VERSION 5.8 ;
BUSBITCHARS "[]" ;
DIVIDERCHAR "/" ;
UNITS
    DATABASE MICRONS 1000 ;
END UNITS

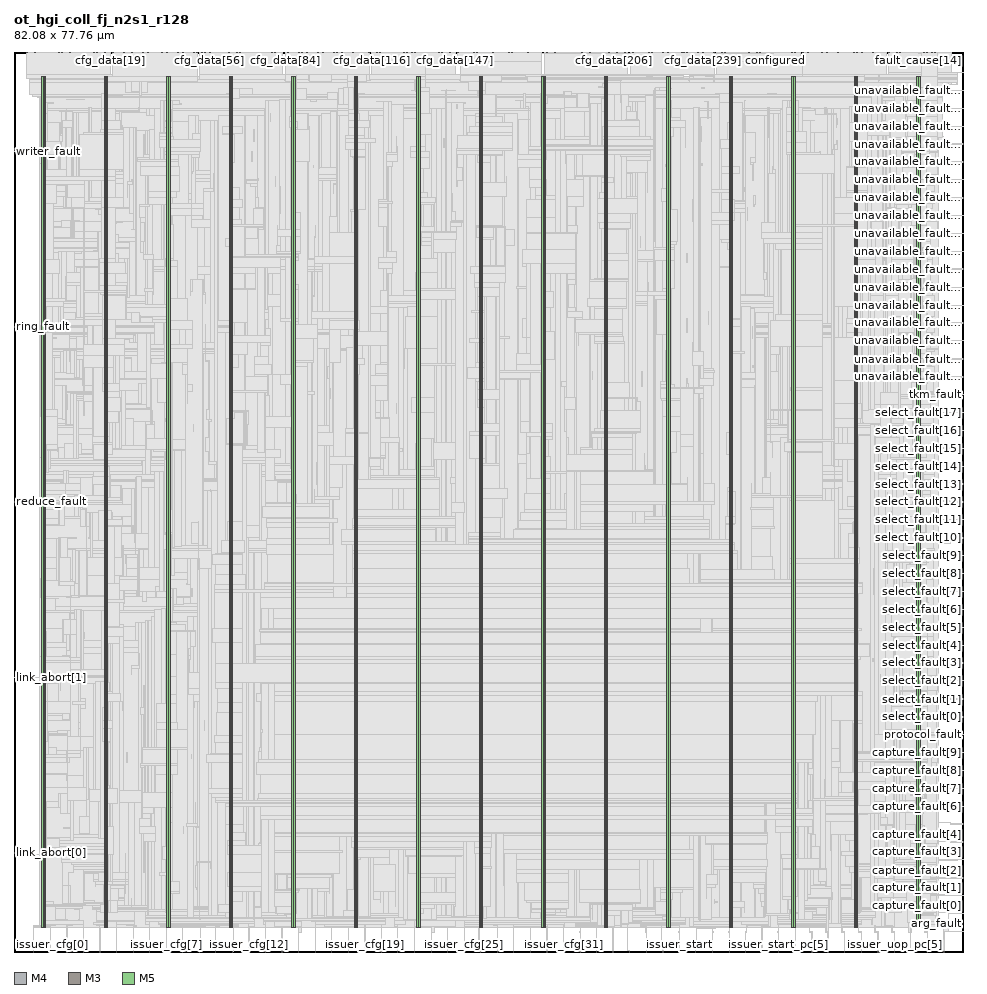
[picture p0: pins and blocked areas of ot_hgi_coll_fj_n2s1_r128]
MACRO ot_hgi_coll_fj_n2s1_r128
  FOREIGN ot_hgi_coll_fj_n2s1_r128 0 0 ;
  CLASS BLOCK ;
  SIZE 82.08 BY 77.76 ;
  PIN arg_fault
    DIRECTION INPUT ;
    USE SIGNAL ;
    PORT
      LAYER M4 ;
        RECT  81.996 1.776 82.08 1.8 ;
    END
  END arg_fault
  PIN capture_fault[0]
    DIRECTION INPUT ;
    USE SIGNAL ;
    PORT
      LAYER M4 ;
        RECT  81.996 3.312 82.08 3.336 ;
    END
  END capture_fault[0]
  PIN capture_fault[1]
    DIRECTION INPUT ;
    USE SIGNAL ;
    PORT
      LAYER M4 ;
        RECT  81.996 4.848 82.08 4.872 ;
    END
  END capture_fault[1]
  PIN capture_fault[2]
    DIRECTION INPUT ;
    USE SIGNAL ;
    PORT
      LAYER M4 ;
        RECT  81.996 6.384 82.08 6.408 ;
    END
  END capture_fault[2]
  PIN capture_fault[3]
    DIRECTION INPUT ;
    USE SIGNAL ;
    PORT
      LAYER M4 ;
        RECT  81.996 7.968 82.08 7.992 ;
    END
  END capture_fault[3]
  PIN capture_fault[4]
    DIRECTION INPUT ;
    USE SIGNAL ;
    PORT
      LAYER M4 ;
        RECT  81.996 9.504 82.08 9.528 ;
    END
  END capture_fault[4]
  PIN capture_fault[5]
    DIRECTION INPUT ;
    USE SIGNAL ;
    PORT
      LAYER M4 ;
        RECT  81.996 11.04 82.08 11.064 ;
    END
  END capture_fault[5]
  PIN capture_fault[6]
    DIRECTION INPUT ;
    USE SIGNAL ;
    PORT
      LAYER M4 ;
        RECT  81.996 12.576 82.08 12.6 ;
    END
  END capture_fault[6]
  PIN capture_fault[7]
    DIRECTION INPUT ;
    USE SIGNAL ;
    PORT
      LAYER M4 ;
        RECT  81.996 14.112 82.08 14.136 ;
    END
  END capture_fault[7]
  PIN capture_fault[8]
    DIRECTION INPUT ;
    USE SIGNAL ;
    PORT
      LAYER M4 ;
        RECT  81.996 15.696 82.08 15.72 ;
    END
  END capture_fault[8]
  PIN capture_fault[9]
    DIRECTION INPUT ;
    USE SIGNAL ;
    PORT
      LAYER M4 ;
        RECT  81.996 17.232 82.08 17.256 ;
    END
  END capture_fault[9]
  PIN cfg_addr[0]
    DIRECTION INPUT ;
    USE SIGNAL ;
    PORT
      LAYER M3 ;
        RECT  1.116 77.722 1.134 77.76 ;
    END
  END cfg_addr[0]
  PIN cfg_addr[10]
    DIRECTION INPUT ;
    USE SIGNAL ;
    PORT
      LAYER M3 ;
        RECT  3.42 77.722 3.438 77.76 ;
    END
  END cfg_addr[10]
  PIN cfg_addr[11]
    DIRECTION INPUT ;
    USE SIGNAL ;
    PORT
      LAYER M3 ;
        RECT  3.672 77.722 3.69 77.76 ;
    END
  END cfg_addr[11]
  PIN cfg_addr[1]
    DIRECTION INPUT ;
    USE SIGNAL ;
    PORT
      LAYER M3 ;
        RECT  1.332 77.722 1.35 77.76 ;
    END
  END cfg_addr[1]
  PIN cfg_addr[2]
    DIRECTION INPUT ;
    USE SIGNAL ;
    PORT
      LAYER M3 ;
        RECT  1.584 77.722 1.602 77.76 ;
    END
  END cfg_addr[2]
  PIN cfg_addr[3]
    DIRECTION INPUT ;
    USE SIGNAL ;
    PORT
      LAYER M3 ;
        RECT  1.8 77.722 1.818 77.76 ;
    END
  END cfg_addr[3]
  PIN cfg_addr[4]
    DIRECTION INPUT ;
    USE SIGNAL ;
    PORT
      LAYER M3 ;
        RECT  2.052 77.722 2.07 77.76 ;
    END
  END cfg_addr[4]
  PIN cfg_addr[5]
    DIRECTION INPUT ;
    USE SIGNAL ;
    PORT
      LAYER M3 ;
        RECT  2.268 77.722 2.286 77.76 ;
    END
  END cfg_addr[5]
  PIN cfg_addr[6]
    DIRECTION INPUT ;
    USE SIGNAL ;
    PORT
      LAYER M3 ;
        RECT  2.52 77.722 2.538 77.76 ;
    END
  END cfg_addr[6]
  PIN cfg_addr[7]
    DIRECTION INPUT ;
    USE SIGNAL ;
    PORT
      LAYER M3 ;
        RECT  2.736 77.722 2.754 77.76 ;
    END
  END cfg_addr[7]
  PIN cfg_addr[8]
    DIRECTION INPUT ;
    USE SIGNAL ;
    PORT
      LAYER M3 ;
        RECT  2.988 77.722 3.006 77.76 ;
    END
  END cfg_addr[8]
  PIN cfg_addr[9]
    DIRECTION INPUT ;
    USE SIGNAL ;
    PORT
      LAYER M3 ;
        RECT  3.204 77.722 3.222 77.76 ;
    END
  END cfg_addr[9]
  PIN cfg_data[0]
    DIRECTION INPUT ;
    USE SIGNAL ;
    PORT
      LAYER M3 ;
        RECT  3.888 77.722 3.906 77.76 ;
    END
  END cfg_data[0]
  PIN cfg_data[100]
    DIRECTION INPUT ;
    USE SIGNAL ;
    PORT
      LAYER M5 ;
        RECT  27.168 77.676 27.192 77.76 ;
    END
  END cfg_data[100]
  PIN cfg_data[101]
    DIRECTION INPUT ;
    USE SIGNAL ;
    PORT
      LAYER M5 ;
        RECT  27.408 77.676 27.432 77.76 ;
    END
  END cfg_data[101]
  PIN cfg_data[102]
    DIRECTION INPUT ;
    USE SIGNAL ;
    PORT
      LAYER M5 ;
        RECT  27.648 77.676 27.672 77.76 ;
    END
  END cfg_data[102]
  PIN cfg_data[103]
    DIRECTION INPUT ;
    USE SIGNAL ;
    PORT
      LAYER M5 ;
        RECT  27.888 77.676 27.912 77.76 ;
    END
  END cfg_data[103]
  PIN cfg_data[104]
    DIRECTION INPUT ;
    USE SIGNAL ;
    PORT
      LAYER M5 ;
        RECT  28.128 77.676 28.152 77.76 ;
    END
  END cfg_data[104]
  PIN cfg_data[105]
    DIRECTION INPUT ;
    USE SIGNAL ;
    PORT
      LAYER M5 ;
        RECT  28.32 77.676 28.344 77.76 ;
    END
  END cfg_data[105]
  PIN cfg_data[106]
    DIRECTION INPUT ;
    USE SIGNAL ;
    PORT
      LAYER M5 ;
        RECT  28.56 77.676 28.584 77.76 ;
    END
  END cfg_data[106]
  PIN cfg_data[107]
    DIRECTION INPUT ;
    USE SIGNAL ;
    PORT
      LAYER M5 ;
        RECT  28.8 77.676 28.824 77.76 ;
    END
  END cfg_data[107]
  PIN cfg_data[108]
    DIRECTION INPUT ;
    USE SIGNAL ;
    PORT
      LAYER M5 ;
        RECT  29.04 77.676 29.064 77.76 ;
    END
  END cfg_data[108]
  PIN cfg_data[109]
    DIRECTION INPUT ;
    USE SIGNAL ;
    PORT
      LAYER M5 ;
        RECT  29.28 77.676 29.304 77.76 ;
    END
  END cfg_data[109]
  PIN cfg_data[10]
    DIRECTION INPUT ;
    USE SIGNAL ;
    PORT
      LAYER M3 ;
        RECT  6.228 77.722 6.246 77.76 ;
    END
  END cfg_data[10]
  PIN cfg_data[110]
    DIRECTION INPUT ;
    USE SIGNAL ;
    PORT
      LAYER M5 ;
        RECT  29.52 77.676 29.544 77.76 ;
    END
  END cfg_data[110]
  PIN cfg_data[111]
    DIRECTION INPUT ;
    USE SIGNAL ;
    PORT
      LAYER M5 ;
        RECT  29.76 77.676 29.784 77.76 ;
    END
  END cfg_data[111]
  PIN cfg_data[112]
    DIRECTION INPUT ;
    USE SIGNAL ;
    PORT
      LAYER M5 ;
        RECT  29.952 77.676 29.976 77.76 ;
    END
  END cfg_data[112]
  PIN cfg_data[113]
    DIRECTION INPUT ;
    USE SIGNAL ;
    PORT
      LAYER M5 ;
        RECT  30.192 77.676 30.216 77.76 ;
    END
  END cfg_data[113]
  PIN cfg_data[114]
    DIRECTION INPUT ;
    USE SIGNAL ;
    PORT
      LAYER M5 ;
        RECT  30.432 77.676 30.456 77.76 ;
    END
  END cfg_data[114]
  PIN cfg_data[115]
    DIRECTION INPUT ;
    USE SIGNAL ;
    PORT
      LAYER M5 ;
        RECT  30.672 77.676 30.696 77.76 ;
    END
  END cfg_data[115]
  PIN cfg_data[116]
    DIRECTION INPUT ;
    USE SIGNAL ;
    PORT
      LAYER M3 ;
        RECT  30.888 77.722 30.906 77.76 ;
    END
  END cfg_data[116]
  PIN cfg_data[117]
    DIRECTION INPUT ;
    USE SIGNAL ;
    PORT
      LAYER M3 ;
        RECT  31.14 77.722 31.158 77.76 ;
    END
  END cfg_data[117]
  PIN cfg_data[118]
    DIRECTION INPUT ;
    USE SIGNAL ;
    PORT
      LAYER M3 ;
        RECT  31.356 77.722 31.374 77.76 ;
    END
  END cfg_data[118]
  PIN cfg_data[119]
    DIRECTION INPUT ;
    USE SIGNAL ;
    PORT
      LAYER M3 ;
        RECT  31.608 77.722 31.626 77.76 ;
    END
  END cfg_data[119]
  PIN cfg_data[11]
    DIRECTION INPUT ;
    USE SIGNAL ;
    PORT
      LAYER M3 ;
        RECT  6.48 77.722 6.498 77.76 ;
    END
  END cfg_data[11]
  PIN cfg_data[120]
    DIRECTION INPUT ;
    USE SIGNAL ;
    PORT
      LAYER M3 ;
        RECT  31.824 77.722 31.842 77.76 ;
    END
  END cfg_data[120]
  PIN cfg_data[121]
    DIRECTION INPUT ;
    USE SIGNAL ;
    PORT
      LAYER M3 ;
        RECT  32.076 77.722 32.094 77.76 ;
    END
  END cfg_data[121]
  PIN cfg_data[122]
    DIRECTION INPUT ;
    USE SIGNAL ;
    PORT
      LAYER M3 ;
        RECT  32.292 77.722 32.31 77.76 ;
    END
  END cfg_data[122]
  PIN cfg_data[123]
    DIRECTION INPUT ;
    USE SIGNAL ;
    PORT
      LAYER M3 ;
        RECT  32.544 77.722 32.562 77.76 ;
    END
  END cfg_data[123]
  PIN cfg_data[124]
    DIRECTION INPUT ;
    USE SIGNAL ;
    PORT
      LAYER M3 ;
        RECT  32.76 77.722 32.778 77.76 ;
    END
  END cfg_data[124]
  PIN cfg_data[125]
    DIRECTION INPUT ;
    USE SIGNAL ;
    PORT
      LAYER M3 ;
        RECT  33.012 77.722 33.03 77.76 ;
    END
  END cfg_data[125]
  PIN cfg_data[126]
    DIRECTION INPUT ;
    USE SIGNAL ;
    PORT
      LAYER M3 ;
        RECT  33.228 77.722 33.246 77.76 ;
    END
  END cfg_data[126]
  PIN cfg_data[127]
    DIRECTION INPUT ;
    USE SIGNAL ;
    PORT
      LAYER M3 ;
        RECT  33.48 77.722 33.498 77.76 ;
    END
  END cfg_data[127]
  PIN cfg_data[128]
    DIRECTION INPUT ;
    USE SIGNAL ;
    PORT
      LAYER M3 ;
        RECT  33.696 77.722 33.714 77.76 ;
    END
  END cfg_data[128]
  PIN cfg_data[129]
    DIRECTION INPUT ;
    USE SIGNAL ;
    PORT
      LAYER M3 ;
        RECT  33.948 77.722 33.966 77.76 ;
    END
  END cfg_data[129]
  PIN cfg_data[12]
    DIRECTION INPUT ;
    USE SIGNAL ;
    PORT
      LAYER M3 ;
        RECT  6.696 77.722 6.714 77.76 ;
    END
  END cfg_data[12]
  PIN cfg_data[130]
    DIRECTION INPUT ;
    USE SIGNAL ;
    PORT
      LAYER M3 ;
        RECT  34.164 77.722 34.182 77.76 ;
    END
  END cfg_data[130]
  PIN cfg_data[131]
    DIRECTION INPUT ;
    USE SIGNAL ;
    PORT
      LAYER M3 ;
        RECT  34.38 77.722 34.398 77.76 ;
    END
  END cfg_data[131]
  PIN cfg_data[132]
    DIRECTION INPUT ;
    USE SIGNAL ;
    PORT
      LAYER M3 ;
        RECT  34.632 77.722 34.65 77.76 ;
    END
  END cfg_data[132]
  PIN cfg_data[133]
    DIRECTION INPUT ;
    USE SIGNAL ;
    PORT
      LAYER M3 ;
        RECT  34.848 77.722 34.866 77.76 ;
    END
  END cfg_data[133]
  PIN cfg_data[134]
    DIRECTION INPUT ;
    USE SIGNAL ;
    PORT
      LAYER M3 ;
        RECT  35.1 77.722 35.118 77.76 ;
    END
  END cfg_data[134]
  PIN cfg_data[135]
    DIRECTION INPUT ;
    USE SIGNAL ;
    PORT
      LAYER M3 ;
        RECT  35.316 77.722 35.334 77.76 ;
    END
  END cfg_data[135]
  PIN cfg_data[136]
    DIRECTION INPUT ;
    USE SIGNAL ;
    PORT
      LAYER M3 ;
        RECT  35.568 77.722 35.586 77.76 ;
    END
  END cfg_data[136]
  PIN cfg_data[137]
    DIRECTION INPUT ;
    USE SIGNAL ;
    PORT
      LAYER M3 ;
        RECT  35.784 77.722 35.802 77.76 ;
    END
  END cfg_data[137]
  PIN cfg_data[138]
    DIRECTION INPUT ;
    USE SIGNAL ;
    PORT
      LAYER M3 ;
        RECT  36.036 77.722 36.054 77.76 ;
    END
  END cfg_data[138]
  PIN cfg_data[139]
    DIRECTION INPUT ;
    USE SIGNAL ;
    PORT
      LAYER M3 ;
        RECT  36.252 77.722 36.27 77.76 ;
    END
  END cfg_data[139]
  PIN cfg_data[13]
    DIRECTION INPUT ;
    USE SIGNAL ;
    PORT
      LAYER M3 ;
        RECT  6.912 77.722 6.93 77.76 ;
    END
  END cfg_data[13]
  PIN cfg_data[140]
    DIRECTION INPUT ;
    USE SIGNAL ;
    PORT
      LAYER M3 ;
        RECT  36.504 77.722 36.522 77.76 ;
    END
  END cfg_data[140]
  PIN cfg_data[141]
    DIRECTION INPUT ;
    USE SIGNAL ;
    PORT
      LAYER M3 ;
        RECT  36.72 77.722 36.738 77.76 ;
    END
  END cfg_data[141]
  PIN cfg_data[142]
    DIRECTION INPUT ;
    USE SIGNAL ;
    PORT
      LAYER M3 ;
        RECT  36.972 77.722 36.99 77.76 ;
    END
  END cfg_data[142]
  PIN cfg_data[143]
    DIRECTION INPUT ;
    USE SIGNAL ;
    PORT
      LAYER M3 ;
        RECT  37.188 77.722 37.206 77.76 ;
    END
  END cfg_data[143]
  PIN cfg_data[144]
    DIRECTION INPUT ;
    USE SIGNAL ;
    PORT
      LAYER M3 ;
        RECT  37.44 77.722 37.458 77.76 ;
    END
  END cfg_data[144]
  PIN cfg_data[145]
    DIRECTION INPUT ;
    USE SIGNAL ;
    PORT
      LAYER M3 ;
        RECT  37.656 77.722 37.674 77.76 ;
    END
  END cfg_data[145]
  PIN cfg_data[146]
    DIRECTION INPUT ;
    USE SIGNAL ;
    PORT
      LAYER M3 ;
        RECT  37.872 77.722 37.89 77.76 ;
    END
  END cfg_data[146]
  PIN cfg_data[147]
    DIRECTION INPUT ;
    USE SIGNAL ;
    PORT
      LAYER M3 ;
        RECT  38.124 77.722 38.142 77.76 ;
    END
  END cfg_data[147]
  PIN cfg_data[148]
    DIRECTION INPUT ;
    USE SIGNAL ;
    PORT
      LAYER M5 ;
        RECT  38.352 77.676 38.376 77.76 ;
    END
  END cfg_data[148]
  PIN cfg_data[149]
    DIRECTION INPUT ;
    USE SIGNAL ;
    PORT
      LAYER M5 ;
        RECT  38.592 77.676 38.616 77.76 ;
    END
  END cfg_data[149]
  PIN cfg_data[14]
    DIRECTION INPUT ;
    USE SIGNAL ;
    PORT
      LAYER M3 ;
        RECT  7.164 77.722 7.182 77.76 ;
    END
  END cfg_data[14]
  PIN cfg_data[150]
    DIRECTION INPUT ;
    USE SIGNAL ;
    PORT
      LAYER M5 ;
        RECT  38.832 77.676 38.856 77.76 ;
    END
  END cfg_data[150]
  PIN cfg_data[151]
    DIRECTION INPUT ;
    USE SIGNAL ;
    PORT
      LAYER M5 ;
        RECT  39.072 77.676 39.096 77.76 ;
    END
  END cfg_data[151]
  PIN cfg_data[152]
    DIRECTION INPUT ;
    USE SIGNAL ;
    PORT
      LAYER M5 ;
        RECT  39.264 77.676 39.288 77.76 ;
    END
  END cfg_data[152]
  PIN cfg_data[153]
    DIRECTION INPUT ;
    USE SIGNAL ;
    PORT
      LAYER M5 ;
        RECT  39.504 77.676 39.528 77.76 ;
    END
  END cfg_data[153]
  PIN cfg_data[154]
    DIRECTION INPUT ;
    USE SIGNAL ;
    PORT
      LAYER M5 ;
        RECT  39.744 77.676 39.768 77.76 ;
    END
  END cfg_data[154]
  PIN cfg_data[155]
    DIRECTION INPUT ;
    USE SIGNAL ;
    PORT
      LAYER M5 ;
        RECT  39.984 77.676 40.008 77.76 ;
    END
  END cfg_data[155]
  PIN cfg_data[156]
    DIRECTION INPUT ;
    USE SIGNAL ;
    PORT
      LAYER M5 ;
        RECT  40.224 77.676 40.248 77.76 ;
    END
  END cfg_data[156]
  PIN cfg_data[157]
    DIRECTION INPUT ;
    USE SIGNAL ;
    PORT
      LAYER M5 ;
        RECT  40.464 77.676 40.488 77.76 ;
    END
  END cfg_data[157]
  PIN cfg_data[158]
    DIRECTION INPUT ;
    USE SIGNAL ;
    PORT
      LAYER M5 ;
        RECT  40.656 77.676 40.68 77.76 ;
    END
  END cfg_data[158]
  PIN cfg_data[159]
    DIRECTION INPUT ;
    USE SIGNAL ;
    PORT
      LAYER M5 ;
        RECT  40.896 77.676 40.92 77.76 ;
    END
  END cfg_data[159]
  PIN cfg_data[15]
    DIRECTION INPUT ;
    USE SIGNAL ;
    PORT
      LAYER M3 ;
        RECT  7.38 77.722 7.398 77.76 ;
    END
  END cfg_data[15]
  PIN cfg_data[160]
    DIRECTION INPUT ;
    USE SIGNAL ;
    PORT
      LAYER M5 ;
        RECT  41.136 77.676 41.16 77.76 ;
    END
  END cfg_data[160]
  PIN cfg_data[161]
    DIRECTION INPUT ;
    USE SIGNAL ;
    PORT
      LAYER M5 ;
        RECT  41.376 77.676 41.4 77.76 ;
    END
  END cfg_data[161]
  PIN cfg_data[162]
    DIRECTION INPUT ;
    USE SIGNAL ;
    PORT
      LAYER M5 ;
        RECT  41.616 77.676 41.64 77.76 ;
    END
  END cfg_data[162]
  PIN cfg_data[163]
    DIRECTION INPUT ;
    USE SIGNAL ;
    PORT
      LAYER M5 ;
        RECT  41.856 77.676 41.88 77.76 ;
    END
  END cfg_data[163]
  PIN cfg_data[164]
    DIRECTION INPUT ;
    USE SIGNAL ;
    PORT
      LAYER M5 ;
        RECT  42.096 77.676 42.12 77.76 ;
    END
  END cfg_data[164]
  PIN cfg_data[165]
    DIRECTION INPUT ;
    USE SIGNAL ;
    PORT
      LAYER M5 ;
        RECT  42.288 77.676 42.312 77.76 ;
    END
  END cfg_data[165]
  PIN cfg_data[166]
    DIRECTION INPUT ;
    USE SIGNAL ;
    PORT
      LAYER M5 ;
        RECT  42.528 77.676 42.552 77.76 ;
    END
  END cfg_data[166]
  PIN cfg_data[167]
    DIRECTION INPUT ;
    USE SIGNAL ;
    PORT
      LAYER M5 ;
        RECT  42.768 77.676 42.792 77.76 ;
    END
  END cfg_data[167]
  PIN cfg_data[168]
    DIRECTION INPUT ;
    USE SIGNAL ;
    PORT
      LAYER M5 ;
        RECT  43.008 77.676 43.032 77.76 ;
    END
  END cfg_data[168]
  PIN cfg_data[169]
    DIRECTION INPUT ;
    USE SIGNAL ;
    PORT
      LAYER M5 ;
        RECT  43.248 77.676 43.272 77.76 ;
    END
  END cfg_data[169]
  PIN cfg_data[16]
    DIRECTION INPUT ;
    USE SIGNAL ;
    PORT
      LAYER M3 ;
        RECT  7.632 77.722 7.65 77.76 ;
    END
  END cfg_data[16]
  PIN cfg_data[170]
    DIRECTION INPUT ;
    USE SIGNAL ;
    PORT
      LAYER M5 ;
        RECT  43.488 77.676 43.512 77.76 ;
    END
  END cfg_data[170]
  PIN cfg_data[171]
    DIRECTION INPUT ;
    USE SIGNAL ;
    PORT
      LAYER M5 ;
        RECT  43.728 77.676 43.752 77.76 ;
    END
  END cfg_data[171]
  PIN cfg_data[172]
    DIRECTION INPUT ;
    USE SIGNAL ;
    PORT
      LAYER M5 ;
        RECT  43.92 77.676 43.944 77.76 ;
    END
  END cfg_data[172]
  PIN cfg_data[173]
    DIRECTION INPUT ;
    USE SIGNAL ;
    PORT
      LAYER M5 ;
        RECT  44.16 77.676 44.184 77.76 ;
    END
  END cfg_data[173]
  PIN cfg_data[174]
    DIRECTION INPUT ;
    USE SIGNAL ;
    PORT
      LAYER M5 ;
        RECT  44.4 77.676 44.424 77.76 ;
    END
  END cfg_data[174]
  PIN cfg_data[175]
    DIRECTION INPUT ;
    USE SIGNAL ;
    PORT
      LAYER M5 ;
        RECT  44.64 77.676 44.664 77.76 ;
    END
  END cfg_data[175]
  PIN cfg_data[176]
    DIRECTION INPUT ;
    USE SIGNAL ;
    PORT
      LAYER M5 ;
        RECT  44.88 77.676 44.904 77.76 ;
    END
  END cfg_data[176]
  PIN cfg_data[177]
    DIRECTION INPUT ;
    USE SIGNAL ;
    PORT
      LAYER M5 ;
        RECT  45.12 77.676 45.144 77.76 ;
    END
  END cfg_data[177]
  PIN cfg_data[178]
    DIRECTION INPUT ;
    USE SIGNAL ;
    PORT
      LAYER M5 ;
        RECT  45.312 77.676 45.336 77.76 ;
    END
  END cfg_data[178]
  PIN cfg_data[179]
    DIRECTION INPUT ;
    USE SIGNAL ;
    PORT
      LAYER M5 ;
        RECT  45.552 77.676 45.576 77.76 ;
    END
  END cfg_data[179]
  PIN cfg_data[17]
    DIRECTION INPUT ;
    USE SIGNAL ;
    PORT
      LAYER M3 ;
        RECT  7.848 77.722 7.866 77.76 ;
    END
  END cfg_data[17]
  PIN cfg_data[180]
    DIRECTION INPUT ;
    USE SIGNAL ;
    PORT
      LAYER M3 ;
        RECT  45.792 77.722 45.81 77.76 ;
    END
  END cfg_data[180]
  PIN cfg_data[181]
    DIRECTION INPUT ;
    USE SIGNAL ;
    PORT
      LAYER M3 ;
        RECT  46.044 77.722 46.062 77.76 ;
    END
  END cfg_data[181]
  PIN cfg_data[182]
    DIRECTION INPUT ;
    USE SIGNAL ;
    PORT
      LAYER M3 ;
        RECT  46.26 77.722 46.278 77.76 ;
    END
  END cfg_data[182]
  PIN cfg_data[183]
    DIRECTION INPUT ;
    USE SIGNAL ;
    PORT
      LAYER M3 ;
        RECT  46.512 77.722 46.53 77.76 ;
    END
  END cfg_data[183]
  PIN cfg_data[184]
    DIRECTION INPUT ;
    USE SIGNAL ;
    PORT
      LAYER M3 ;
        RECT  46.728 77.722 46.746 77.76 ;
    END
  END cfg_data[184]
  PIN cfg_data[185]
    DIRECTION INPUT ;
    USE SIGNAL ;
    PORT
      LAYER M3 ;
        RECT  46.98 77.722 46.998 77.76 ;
    END
  END cfg_data[185]
  PIN cfg_data[186]
    DIRECTION INPUT ;
    USE SIGNAL ;
    PORT
      LAYER M3 ;
        RECT  47.196 77.722 47.214 77.76 ;
    END
  END cfg_data[186]
  PIN cfg_data[187]
    DIRECTION INPUT ;
    USE SIGNAL ;
    PORT
      LAYER M3 ;
        RECT  47.448 77.722 47.466 77.76 ;
    END
  END cfg_data[187]
  PIN cfg_data[188]
    DIRECTION INPUT ;
    USE SIGNAL ;
    PORT
      LAYER M3 ;
        RECT  47.664 77.722 47.682 77.76 ;
    END
  END cfg_data[188]
  PIN cfg_data[189]
    DIRECTION INPUT ;
    USE SIGNAL ;
    PORT
      LAYER M3 ;
        RECT  47.916 77.722 47.934 77.76 ;
    END
  END cfg_data[189]
  PIN cfg_data[18]
    DIRECTION INPUT ;
    USE SIGNAL ;
    PORT
      LAYER M3 ;
        RECT  8.1 77.722 8.118 77.76 ;
    END
  END cfg_data[18]
  PIN cfg_data[190]
    DIRECTION INPUT ;
    USE SIGNAL ;
    PORT
      LAYER M3 ;
        RECT  48.132 77.722 48.15 77.76 ;
    END
  END cfg_data[190]
  PIN cfg_data[191]
    DIRECTION INPUT ;
    USE SIGNAL ;
    PORT
      LAYER M3 ;
        RECT  48.348 77.722 48.366 77.76 ;
    END
  END cfg_data[191]
  PIN cfg_data[192]
    DIRECTION INPUT ;
    USE SIGNAL ;
    PORT
      LAYER M3 ;
        RECT  48.6 77.722 48.618 77.76 ;
    END
  END cfg_data[192]
  PIN cfg_data[193]
    DIRECTION INPUT ;
    USE SIGNAL ;
    PORT
      LAYER M3 ;
        RECT  48.816 77.722 48.834 77.76 ;
    END
  END cfg_data[193]
  PIN cfg_data[194]
    DIRECTION INPUT ;
    USE SIGNAL ;
    PORT
      LAYER M3 ;
        RECT  49.068 77.722 49.086 77.76 ;
    END
  END cfg_data[194]
  PIN cfg_data[195]
    DIRECTION INPUT ;
    USE SIGNAL ;
    PORT
      LAYER M3 ;
        RECT  49.284 77.722 49.302 77.76 ;
    END
  END cfg_data[195]
  PIN cfg_data[196]
    DIRECTION INPUT ;
    USE SIGNAL ;
    PORT
      LAYER M3 ;
        RECT  49.536 77.722 49.554 77.76 ;
    END
  END cfg_data[196]
  PIN cfg_data[197]
    DIRECTION INPUT ;
    USE SIGNAL ;
    PORT
      LAYER M3 ;
        RECT  49.752 77.722 49.77 77.76 ;
    END
  END cfg_data[197]
  PIN cfg_data[198]
    DIRECTION INPUT ;
    USE SIGNAL ;
    PORT
      LAYER M3 ;
        RECT  50.004 77.722 50.022 77.76 ;
    END
  END cfg_data[198]
  PIN cfg_data[199]
    DIRECTION INPUT ;
    USE SIGNAL ;
    PORT
      LAYER M3 ;
        RECT  50.22 77.722 50.238 77.76 ;
    END
  END cfg_data[199]
  PIN cfg_data[19]
    DIRECTION INPUT ;
    USE SIGNAL ;
    PORT
      LAYER M3 ;
        RECT  8.316 77.722 8.334 77.76 ;
    END
  END cfg_data[19]
  PIN cfg_data[1]
    DIRECTION INPUT ;
    USE SIGNAL ;
    PORT
      LAYER M3 ;
        RECT  4.14 77.722 4.158 77.76 ;
    END
  END cfg_data[1]
  PIN cfg_data[200]
    DIRECTION INPUT ;
    USE SIGNAL ;
    PORT
      LAYER M3 ;
        RECT  50.472 77.722 50.49 77.76 ;
    END
  END cfg_data[200]
  PIN cfg_data[201]
    DIRECTION INPUT ;
    USE SIGNAL ;
    PORT
      LAYER M3 ;
        RECT  50.688 77.722 50.706 77.76 ;
    END
  END cfg_data[201]
  PIN cfg_data[202]
    DIRECTION INPUT ;
    USE SIGNAL ;
    PORT
      LAYER M3 ;
        RECT  50.94 77.722 50.958 77.76 ;
    END
  END cfg_data[202]
  PIN cfg_data[203]
    DIRECTION INPUT ;
    USE SIGNAL ;
    PORT
      LAYER M3 ;
        RECT  51.156 77.722 51.174 77.76 ;
    END
  END cfg_data[203]
  PIN cfg_data[204]
    DIRECTION INPUT ;
    USE SIGNAL ;
    PORT
      LAYER M3 ;
        RECT  51.408 77.722 51.426 77.76 ;
    END
  END cfg_data[204]
  PIN cfg_data[205]
    DIRECTION INPUT ;
    USE SIGNAL ;
    PORT
      LAYER M3 ;
        RECT  51.624 77.722 51.642 77.76 ;
    END
  END cfg_data[205]
  PIN cfg_data[206]
    DIRECTION INPUT ;
    USE SIGNAL ;
    PORT
      LAYER M3 ;
        RECT  51.84 77.722 51.858 77.76 ;
    END
  END cfg_data[206]
  PIN cfg_data[207]
    DIRECTION INPUT ;
    USE SIGNAL ;
    PORT
      LAYER M3 ;
        RECT  52.092 77.722 52.11 77.76 ;
    END
  END cfg_data[207]
  PIN cfg_data[208]
    DIRECTION INPUT ;
    USE SIGNAL ;
    PORT
      LAYER M3 ;
        RECT  52.308 77.722 52.326 77.76 ;
    END
  END cfg_data[208]
  PIN cfg_data[209]
    DIRECTION INPUT ;
    USE SIGNAL ;
    PORT
      LAYER M3 ;
        RECT  52.56 77.722 52.578 77.76 ;
    END
  END cfg_data[209]
  PIN cfg_data[20]
    DIRECTION INPUT ;
    USE SIGNAL ;
    PORT
      LAYER M5 ;
        RECT  8.544 77.676 8.568 77.76 ;
    END
  END cfg_data[20]
  PIN cfg_data[210]
    DIRECTION INPUT ;
    USE SIGNAL ;
    PORT
      LAYER M3 ;
        RECT  52.776 77.722 52.794 77.76 ;
    END
  END cfg_data[210]
  PIN cfg_data[211]
    DIRECTION INPUT ;
    USE SIGNAL ;
    PORT
      LAYER M3 ;
        RECT  53.028 77.722 53.046 77.76 ;
    END
  END cfg_data[211]
  PIN cfg_data[212]
    DIRECTION INPUT ;
    USE SIGNAL ;
    PORT
      LAYER M5 ;
        RECT  53.232 77.676 53.256 77.76 ;
    END
  END cfg_data[212]
  PIN cfg_data[213]
    DIRECTION INPUT ;
    USE SIGNAL ;
    PORT
      LAYER M5 ;
        RECT  53.472 77.676 53.496 77.76 ;
    END
  END cfg_data[213]
  PIN cfg_data[214]
    DIRECTION INPUT ;
    USE SIGNAL ;
    PORT
      LAYER M5 ;
        RECT  53.712 77.676 53.736 77.76 ;
    END
  END cfg_data[214]
  PIN cfg_data[215]
    DIRECTION INPUT ;
    USE SIGNAL ;
    PORT
      LAYER M5 ;
        RECT  53.952 77.676 53.976 77.76 ;
    END
  END cfg_data[215]
  PIN cfg_data[216]
    DIRECTION INPUT ;
    USE SIGNAL ;
    PORT
      LAYER M5 ;
        RECT  54.192 77.676 54.216 77.76 ;
    END
  END cfg_data[216]
  PIN cfg_data[217]
    DIRECTION INPUT ;
    USE SIGNAL ;
    PORT
      LAYER M5 ;
        RECT  54.432 77.676 54.456 77.76 ;
    END
  END cfg_data[217]
  PIN cfg_data[218]
    DIRECTION INPUT ;
    USE SIGNAL ;
    PORT
      LAYER M5 ;
        RECT  54.624 77.676 54.648 77.76 ;
    END
  END cfg_data[218]
  PIN cfg_data[219]
    DIRECTION INPUT ;
    USE SIGNAL ;
    PORT
      LAYER M5 ;
        RECT  54.864 77.676 54.888 77.76 ;
    END
  END cfg_data[219]
  PIN cfg_data[21]
    DIRECTION INPUT ;
    USE SIGNAL ;
    PORT
      LAYER M5 ;
        RECT  8.784 77.676 8.808 77.76 ;
    END
  END cfg_data[21]
  PIN cfg_data[220]
    DIRECTION INPUT ;
    USE SIGNAL ;
    PORT
      LAYER M5 ;
        RECT  55.104 77.676 55.128 77.76 ;
    END
  END cfg_data[220]
  PIN cfg_data[221]
    DIRECTION INPUT ;
    USE SIGNAL ;
    PORT
      LAYER M5 ;
        RECT  55.344 77.676 55.368 77.76 ;
    END
  END cfg_data[221]
  PIN cfg_data[222]
    DIRECTION INPUT ;
    USE SIGNAL ;
    PORT
      LAYER M5 ;
        RECT  55.584 77.676 55.608 77.76 ;
    END
  END cfg_data[222]
  PIN cfg_data[223]
    DIRECTION INPUT ;
    USE SIGNAL ;
    PORT
      LAYER M5 ;
        RECT  55.824 77.676 55.848 77.76 ;
    END
  END cfg_data[223]
  PIN cfg_data[224]
    DIRECTION INPUT ;
    USE SIGNAL ;
    PORT
      LAYER M5 ;
        RECT  56.064 77.676 56.088 77.76 ;
    END
  END cfg_data[224]
  PIN cfg_data[225]
    DIRECTION INPUT ;
    USE SIGNAL ;
    PORT
      LAYER M5 ;
        RECT  56.256 77.676 56.28 77.76 ;
    END
  END cfg_data[225]
  PIN cfg_data[226]
    DIRECTION INPUT ;
    USE SIGNAL ;
    PORT
      LAYER M5 ;
        RECT  56.496 77.676 56.52 77.76 ;
    END
  END cfg_data[226]
  PIN cfg_data[227]
    DIRECTION INPUT ;
    USE SIGNAL ;
    PORT
      LAYER M5 ;
        RECT  56.736 77.676 56.76 77.76 ;
    END
  END cfg_data[227]
  PIN cfg_data[228]
    DIRECTION INPUT ;
    USE SIGNAL ;
    PORT
      LAYER M5 ;
        RECT  56.976 77.676 57 77.76 ;
    END
  END cfg_data[228]
  PIN cfg_data[229]
    DIRECTION INPUT ;
    USE SIGNAL ;
    PORT
      LAYER M5 ;
        RECT  57.216 77.676 57.24 77.76 ;
    END
  END cfg_data[229]
  PIN cfg_data[22]
    DIRECTION INPUT ;
    USE SIGNAL ;
    PORT
      LAYER M5 ;
        RECT  9.024 77.676 9.048 77.76 ;
    END
  END cfg_data[22]
  PIN cfg_data[230]
    DIRECTION INPUT ;
    USE SIGNAL ;
    PORT
      LAYER M5 ;
        RECT  57.456 77.676 57.48 77.76 ;
    END
  END cfg_data[230]
  PIN cfg_data[231]
    DIRECTION INPUT ;
    USE SIGNAL ;
    PORT
      LAYER M5 ;
        RECT  57.696 77.676 57.72 77.76 ;
    END
  END cfg_data[231]
  PIN cfg_data[232]
    DIRECTION INPUT ;
    USE SIGNAL ;
    PORT
      LAYER M5 ;
        RECT  57.888 77.676 57.912 77.76 ;
    END
  END cfg_data[232]
  PIN cfg_data[233]
    DIRECTION INPUT ;
    USE SIGNAL ;
    PORT
      LAYER M5 ;
        RECT  58.128 77.676 58.152 77.76 ;
    END
  END cfg_data[233]
  PIN cfg_data[234]
    DIRECTION INPUT ;
    USE SIGNAL ;
    PORT
      LAYER M5 ;
        RECT  58.368 77.676 58.392 77.76 ;
    END
  END cfg_data[234]
  PIN cfg_data[235]
    DIRECTION INPUT ;
    USE SIGNAL ;
    PORT
      LAYER M5 ;
        RECT  58.608 77.676 58.632 77.76 ;
    END
  END cfg_data[235]
  PIN cfg_data[236]
    DIRECTION INPUT ;
    USE SIGNAL ;
    PORT
      LAYER M5 ;
        RECT  58.848 77.676 58.872 77.76 ;
    END
  END cfg_data[236]
  PIN cfg_data[237]
    DIRECTION INPUT ;
    USE SIGNAL ;
    PORT
      LAYER M5 ;
        RECT  59.088 77.676 59.112 77.76 ;
    END
  END cfg_data[237]
  PIN cfg_data[238]
    DIRECTION INPUT ;
    USE SIGNAL ;
    PORT
      LAYER M5 ;
        RECT  59.28 77.676 59.304 77.76 ;
    END
  END cfg_data[238]
  PIN cfg_data[239]
    DIRECTION INPUT ;
    USE SIGNAL ;
    PORT
      LAYER M5 ;
        RECT  59.52 77.676 59.544 77.76 ;
    END
  END cfg_data[239]
  PIN cfg_data[23]
    DIRECTION INPUT ;
    USE SIGNAL ;
    PORT
      LAYER M5 ;
        RECT  9.264 77.676 9.288 77.76 ;
    END
  END cfg_data[23]
  PIN cfg_data[240]
    DIRECTION INPUT ;
    USE SIGNAL ;
    PORT
      LAYER M5 ;
        RECT  59.76 77.676 59.784 77.76 ;
    END
  END cfg_data[240]
  PIN cfg_data[241]
    DIRECTION INPUT ;
    USE SIGNAL ;
    PORT
      LAYER M5 ;
        RECT  60 77.676 60.024 77.76 ;
    END
  END cfg_data[241]
  PIN cfg_data[242]
    DIRECTION INPUT ;
    USE SIGNAL ;
    PORT
      LAYER M5 ;
        RECT  60.24 77.676 60.264 77.76 ;
    END
  END cfg_data[242]
  PIN cfg_data[243]
    DIRECTION INPUT ;
    USE SIGNAL ;
    PORT
      LAYER M5 ;
        RECT  60.48 77.676 60.504 77.76 ;
    END
  END cfg_data[243]
  PIN cfg_data[244]
    DIRECTION INPUT ;
    USE SIGNAL ;
    PORT
      LAYER M3 ;
        RECT  60.696 77.722 60.714 77.76 ;
    END
  END cfg_data[244]
  PIN cfg_data[245]
    DIRECTION INPUT ;
    USE SIGNAL ;
    PORT
      LAYER M3 ;
        RECT  60.948 77.722 60.966 77.76 ;
    END
  END cfg_data[245]
  PIN cfg_data[246]
    DIRECTION INPUT ;
    USE SIGNAL ;
    PORT
      LAYER M3 ;
        RECT  61.164 77.722 61.182 77.76 ;
    END
  END cfg_data[246]
  PIN cfg_data[247]
    DIRECTION INPUT ;
    USE SIGNAL ;
    PORT
      LAYER M3 ;
        RECT  61.416 77.722 61.434 77.76 ;
    END
  END cfg_data[247]
  PIN cfg_data[248]
    DIRECTION INPUT ;
    USE SIGNAL ;
    PORT
      LAYER M3 ;
        RECT  61.632 77.722 61.65 77.76 ;
    END
  END cfg_data[248]
  PIN cfg_data[249]
    DIRECTION INPUT ;
    USE SIGNAL ;
    PORT
      LAYER M3 ;
        RECT  61.884 77.722 61.902 77.76 ;
    END
  END cfg_data[249]
  PIN cfg_data[24]
    DIRECTION INPUT ;
    USE SIGNAL ;
    PORT
      LAYER M5 ;
        RECT  9.504 77.676 9.528 77.76 ;
    END
  END cfg_data[24]
  PIN cfg_data[250]
    DIRECTION INPUT ;
    USE SIGNAL ;
    PORT
      LAYER M3 ;
        RECT  62.1 77.722 62.118 77.76 ;
    END
  END cfg_data[250]
  PIN cfg_data[251]
    DIRECTION INPUT ;
    USE SIGNAL ;
    PORT
      LAYER M3 ;
        RECT  62.316 77.722 62.334 77.76 ;
    END
  END cfg_data[251]
  PIN cfg_data[252]
    DIRECTION INPUT ;
    USE SIGNAL ;
    PORT
      LAYER M3 ;
        RECT  62.568 77.722 62.586 77.76 ;
    END
  END cfg_data[252]
  PIN cfg_data[253]
    DIRECTION INPUT ;
    USE SIGNAL ;
    PORT
      LAYER M3 ;
        RECT  62.784 77.722 62.802 77.76 ;
    END
  END cfg_data[253]
  PIN cfg_data[254]
    DIRECTION INPUT ;
    USE SIGNAL ;
    PORT
      LAYER M3 ;
        RECT  63.036 77.722 63.054 77.76 ;
    END
  END cfg_data[254]
  PIN cfg_data[255]
    DIRECTION INPUT ;
    USE SIGNAL ;
    PORT
      LAYER M3 ;
        RECT  63.252 77.722 63.27 77.76 ;
    END
  END cfg_data[255]
  PIN cfg_data[25]
    DIRECTION INPUT ;
    USE SIGNAL ;
    PORT
      LAYER M5 ;
        RECT  9.696 77.676 9.72 77.76 ;
    END
  END cfg_data[25]
  PIN cfg_data[26]
    DIRECTION INPUT ;
    USE SIGNAL ;
    PORT
      LAYER M5 ;
        RECT  9.936 77.676 9.96 77.76 ;
    END
  END cfg_data[26]
  PIN cfg_data[27]
    DIRECTION INPUT ;
    USE SIGNAL ;
    PORT
      LAYER M5 ;
        RECT  10.176 77.676 10.2 77.76 ;
    END
  END cfg_data[27]
  PIN cfg_data[28]
    DIRECTION INPUT ;
    USE SIGNAL ;
    PORT
      LAYER M5 ;
        RECT  10.416 77.676 10.44 77.76 ;
    END
  END cfg_data[28]
  PIN cfg_data[29]
    DIRECTION INPUT ;
    USE SIGNAL ;
    PORT
      LAYER M5 ;
        RECT  10.656 77.676 10.68 77.76 ;
    END
  END cfg_data[29]
  PIN cfg_data[2]
    DIRECTION INPUT ;
    USE SIGNAL ;
    PORT
      LAYER M3 ;
        RECT  4.356 77.722 4.374 77.76 ;
    END
  END cfg_data[2]
  PIN cfg_data[30]
    DIRECTION INPUT ;
    USE SIGNAL ;
    PORT
      LAYER M5 ;
        RECT  10.896 77.676 10.92 77.76 ;
    END
  END cfg_data[30]
  PIN cfg_data[31]
    DIRECTION INPUT ;
    USE SIGNAL ;
    PORT
      LAYER M5 ;
        RECT  11.136 77.676 11.16 77.76 ;
    END
  END cfg_data[31]
  PIN cfg_data[32]
    DIRECTION INPUT ;
    USE SIGNAL ;
    PORT
      LAYER M5 ;
        RECT  11.328 77.676 11.352 77.76 ;
    END
  END cfg_data[32]
  PIN cfg_data[33]
    DIRECTION INPUT ;
    USE SIGNAL ;
    PORT
      LAYER M5 ;
        RECT  11.568 77.676 11.592 77.76 ;
    END
  END cfg_data[33]
  PIN cfg_data[34]
    DIRECTION INPUT ;
    USE SIGNAL ;
    PORT
      LAYER M5 ;
        RECT  11.808 77.676 11.832 77.76 ;
    END
  END cfg_data[34]
  PIN cfg_data[35]
    DIRECTION INPUT ;
    USE SIGNAL ;
    PORT
      LAYER M5 ;
        RECT  12.048 77.676 12.072 77.76 ;
    END
  END cfg_data[35]
  PIN cfg_data[36]
    DIRECTION INPUT ;
    USE SIGNAL ;
    PORT
      LAYER M5 ;
        RECT  12.288 77.676 12.312 77.76 ;
    END
  END cfg_data[36]
  PIN cfg_data[37]
    DIRECTION INPUT ;
    USE SIGNAL ;
    PORT
      LAYER M5 ;
        RECT  12.528 77.676 12.552 77.76 ;
    END
  END cfg_data[37]
  PIN cfg_data[38]
    DIRECTION INPUT ;
    USE SIGNAL ;
    PORT
      LAYER M5 ;
        RECT  12.768 77.676 12.792 77.76 ;
    END
  END cfg_data[38]
  PIN cfg_data[39]
    DIRECTION INPUT ;
    USE SIGNAL ;
    PORT
      LAYER M5 ;
        RECT  12.96 77.676 12.984 77.76 ;
    END
  END cfg_data[39]
  PIN cfg_data[3]
    DIRECTION INPUT ;
    USE SIGNAL ;
    PORT
      LAYER M3 ;
        RECT  4.608 77.722 4.626 77.76 ;
    END
  END cfg_data[3]
  PIN cfg_data[40]
    DIRECTION INPUT ;
    USE SIGNAL ;
    PORT
      LAYER M5 ;
        RECT  13.2 77.676 13.224 77.76 ;
    END
  END cfg_data[40]
  PIN cfg_data[41]
    DIRECTION INPUT ;
    USE SIGNAL ;
    PORT
      LAYER M5 ;
        RECT  13.44 77.676 13.464 77.76 ;
    END
  END cfg_data[41]
  PIN cfg_data[42]
    DIRECTION INPUT ;
    USE SIGNAL ;
    PORT
      LAYER M5 ;
        RECT  13.68 77.676 13.704 77.76 ;
    END
  END cfg_data[42]
  PIN cfg_data[43]
    DIRECTION INPUT ;
    USE SIGNAL ;
    PORT
      LAYER M5 ;
        RECT  13.92 77.676 13.944 77.76 ;
    END
  END cfg_data[43]
  PIN cfg_data[44]
    DIRECTION INPUT ;
    USE SIGNAL ;
    PORT
      LAYER M5 ;
        RECT  14.16 77.676 14.184 77.76 ;
    END
  END cfg_data[44]
  PIN cfg_data[45]
    DIRECTION INPUT ;
    USE SIGNAL ;
    PORT
      LAYER M5 ;
        RECT  14.352 77.676 14.376 77.76 ;
    END
  END cfg_data[45]
  PIN cfg_data[46]
    DIRECTION INPUT ;
    USE SIGNAL ;
    PORT
      LAYER M5 ;
        RECT  14.592 77.676 14.616 77.76 ;
    END
  END cfg_data[46]
  PIN cfg_data[47]
    DIRECTION INPUT ;
    USE SIGNAL ;
    PORT
      LAYER M5 ;
        RECT  14.832 77.676 14.856 77.76 ;
    END
  END cfg_data[47]
  PIN cfg_data[48]
    DIRECTION INPUT ;
    USE SIGNAL ;
    PORT
      LAYER M5 ;
        RECT  15.072 77.676 15.096 77.76 ;
    END
  END cfg_data[48]
  PIN cfg_data[49]
    DIRECTION INPUT ;
    USE SIGNAL ;
    PORT
      LAYER M5 ;
        RECT  15.312 77.676 15.336 77.76 ;
    END
  END cfg_data[49]
  PIN cfg_data[4]
    DIRECTION INPUT ;
    USE SIGNAL ;
    PORT
      LAYER M3 ;
        RECT  4.824 77.722 4.842 77.76 ;
    END
  END cfg_data[4]
  PIN cfg_data[50]
    DIRECTION INPUT ;
    USE SIGNAL ;
    PORT
      LAYER M5 ;
        RECT  15.552 77.676 15.576 77.76 ;
    END
  END cfg_data[50]
  PIN cfg_data[51]
    DIRECTION INPUT ;
    USE SIGNAL ;
    PORT
      LAYER M5 ;
        RECT  15.792 77.676 15.816 77.76 ;
    END
  END cfg_data[51]
  PIN cfg_data[52]
    DIRECTION INPUT ;
    USE SIGNAL ;
    PORT
      LAYER M3 ;
        RECT  16.02 77.722 16.038 77.76 ;
    END
  END cfg_data[52]
  PIN cfg_data[53]
    DIRECTION INPUT ;
    USE SIGNAL ;
    PORT
      LAYER M3 ;
        RECT  16.236 77.722 16.254 77.76 ;
    END
  END cfg_data[53]
  PIN cfg_data[54]
    DIRECTION INPUT ;
    USE SIGNAL ;
    PORT
      LAYER M3 ;
        RECT  16.488 77.722 16.506 77.76 ;
    END
  END cfg_data[54]
  PIN cfg_data[55]
    DIRECTION INPUT ;
    USE SIGNAL ;
    PORT
      LAYER M3 ;
        RECT  16.704 77.722 16.722 77.76 ;
    END
  END cfg_data[55]
  PIN cfg_data[56]
    DIRECTION INPUT ;
    USE SIGNAL ;
    PORT
      LAYER M3 ;
        RECT  16.92 77.722 16.938 77.76 ;
    END
  END cfg_data[56]
  PIN cfg_data[57]
    DIRECTION INPUT ;
    USE SIGNAL ;
    PORT
      LAYER M3 ;
        RECT  17.172 77.722 17.19 77.76 ;
    END
  END cfg_data[57]
  PIN cfg_data[58]
    DIRECTION INPUT ;
    USE SIGNAL ;
    PORT
      LAYER M3 ;
        RECT  17.388 77.722 17.406 77.76 ;
    END
  END cfg_data[58]
  PIN cfg_data[59]
    DIRECTION INPUT ;
    USE SIGNAL ;
    PORT
      LAYER M3 ;
        RECT  17.64 77.722 17.658 77.76 ;
    END
  END cfg_data[59]
  PIN cfg_data[5]
    DIRECTION INPUT ;
    USE SIGNAL ;
    PORT
      LAYER M3 ;
        RECT  5.076 77.722 5.094 77.76 ;
    END
  END cfg_data[5]
  PIN cfg_data[60]
    DIRECTION INPUT ;
    USE SIGNAL ;
    PORT
      LAYER M3 ;
        RECT  17.856 77.722 17.874 77.76 ;
    END
  END cfg_data[60]
  PIN cfg_data[61]
    DIRECTION INPUT ;
    USE SIGNAL ;
    PORT
      LAYER M3 ;
        RECT  18.108 77.722 18.126 77.76 ;
    END
  END cfg_data[61]
  PIN cfg_data[62]
    DIRECTION INPUT ;
    USE SIGNAL ;
    PORT
      LAYER M3 ;
        RECT  18.324 77.722 18.342 77.76 ;
    END
  END cfg_data[62]
  PIN cfg_data[63]
    DIRECTION INPUT ;
    USE SIGNAL ;
    PORT
      LAYER M3 ;
        RECT  18.576 77.722 18.594 77.76 ;
    END
  END cfg_data[63]
  PIN cfg_data[64]
    DIRECTION INPUT ;
    USE SIGNAL ;
    PORT
      LAYER M3 ;
        RECT  18.792 77.722 18.81 77.76 ;
    END
  END cfg_data[64]
  PIN cfg_data[65]
    DIRECTION INPUT ;
    USE SIGNAL ;
    PORT
      LAYER M3 ;
        RECT  19.044 77.722 19.062 77.76 ;
    END
  END cfg_data[65]
  PIN cfg_data[66]
    DIRECTION INPUT ;
    USE SIGNAL ;
    PORT
      LAYER M3 ;
        RECT  19.26 77.722 19.278 77.76 ;
    END
  END cfg_data[66]
  PIN cfg_data[67]
    DIRECTION INPUT ;
    USE SIGNAL ;
    PORT
      LAYER M3 ;
        RECT  19.512 77.722 19.53 77.76 ;
    END
  END cfg_data[67]
  PIN cfg_data[68]
    DIRECTION INPUT ;
    USE SIGNAL ;
    PORT
      LAYER M3 ;
        RECT  19.728 77.722 19.746 77.76 ;
    END
  END cfg_data[68]
  PIN cfg_data[69]
    DIRECTION INPUT ;
    USE SIGNAL ;
    PORT
      LAYER M3 ;
        RECT  19.98 77.722 19.998 77.76 ;
    END
  END cfg_data[69]
  PIN cfg_data[6]
    DIRECTION INPUT ;
    USE SIGNAL ;
    PORT
      LAYER M3 ;
        RECT  5.292 77.722 5.31 77.76 ;
    END
  END cfg_data[6]
  PIN cfg_data[70]
    DIRECTION INPUT ;
    USE SIGNAL ;
    PORT
      LAYER M3 ;
        RECT  20.196 77.722 20.214 77.76 ;
    END
  END cfg_data[70]
  PIN cfg_data[71]
    DIRECTION INPUT ;
    USE SIGNAL ;
    PORT
      LAYER M3 ;
        RECT  20.412 77.722 20.43 77.76 ;
    END
  END cfg_data[71]
  PIN cfg_data[72]
    DIRECTION INPUT ;
    USE SIGNAL ;
    PORT
      LAYER M3 ;
        RECT  20.664 77.722 20.682 77.76 ;
    END
  END cfg_data[72]
  PIN cfg_data[73]
    DIRECTION INPUT ;
    USE SIGNAL ;
    PORT
      LAYER M3 ;
        RECT  20.88 77.722 20.898 77.76 ;
    END
  END cfg_data[73]
  PIN cfg_data[74]
    DIRECTION INPUT ;
    USE SIGNAL ;
    PORT
      LAYER M3 ;
        RECT  21.132 77.722 21.15 77.76 ;
    END
  END cfg_data[74]
  PIN cfg_data[75]
    DIRECTION INPUT ;
    USE SIGNAL ;
    PORT
      LAYER M3 ;
        RECT  21.348 77.722 21.366 77.76 ;
    END
  END cfg_data[75]
  PIN cfg_data[76]
    DIRECTION INPUT ;
    USE SIGNAL ;
    PORT
      LAYER M3 ;
        RECT  21.6 77.722 21.618 77.76 ;
    END
  END cfg_data[76]
  PIN cfg_data[77]
    DIRECTION INPUT ;
    USE SIGNAL ;
    PORT
      LAYER M3 ;
        RECT  21.816 77.722 21.834 77.76 ;
    END
  END cfg_data[77]
  PIN cfg_data[78]
    DIRECTION INPUT ;
    USE SIGNAL ;
    PORT
      LAYER M3 ;
        RECT  22.068 77.722 22.086 77.76 ;
    END
  END cfg_data[78]
  PIN cfg_data[79]
    DIRECTION INPUT ;
    USE SIGNAL ;
    PORT
      LAYER M3 ;
        RECT  22.284 77.722 22.302 77.76 ;
    END
  END cfg_data[79]
  PIN cfg_data[7]
    DIRECTION INPUT ;
    USE SIGNAL ;
    PORT
      LAYER M3 ;
        RECT  5.544 77.722 5.562 77.76 ;
    END
  END cfg_data[7]
  PIN cfg_data[80]
    DIRECTION INPUT ;
    USE SIGNAL ;
    PORT
      LAYER M3 ;
        RECT  22.536 77.722 22.554 77.76 ;
    END
  END cfg_data[80]
  PIN cfg_data[81]
    DIRECTION INPUT ;
    USE SIGNAL ;
    PORT
      LAYER M3 ;
        RECT  22.752 77.722 22.77 77.76 ;
    END
  END cfg_data[81]
  PIN cfg_data[82]
    DIRECTION INPUT ;
    USE SIGNAL ;
    PORT
      LAYER M3 ;
        RECT  23.004 77.722 23.022 77.76 ;
    END
  END cfg_data[82]
  PIN cfg_data[83]
    DIRECTION INPUT ;
    USE SIGNAL ;
    PORT
      LAYER M3 ;
        RECT  23.22 77.722 23.238 77.76 ;
    END
  END cfg_data[83]
  PIN cfg_data[84]
    DIRECTION INPUT ;
    USE SIGNAL ;
    PORT
      LAYER M5 ;
        RECT  23.472 77.676 23.496 77.76 ;
    END
  END cfg_data[84]
  PIN cfg_data[85]
    DIRECTION INPUT ;
    USE SIGNAL ;
    PORT
      LAYER M5 ;
        RECT  23.664 77.676 23.688 77.76 ;
    END
  END cfg_data[85]
  PIN cfg_data[86]
    DIRECTION INPUT ;
    USE SIGNAL ;
    PORT
      LAYER M5 ;
        RECT  23.904 77.676 23.928 77.76 ;
    END
  END cfg_data[86]
  PIN cfg_data[87]
    DIRECTION INPUT ;
    USE SIGNAL ;
    PORT
      LAYER M5 ;
        RECT  24.144 77.676 24.168 77.76 ;
    END
  END cfg_data[87]
  PIN cfg_data[88]
    DIRECTION INPUT ;
    USE SIGNAL ;
    PORT
      LAYER M5 ;
        RECT  24.384 77.676 24.408 77.76 ;
    END
  END cfg_data[88]
  PIN cfg_data[89]
    DIRECTION INPUT ;
    USE SIGNAL ;
    PORT
      LAYER M5 ;
        RECT  24.624 77.676 24.648 77.76 ;
    END
  END cfg_data[89]
  PIN cfg_data[8]
    DIRECTION INPUT ;
    USE SIGNAL ;
    PORT
      LAYER M3 ;
        RECT  5.76 77.722 5.778 77.76 ;
    END
  END cfg_data[8]
  PIN cfg_data[90]
    DIRECTION INPUT ;
    USE SIGNAL ;
    PORT
      LAYER M5 ;
        RECT  24.864 77.676 24.888 77.76 ;
    END
  END cfg_data[90]
  PIN cfg_data[91]
    DIRECTION INPUT ;
    USE SIGNAL ;
    PORT
      LAYER M5 ;
        RECT  25.104 77.676 25.128 77.76 ;
    END
  END cfg_data[91]
  PIN cfg_data[92]
    DIRECTION INPUT ;
    USE SIGNAL ;
    PORT
      LAYER M5 ;
        RECT  25.296 77.676 25.32 77.76 ;
    END
  END cfg_data[92]
  PIN cfg_data[93]
    DIRECTION INPUT ;
    USE SIGNAL ;
    PORT
      LAYER M5 ;
        RECT  25.536 77.676 25.56 77.76 ;
    END
  END cfg_data[93]
  PIN cfg_data[94]
    DIRECTION INPUT ;
    USE SIGNAL ;
    PORT
      LAYER M5 ;
        RECT  25.776 77.676 25.8 77.76 ;
    END
  END cfg_data[94]
  PIN cfg_data[95]
    DIRECTION INPUT ;
    USE SIGNAL ;
    PORT
      LAYER M5 ;
        RECT  26.016 77.676 26.04 77.76 ;
    END
  END cfg_data[95]
  PIN cfg_data[96]
    DIRECTION INPUT ;
    USE SIGNAL ;
    PORT
      LAYER M5 ;
        RECT  26.256 77.676 26.28 77.76 ;
    END
  END cfg_data[96]
  PIN cfg_data[97]
    DIRECTION INPUT ;
    USE SIGNAL ;
    PORT
      LAYER M5 ;
        RECT  26.496 77.676 26.52 77.76 ;
    END
  END cfg_data[97]
  PIN cfg_data[98]
    DIRECTION INPUT ;
    USE SIGNAL ;
    PORT
      LAYER M5 ;
        RECT  26.688 77.676 26.712 77.76 ;
    END
  END cfg_data[98]
  PIN cfg_data[99]
    DIRECTION INPUT ;
    USE SIGNAL ;
    PORT
      LAYER M5 ;
        RECT  26.928 77.676 26.952 77.76 ;
    END
  END cfg_data[99]
  PIN cfg_data[9]
    DIRECTION INPUT ;
    USE SIGNAL ;
    PORT
      LAYER M3 ;
        RECT  6.012 77.722 6.03 77.76 ;
    END
  END cfg_data[9]
  PIN cfg_target[0]
    DIRECTION INPUT ;
    USE SIGNAL ;
    PORT
      LAYER M3 ;
        RECT  63.504 77.722 63.522 77.76 ;
    END
  END cfg_target[0]
  PIN cfg_target[1]
    DIRECTION INPUT ;
    USE SIGNAL ;
    PORT
      LAYER M3 ;
        RECT  63.72 77.722 63.738 77.76 ;
    END
  END cfg_target[1]
  PIN cfg_target[2]
    DIRECTION INPUT ;
    USE SIGNAL ;
    PORT
      LAYER M3 ;
        RECT  63.972 77.722 63.99 77.76 ;
    END
  END cfg_target[2]
  PIN cfg_target[3]
    DIRECTION INPUT ;
    USE SIGNAL ;
    PORT
      LAYER M3 ;
        RECT  64.188 77.722 64.206 77.76 ;
    END
  END cfg_target[3]
  PIN cfg_target[4]
    DIRECTION INPUT ;
    USE SIGNAL ;
    PORT
      LAYER M3 ;
        RECT  64.44 77.722 64.458 77.76 ;
    END
  END cfg_target[4]
  PIN cfg_target[5]
    DIRECTION INPUT ;
    USE SIGNAL ;
    PORT
      LAYER M3 ;
        RECT  64.656 77.722 64.674 77.76 ;
    END
  END cfg_target[5]
  PIN cfg_target[6]
    DIRECTION INPUT ;
    USE SIGNAL ;
    PORT
      LAYER M3 ;
        RECT  64.908 77.722 64.926 77.76 ;
    END
  END cfg_target[6]
  PIN cfg_target[7]
    DIRECTION INPUT ;
    USE SIGNAL ;
    PORT
      LAYER M3 ;
        RECT  65.124 77.722 65.142 77.76 ;
    END
  END cfg_target[7]
  PIN cfg_v
    DIRECTION INPUT ;
    USE SIGNAL ;
    PORT
      LAYER M3 ;
        RECT  65.376 77.722 65.394 77.76 ;
    END
  END cfg_v
  PIN clk
    DIRECTION INPUT ;
    USE SIGNAL ;
    PORT
      LAYER M3 ;
        RECT  65.592 77.722 65.61 77.76 ;
    END
  END clk
  PIN configured
    DIRECTION OUTPUT ;
    USE SIGNAL ;
    PORT
      LAYER M3 ;
        RECT  65.808 77.722 65.826 77.76 ;
    END
  END configured
  PIN desc_base[0]
    DIRECTION INPUT ;
    USE SIGNAL ;
    PORT
      LAYER M3 ;
        RECT  66.06 77.722 66.078 77.76 ;
    END
  END desc_base[0]
  PIN desc_base[10]
    DIRECTION INPUT ;
    USE SIGNAL ;
    PORT
      LAYER M5 ;
        RECT  68.4 77.676 68.424 77.76 ;
    END
  END desc_base[10]
  PIN desc_base[11]
    DIRECTION INPUT ;
    USE SIGNAL ;
    PORT
      LAYER M5 ;
        RECT  68.592 77.676 68.616 77.76 ;
    END
  END desc_base[11]
  PIN desc_base[1]
    DIRECTION INPUT ;
    USE SIGNAL ;
    PORT
      LAYER M3 ;
        RECT  66.276 77.722 66.294 77.76 ;
    END
  END desc_base[1]
  PIN desc_base[2]
    DIRECTION INPUT ;
    USE SIGNAL ;
    PORT
      LAYER M3 ;
        RECT  66.528 77.722 66.546 77.76 ;
    END
  END desc_base[2]
  PIN desc_base[3]
    DIRECTION INPUT ;
    USE SIGNAL ;
    PORT
      LAYER M3 ;
        RECT  66.744 77.722 66.762 77.76 ;
    END
  END desc_base[3]
  PIN desc_base[4]
    DIRECTION INPUT ;
    USE SIGNAL ;
    PORT
      LAYER M3 ;
        RECT  66.996 77.722 67.014 77.76 ;
    END
  END desc_base[4]
  PIN desc_base[5]
    DIRECTION INPUT ;
    USE SIGNAL ;
    PORT
      LAYER M3 ;
        RECT  67.212 77.722 67.23 77.76 ;
    END
  END desc_base[5]
  PIN desc_base[6]
    DIRECTION INPUT ;
    USE SIGNAL ;
    PORT
      LAYER M3 ;
        RECT  67.464 77.722 67.482 77.76 ;
    END
  END desc_base[6]
  PIN desc_base[7]
    DIRECTION INPUT ;
    USE SIGNAL ;
    PORT
      LAYER M3 ;
        RECT  67.68 77.722 67.698 77.76 ;
    END
  END desc_base[7]
  PIN desc_base[8]
    DIRECTION INPUT ;
    USE SIGNAL ;
    PORT
      LAYER M3 ;
        RECT  67.932 77.722 67.95 77.76 ;
    END
  END desc_base[8]
  PIN desc_base[9]
    DIRECTION INPUT ;
    USE SIGNAL ;
    PORT
      LAYER M5 ;
        RECT  68.16 77.676 68.184 77.76 ;
    END
  END desc_base[9]
  PIN desc_limit[0]
    DIRECTION INPUT ;
    USE SIGNAL ;
    PORT
      LAYER M5 ;
        RECT  68.832 77.676 68.856 77.76 ;
    END
  END desc_limit[0]
  PIN desc_limit[10]
    DIRECTION INPUT ;
    USE SIGNAL ;
    PORT
      LAYER M5 ;
        RECT  71.184 77.676 71.208 77.76 ;
    END
  END desc_limit[10]
  PIN desc_limit[11]
    DIRECTION INPUT ;
    USE SIGNAL ;
    PORT
      LAYER M5 ;
        RECT  71.424 77.676 71.448 77.76 ;
    END
  END desc_limit[11]
  PIN desc_limit[12]
    DIRECTION INPUT ;
    USE SIGNAL ;
    PORT
      LAYER M5 ;
        RECT  71.664 77.676 71.688 77.76 ;
    END
  END desc_limit[12]
  PIN desc_limit[1]
    DIRECTION INPUT ;
    USE SIGNAL ;
    PORT
      LAYER M5 ;
        RECT  69.072 77.676 69.096 77.76 ;
    END
  END desc_limit[1]
  PIN desc_limit[2]
    DIRECTION INPUT ;
    USE SIGNAL ;
    PORT
      LAYER M5 ;
        RECT  69.312 77.676 69.336 77.76 ;
    END
  END desc_limit[2]
  PIN desc_limit[3]
    DIRECTION INPUT ;
    USE SIGNAL ;
    PORT
      LAYER M5 ;
        RECT  69.552 77.676 69.576 77.76 ;
    END
  END desc_limit[3]
  PIN desc_limit[4]
    DIRECTION INPUT ;
    USE SIGNAL ;
    PORT
      LAYER M5 ;
        RECT  69.792 77.676 69.816 77.76 ;
    END
  END desc_limit[4]
  PIN desc_limit[5]
    DIRECTION INPUT ;
    USE SIGNAL ;
    PORT
      LAYER M5 ;
        RECT  70.032 77.676 70.056 77.76 ;
    END
  END desc_limit[5]
  PIN desc_limit[6]
    DIRECTION INPUT ;
    USE SIGNAL ;
    PORT
      LAYER M5 ;
        RECT  70.224 77.676 70.248 77.76 ;
    END
  END desc_limit[6]
  PIN desc_limit[7]
    DIRECTION INPUT ;
    USE SIGNAL ;
    PORT
      LAYER M5 ;
        RECT  70.464 77.676 70.488 77.76 ;
    END
  END desc_limit[7]
  PIN desc_limit[8]
    DIRECTION INPUT ;
    USE SIGNAL ;
    PORT
      LAYER M5 ;
        RECT  70.704 77.676 70.728 77.76 ;
    END
  END desc_limit[8]
  PIN desc_limit[9]
    DIRECTION INPUT ;
    USE SIGNAL ;
    PORT
      LAYER M5 ;
        RECT  70.944 77.676 70.968 77.76 ;
    END
  END desc_limit[9]
  PIN desc_loops[0]
    DIRECTION INPUT ;
    USE SIGNAL ;
    PORT
      LAYER M5 ;
        RECT  71.856 77.676 71.88 77.76 ;
    END
  END desc_loops[0]
  PIN desc_loops[10]
    DIRECTION INPUT ;
    USE SIGNAL ;
    PORT
      LAYER M5 ;
        RECT  74.208 77.676 74.232 77.76 ;
    END
  END desc_loops[10]
  PIN desc_loops[11]
    DIRECTION INPUT ;
    USE SIGNAL ;
    PORT
      LAYER M5 ;
        RECT  74.448 77.676 74.472 77.76 ;
    END
  END desc_loops[11]
  PIN desc_loops[12]
    DIRECTION INPUT ;
    USE SIGNAL ;
    PORT
      LAYER M5 ;
        RECT  74.688 77.676 74.712 77.76 ;
    END
  END desc_loops[12]
  PIN desc_loops[13]
    DIRECTION INPUT ;
    USE SIGNAL ;
    PORT
      LAYER M5 ;
        RECT  74.88 77.676 74.904 77.76 ;
    END
  END desc_loops[13]
  PIN desc_loops[14]
    DIRECTION INPUT ;
    USE SIGNAL ;
    PORT
      LAYER M5 ;
        RECT  75.12 77.676 75.144 77.76 ;
    END
  END desc_loops[14]
  PIN desc_loops[15]
    DIRECTION INPUT ;
    USE SIGNAL ;
    PORT
      LAYER M5 ;
        RECT  75.36 77.676 75.384 77.76 ;
    END
  END desc_loops[15]
  PIN desc_loops[1]
    DIRECTION INPUT ;
    USE SIGNAL ;
    PORT
      LAYER M5 ;
        RECT  72.096 77.676 72.12 77.76 ;
    END
  END desc_loops[1]
  PIN desc_loops[2]
    DIRECTION INPUT ;
    USE SIGNAL ;
    PORT
      LAYER M5 ;
        RECT  72.336 77.676 72.36 77.76 ;
    END
  END desc_loops[2]
  PIN desc_loops[3]
    DIRECTION INPUT ;
    USE SIGNAL ;
    PORT
      LAYER M5 ;
        RECT  72.576 77.676 72.6 77.76 ;
    END
  END desc_loops[3]
  PIN desc_loops[4]
    DIRECTION INPUT ;
    USE SIGNAL ;
    PORT
      LAYER M5 ;
        RECT  72.816 77.676 72.84 77.76 ;
    END
  END desc_loops[4]
  PIN desc_loops[5]
    DIRECTION INPUT ;
    USE SIGNAL ;
    PORT
      LAYER M5 ;
        RECT  73.056 77.676 73.08 77.76 ;
    END
  END desc_loops[5]
  PIN desc_loops[6]
    DIRECTION INPUT ;
    USE SIGNAL ;
    PORT
      LAYER M5 ;
        RECT  73.248 77.676 73.272 77.76 ;
    END
  END desc_loops[6]
  PIN desc_loops[7]
    DIRECTION INPUT ;
    USE SIGNAL ;
    PORT
      LAYER M5 ;
        RECT  73.488 77.676 73.512 77.76 ;
    END
  END desc_loops[7]
  PIN desc_loops[8]
    DIRECTION INPUT ;
    USE SIGNAL ;
    PORT
      LAYER M5 ;
        RECT  73.728 77.676 73.752 77.76 ;
    END
  END desc_loops[8]
  PIN desc_loops[9]
    DIRECTION INPUT ;
    USE SIGNAL ;
    PORT
      LAYER M5 ;
        RECT  73.968 77.676 73.992 77.76 ;
    END
  END desc_loops[9]
  PIN desc_v
    DIRECTION INPUT ;
    USE SIGNAL ;
    PORT
      LAYER M3 ;
        RECT  75.6 77.722 75.618 77.76 ;
    END
  END desc_v
  PIN fault
    DIRECTION OUTPUT ;
    USE SIGNAL ;
    PORT
      LAYER M3 ;
        RECT  75.816 77.722 75.834 77.76 ;
    END
  END fault
  PIN fault_cause[0]
    DIRECTION OUTPUT ;
    USE SIGNAL ;
    PORT
      LAYER M3 ;
        RECT  76.068 77.722 76.086 77.76 ;
    END
  END fault_cause[0]
  PIN fault_cause[10]
    DIRECTION OUTPUT ;
    USE SIGNAL ;
    PORT
      LAYER M3 ;
        RECT  78.408 77.722 78.426 77.76 ;
    END
  END fault_cause[10]
  PIN fault_cause[11]
    DIRECTION OUTPUT ;
    USE SIGNAL ;
    PORT
      LAYER M3 ;
        RECT  78.624 77.722 78.642 77.76 ;
    END
  END fault_cause[11]
  PIN fault_cause[12]
    DIRECTION OUTPUT ;
    USE SIGNAL ;
    PORT
      LAYER M3 ;
        RECT  78.876 77.722 78.894 77.76 ;
    END
  END fault_cause[12]
  PIN fault_cause[13]
    DIRECTION OUTPUT ;
    USE SIGNAL ;
    PORT
      LAYER M3 ;
        RECT  79.092 77.722 79.11 77.76 ;
    END
  END fault_cause[13]
  PIN fault_cause[14]
    DIRECTION OUTPUT ;
    USE SIGNAL ;
    PORT
      LAYER M3 ;
        RECT  79.308 77.722 79.326 77.76 ;
    END
  END fault_cause[14]
  PIN fault_cause[15]
    DIRECTION OUTPUT ;
    USE SIGNAL ;
    PORT
      LAYER M3 ;
        RECT  79.56 77.722 79.578 77.76 ;
    END
  END fault_cause[15]
  PIN fault_cause[1]
    DIRECTION OUTPUT ;
    USE SIGNAL ;
    PORT
      LAYER M3 ;
        RECT  76.284 77.722 76.302 77.76 ;
    END
  END fault_cause[1]
  PIN fault_cause[2]
    DIRECTION OUTPUT ;
    USE SIGNAL ;
    PORT
      LAYER M3 ;
        RECT  76.536 77.722 76.554 77.76 ;
    END
  END fault_cause[2]
  PIN fault_cause[3]
    DIRECTION OUTPUT ;
    USE SIGNAL ;
    PORT
      LAYER M3 ;
        RECT  76.752 77.722 76.77 77.76 ;
    END
  END fault_cause[3]
  PIN fault_cause[4]
    DIRECTION OUTPUT ;
    USE SIGNAL ;
    PORT
      LAYER M3 ;
        RECT  77.004 77.722 77.022 77.76 ;
    END
  END fault_cause[4]
  PIN fault_cause[5]
    DIRECTION OUTPUT ;
    USE SIGNAL ;
    PORT
      LAYER M3 ;
        RECT  77.22 77.722 77.238 77.76 ;
    END
  END fault_cause[5]
  PIN fault_cause[6]
    DIRECTION OUTPUT ;
    USE SIGNAL ;
    PORT
      LAYER M3 ;
        RECT  77.472 77.722 77.49 77.76 ;
    END
  END fault_cause[6]
  PIN fault_cause[7]
    DIRECTION OUTPUT ;
    USE SIGNAL ;
    PORT
      LAYER M3 ;
        RECT  77.688 77.722 77.706 77.76 ;
    END
  END fault_cause[7]
  PIN fault_cause[8]
    DIRECTION OUTPUT ;
    USE SIGNAL ;
    PORT
      LAYER M3 ;
        RECT  77.94 77.722 77.958 77.76 ;
    END
  END fault_cause[8]
  PIN fault_cause[9]
    DIRECTION OUTPUT ;
    USE SIGNAL ;
    PORT
      LAYER M3 ;
        RECT  78.156 77.722 78.174 77.76 ;
    END
  END fault_cause[9]
  PIN init_busy
    DIRECTION OUTPUT ;
    USE SIGNAL ;
    PORT
      LAYER M3 ;
        RECT  79.776 77.722 79.794 77.76 ;
    END
  END init_busy
  PIN issuer_busy
    DIRECTION INPUT ;
    USE SIGNAL ;
    PORT
      LAYER M3 ;
        RECT  1.692 0 1.71 0.038 ;
    END
  END issuer_busy
  PIN issuer_cfg[0]
    DIRECTION OUTPUT ;
    USE SIGNAL ;
    PORT
      LAYER M3 ;
        RECT  3.132 0 3.15 0.038 ;
    END
  END issuer_cfg[0]
  PIN issuer_cfg[10]
    DIRECTION OUTPUT ;
    USE SIGNAL ;
    PORT
      LAYER M3 ;
        RECT  17.424 0 17.442 0.038 ;
    END
  END issuer_cfg[10]
  PIN issuer_cfg[11]
    DIRECTION OUTPUT ;
    USE SIGNAL ;
    PORT
      LAYER M3 ;
        RECT  18.864 0 18.882 0.038 ;
    END
  END issuer_cfg[11]
  PIN issuer_cfg[12]
    DIRECTION OUTPUT ;
    USE SIGNAL ;
    PORT
      LAYER M3 ;
        RECT  20.304 0 20.322 0.038 ;
    END
  END issuer_cfg[12]
  PIN issuer_cfg[13]
    DIRECTION OUTPUT ;
    USE SIGNAL ;
    PORT
      LAYER M3 ;
        RECT  21.744 0 21.762 0.038 ;
    END
  END issuer_cfg[13]
  PIN issuer_cfg[14]
    DIRECTION OUTPUT ;
    USE SIGNAL ;
    PORT
      LAYER M3 ;
        RECT  23.148 0 23.166 0.038 ;
    END
  END issuer_cfg[14]
  PIN issuer_cfg[15]
    DIRECTION OUTPUT ;
    USE SIGNAL ;
    PORT
      LAYER M3 ;
        RECT  24.588 0 24.606 0.038 ;
    END
  END issuer_cfg[15]
  PIN issuer_cfg[16]
    DIRECTION OUTPUT ;
    USE SIGNAL ;
    PORT
      LAYER M3 ;
        RECT  26.028 0 26.046 0.038 ;
    END
  END issuer_cfg[16]
  PIN issuer_cfg[17]
    DIRECTION OUTPUT ;
    USE SIGNAL ;
    PORT
      LAYER M3 ;
        RECT  27.432 0 27.45 0.038 ;
    END
  END issuer_cfg[17]
  PIN issuer_cfg[18]
    DIRECTION OUTPUT ;
    USE SIGNAL ;
    PORT
      LAYER M3 ;
        RECT  28.872 0 28.89 0.038 ;
    END
  END issuer_cfg[18]
  PIN issuer_cfg[19]
    DIRECTION OUTPUT ;
    USE SIGNAL ;
    PORT
      LAYER M3 ;
        RECT  30.312 0 30.33 0.038 ;
    END
  END issuer_cfg[19]
  PIN issuer_cfg[1]
    DIRECTION OUTPUT ;
    USE SIGNAL ;
    PORT
      LAYER M3 ;
        RECT  4.572 0 4.59 0.038 ;
    END
  END issuer_cfg[1]
  PIN issuer_cfg[20]
    DIRECTION OUTPUT ;
    USE SIGNAL ;
    PORT
      LAYER M3 ;
        RECT  31.752 0 31.77 0.038 ;
    END
  END issuer_cfg[20]
  PIN issuer_cfg[21]
    DIRECTION OUTPUT ;
    USE SIGNAL ;
    PORT
      LAYER M3 ;
        RECT  33.156 0 33.174 0.038 ;
    END
  END issuer_cfg[21]
  PIN issuer_cfg[22]
    DIRECTION OUTPUT ;
    USE SIGNAL ;
    PORT
      LAYER M3 ;
        RECT  34.596 0 34.614 0.038 ;
    END
  END issuer_cfg[22]
  PIN issuer_cfg[23]
    DIRECTION OUTPUT ;
    USE SIGNAL ;
    PORT
      LAYER M3 ;
        RECT  36.036 0 36.054 0.038 ;
    END
  END issuer_cfg[23]
  PIN issuer_cfg[24]
    DIRECTION OUTPUT ;
    USE SIGNAL ;
    PORT
      LAYER M3 ;
        RECT  37.44 0 37.458 0.038 ;
    END
  END issuer_cfg[24]
  PIN issuer_cfg[25]
    DIRECTION OUTPUT ;
    USE SIGNAL ;
    PORT
      LAYER M3 ;
        RECT  38.88 0 38.898 0.038 ;
    END
  END issuer_cfg[25]
  PIN issuer_cfg[26]
    DIRECTION OUTPUT ;
    USE SIGNAL ;
    PORT
      LAYER M3 ;
        RECT  40.32 0 40.338 0.038 ;
    END
  END issuer_cfg[26]
  PIN issuer_cfg[27]
    DIRECTION OUTPUT ;
    USE SIGNAL ;
    PORT
      LAYER M3 ;
        RECT  41.76 0 41.778 0.038 ;
    END
  END issuer_cfg[27]
  PIN issuer_cfg[28]
    DIRECTION OUTPUT ;
    USE SIGNAL ;
    PORT
      LAYER M3 ;
        RECT  43.164 0 43.182 0.038 ;
    END
  END issuer_cfg[28]
  PIN issuer_cfg[29]
    DIRECTION OUTPUT ;
    USE SIGNAL ;
    PORT
      LAYER M3 ;
        RECT  44.604 0 44.622 0.038 ;
    END
  END issuer_cfg[29]
  PIN issuer_cfg[2]
    DIRECTION OUTPUT ;
    USE SIGNAL ;
    PORT
      LAYER M3 ;
        RECT  6.012 0 6.03 0.038 ;
    END
  END issuer_cfg[2]
  PIN issuer_cfg[30]
    DIRECTION OUTPUT ;
    USE SIGNAL ;
    PORT
      LAYER M3 ;
        RECT  46.044 0 46.062 0.038 ;
    END
  END issuer_cfg[30]
  PIN issuer_cfg[31]
    DIRECTION OUTPUT ;
    USE SIGNAL ;
    PORT
      LAYER M5 ;
        RECT  47.472 0 47.496 0.084 ;
    END
  END issuer_cfg[31]
  PIN issuer_cfg[32]
    DIRECTION OUTPUT ;
    USE SIGNAL ;
    PORT
      LAYER M5 ;
        RECT  48.912 0 48.936 0.084 ;
    END
  END issuer_cfg[32]
  PIN issuer_cfg[33]
    DIRECTION OUTPUT ;
    USE SIGNAL ;
    PORT
      LAYER M5 ;
        RECT  50.304 0 50.328 0.084 ;
    END
  END issuer_cfg[33]
  PIN issuer_cfg[34]
    DIRECTION OUTPUT ;
    USE SIGNAL ;
    PORT
      LAYER M5 ;
        RECT  51.744 0 51.768 0.084 ;
    END
  END issuer_cfg[34]
  PIN issuer_cfg[35]
    DIRECTION OUTPUT ;
    USE SIGNAL ;
    PORT
      LAYER M5 ;
        RECT  53.184 0 53.208 0.084 ;
    END
  END issuer_cfg[35]
  PIN issuer_cfg[36]
    DIRECTION OUTPUT ;
    USE SIGNAL ;
    PORT
      LAYER M5 ;
        RECT  54.624 0 54.648 0.084 ;
    END
  END issuer_cfg[36]
  PIN issuer_cfg[3]
    DIRECTION OUTPUT ;
    USE SIGNAL ;
    PORT
      LAYER M3 ;
        RECT  7.416 0 7.434 0.038 ;
    END
  END issuer_cfg[3]
  PIN issuer_cfg[4]
    DIRECTION OUTPUT ;
    USE SIGNAL ;
    PORT
      LAYER M3 ;
        RECT  8.856 0 8.874 0.038 ;
    END
  END issuer_cfg[4]
  PIN issuer_cfg[5]
    DIRECTION OUTPUT ;
    USE SIGNAL ;
    PORT
      LAYER M3 ;
        RECT  10.296 0 10.314 0.038 ;
    END
  END issuer_cfg[5]
  PIN issuer_cfg[6]
    DIRECTION OUTPUT ;
    USE SIGNAL ;
    PORT
      LAYER M3 ;
        RECT  11.7 0 11.718 0.038 ;
    END
  END issuer_cfg[6]
  PIN issuer_cfg[7]
    DIRECTION OUTPUT ;
    USE SIGNAL ;
    PORT
      LAYER M3 ;
        RECT  13.14 0 13.158 0.038 ;
    END
  END issuer_cfg[7]
  PIN issuer_cfg[8]
    DIRECTION OUTPUT ;
    USE SIGNAL ;
    PORT
      LAYER M3 ;
        RECT  14.58 0 14.598 0.038 ;
    END
  END issuer_cfg[8]
  PIN issuer_cfg[9]
    DIRECTION OUTPUT ;
    USE SIGNAL ;
    PORT
      LAYER M3 ;
        RECT  16.02 0 16.038 0.038 ;
    END
  END issuer_cfg[9]
  PIN issuer_fault
    DIRECTION INPUT ;
    USE SIGNAL ;
    PORT
      LAYER M5 ;
        RECT  56.064 0 56.088 0.084 ;
    END
  END issuer_fault
  PIN issuer_start
    DIRECTION OUTPUT ;
    USE SIGNAL ;
    PORT
      LAYER M5 ;
        RECT  57.456 0 57.48 0.084 ;
    END
  END issuer_start
  PIN issuer_start_pc[0]
    DIRECTION OUTPUT ;
    USE SIGNAL ;
    PORT
      LAYER M5 ;
        RECT  58.896 0 58.92 0.084 ;
    END
  END issuer_start_pc[0]
  PIN issuer_start_pc[1]
    DIRECTION OUTPUT ;
    USE SIGNAL ;
    PORT
      LAYER M5 ;
        RECT  60.336 0 60.36 0.084 ;
    END
  END issuer_start_pc[1]
  PIN issuer_start_pc[2]
    DIRECTION OUTPUT ;
    USE SIGNAL ;
    PORT
      LAYER M5 ;
        RECT  61.776 0 61.8 0.084 ;
    END
  END issuer_start_pc[2]
  PIN issuer_start_pc[3]
    DIRECTION OUTPUT ;
    USE SIGNAL ;
    PORT
      LAYER M5 ;
        RECT  63.216 0 63.24 0.084 ;
    END
  END issuer_start_pc[3]
  PIN issuer_start_pc[4]
    DIRECTION OUTPUT ;
    USE SIGNAL ;
    PORT
      LAYER M5 ;
        RECT  64.608 0 64.632 0.084 ;
    END
  END issuer_start_pc[4]
  PIN issuer_start_pc[5]
    DIRECTION OUTPUT ;
    USE SIGNAL ;
    PORT
      LAYER M5 ;
        RECT  66.048 0 66.072 0.084 ;
    END
  END issuer_start_pc[5]
  PIN issuer_start_pc[6]
    DIRECTION OUTPUT ;
    USE SIGNAL ;
    PORT
      LAYER M5 ;
        RECT  67.488 0 67.512 0.084 ;
    END
  END issuer_start_pc[6]
  PIN issuer_uop_pc[0]
    DIRECTION INPUT ;
    USE SIGNAL ;
    PORT
      LAYER M5 ;
        RECT  68.928 0 68.952 0.084 ;
    END
  END issuer_uop_pc[0]
  PIN issuer_uop_pc[1]
    DIRECTION INPUT ;
    USE SIGNAL ;
    PORT
      LAYER M5 ;
        RECT  70.32 0 70.344 0.084 ;
    END
  END issuer_uop_pc[1]
  PIN issuer_uop_pc[2]
    DIRECTION INPUT ;
    USE SIGNAL ;
    PORT
      LAYER M5 ;
        RECT  71.76 0 71.784 0.084 ;
    END
  END issuer_uop_pc[2]
  PIN issuer_uop_pc[3]
    DIRECTION INPUT ;
    USE SIGNAL ;
    PORT
      LAYER M5 ;
        RECT  73.2 0 73.224 0.084 ;
    END
  END issuer_uop_pc[3]
  PIN issuer_uop_pc[4]
    DIRECTION INPUT ;
    USE SIGNAL ;
    PORT
      LAYER M5 ;
        RECT  74.64 0 74.664 0.084 ;
    END
  END issuer_uop_pc[4]
  PIN issuer_uop_pc[5]
    DIRECTION INPUT ;
    USE SIGNAL ;
    PORT
      LAYER M5 ;
        RECT  76.08 0 76.104 0.084 ;
    END
  END issuer_uop_pc[5]
  PIN issuer_uop_pc[6]
    DIRECTION INPUT ;
    USE SIGNAL ;
    PORT
      LAYER M5 ;
        RECT  77.472 0 77.496 0.084 ;
    END
  END issuer_uop_pc[6]
  PIN issuer_uop_v
    DIRECTION INPUT ;
    USE SIGNAL ;
    PORT
      LAYER M5 ;
        RECT  78.912 0 78.936 0.084 ;
    END
  END issuer_uop_v
  PIN launch_v
    DIRECTION INPUT ;
    USE SIGNAL ;
    PORT
      LAYER M3 ;
        RECT  80.028 77.722 80.046 77.76 ;
    END
  END launch_v
  PIN link_abort[0]
    DIRECTION INPUT ;
    USE SIGNAL ;
    PORT
      LAYER M4 ;
        RECT  0 8.544 0.084 8.568 ;
    END
  END link_abort[0]
  PIN link_abort[1]
    DIRECTION INPUT ;
    USE SIGNAL ;
    PORT
      LAYER M4 ;
        RECT  0 23.712 0.084 23.736 ;
    END
  END link_abort[1]
  PIN program_active
    DIRECTION INPUT ;
    USE SIGNAL ;
    PORT
      LAYER M5 ;
        RECT  80.352 0 80.376 0.084 ;
    END
  END program_active
  PIN program_fault
    DIRECTION OUTPUT ;
    USE SIGNAL ;
    PORT
      LAYER M3 ;
        RECT  80.244 77.722 80.262 77.76 ;
    END
  END program_fault
  PIN protocol_fault
    DIRECTION INPUT ;
    USE SIGNAL ;
    PORT
      LAYER M4 ;
        RECT  81.996 18.768 82.08 18.792 ;
    END
  END protocol_fault
  PIN qid[0]
    DIRECTION INPUT ;
    USE SIGNAL ;
    PORT
      LAYER M3 ;
        RECT  80.496 77.722 80.514 77.76 ;
    END
  END qid[0]
  PIN qid[1]
    DIRECTION INPUT ;
    USE SIGNAL ;
    PORT
      LAYER M3 ;
        RECT  80.712 77.722 80.73 77.76 ;
    END
  END qid[1]
  PIN reduce_fault
    DIRECTION INPUT ;
    USE SIGNAL ;
    PORT
      LAYER M4 ;
        RECT  0 38.88 0.084 38.904 ;
    END
  END reduce_fault
  PIN ring_fault
    DIRECTION INPUT ;
    USE SIGNAL ;
    PORT
      LAYER M4 ;
        RECT  0 54 0.084 54.024 ;
    END
  END ring_fault
  PIN rst_n
    DIRECTION INPUT ;
    USE SIGNAL ;
    PORT
      LAYER M3 ;
        RECT  80.964 77.722 80.982 77.76 ;
    END
  END rst_n
  PIN select_fault[0]
    DIRECTION INPUT ;
    USE SIGNAL ;
    PORT
      LAYER M4 ;
        RECT  81.996 20.304 82.08 20.328 ;
    END
  END select_fault[0]
  PIN select_fault[10]
    DIRECTION INPUT ;
    USE SIGNAL ;
    PORT
      LAYER M4 ;
        RECT  81.996 35.76 82.08 35.784 ;
    END
  END select_fault[10]
  PIN select_fault[11]
    DIRECTION INPUT ;
    USE SIGNAL ;
    PORT
      LAYER M4 ;
        RECT  81.996 37.344 82.08 37.368 ;
    END
  END select_fault[11]
  PIN select_fault[12]
    DIRECTION INPUT ;
    USE SIGNAL ;
    PORT
      LAYER M4 ;
        RECT  81.996 38.88 82.08 38.904 ;
    END
  END select_fault[12]
  PIN select_fault[13]
    DIRECTION INPUT ;
    USE SIGNAL ;
    PORT
      LAYER M4 ;
        RECT  81.996 40.416 82.08 40.44 ;
    END
  END select_fault[13]
  PIN select_fault[14]
    DIRECTION INPUT ;
    USE SIGNAL ;
    PORT
      LAYER M4 ;
        RECT  81.996 41.952 82.08 41.976 ;
    END
  END select_fault[14]
  PIN select_fault[15]
    DIRECTION INPUT ;
    USE SIGNAL ;
    PORT
      LAYER M4 ;
        RECT  81.996 43.488 82.08 43.512 ;
    END
  END select_fault[15]
  PIN select_fault[16]
    DIRECTION INPUT ;
    USE SIGNAL ;
    PORT
      LAYER M4 ;
        RECT  81.996 45.072 82.08 45.096 ;
    END
  END select_fault[16]
  PIN select_fault[17]
    DIRECTION INPUT ;
    USE SIGNAL ;
    PORT
      LAYER M4 ;
        RECT  81.996 46.608 82.08 46.632 ;
    END
  END select_fault[17]
  PIN select_fault[1]
    DIRECTION INPUT ;
    USE SIGNAL ;
    PORT
      LAYER M4 ;
        RECT  81.996 21.84 82.08 21.864 ;
    END
  END select_fault[1]
  PIN select_fault[2]
    DIRECTION INPUT ;
    USE SIGNAL ;
    PORT
      LAYER M4 ;
        RECT  81.996 23.424 82.08 23.448 ;
    END
  END select_fault[2]
  PIN select_fault[3]
    DIRECTION INPUT ;
    USE SIGNAL ;
    PORT
      LAYER M4 ;
        RECT  81.996 24.96 82.08 24.984 ;
    END
  END select_fault[3]
  PIN select_fault[4]
    DIRECTION INPUT ;
    USE SIGNAL ;
    PORT
      LAYER M4 ;
        RECT  81.996 26.496 82.08 26.52 ;
    END
  END select_fault[4]
  PIN select_fault[5]
    DIRECTION INPUT ;
    USE SIGNAL ;
    PORT
      LAYER M4 ;
        RECT  81.996 28.032 82.08 28.056 ;
    END
  END select_fault[5]
  PIN select_fault[6]
    DIRECTION INPUT ;
    USE SIGNAL ;
    PORT
      LAYER M4 ;
        RECT  81.996 29.568 82.08 29.592 ;
    END
  END select_fault[6]
  PIN select_fault[7]
    DIRECTION INPUT ;
    USE SIGNAL ;
    PORT
      LAYER M4 ;
        RECT  81.996 31.152 82.08 31.176 ;
    END
  END select_fault[7]
  PIN select_fault[8]
    DIRECTION INPUT ;
    USE SIGNAL ;
    PORT
      LAYER M4 ;
        RECT  81.996 32.688 82.08 32.712 ;
    END
  END select_fault[8]
  PIN select_fault[9]
    DIRECTION INPUT ;
    USE SIGNAL ;
    PORT
      LAYER M4 ;
        RECT  81.996 34.224 82.08 34.248 ;
    END
  END select_fault[9]
  PIN tkm_fault
    DIRECTION INPUT ;
    USE SIGNAL ;
    PORT
      LAYER M4 ;
        RECT  81.996 48.144 82.08 48.168 ;
    END
  END tkm_fault
  PIN unavailable_fault[0]
    DIRECTION INPUT ;
    USE SIGNAL ;
    PORT
      LAYER M4 ;
        RECT  81.996 49.68 82.08 49.704 ;
    END
  END unavailable_fault[0]
  PIN unavailable_fault[10]
    DIRECTION INPUT ;
    USE SIGNAL ;
    PORT
      LAYER M4 ;
        RECT  81.996 65.136 82.08 65.16 ;
    END
  END unavailable_fault[10]
  PIN unavailable_fault[11]
    DIRECTION INPUT ;
    USE SIGNAL ;
    PORT
      LAYER M4 ;
        RECT  81.996 66.72 82.08 66.744 ;
    END
  END unavailable_fault[11]
  PIN unavailable_fault[12]
    DIRECTION INPUT ;
    USE SIGNAL ;
    PORT
      LAYER M4 ;
        RECT  81.996 68.256 82.08 68.28 ;
    END
  END unavailable_fault[12]
  PIN unavailable_fault[13]
    DIRECTION INPUT ;
    USE SIGNAL ;
    PORT
      LAYER M4 ;
        RECT  81.996 69.792 82.08 69.816 ;
    END
  END unavailable_fault[13]
  PIN unavailable_fault[14]
    DIRECTION INPUT ;
    USE SIGNAL ;
    PORT
      LAYER M4 ;
        RECT  81.996 71.328 82.08 71.352 ;
    END
  END unavailable_fault[14]
  PIN unavailable_fault[15]
    DIRECTION INPUT ;
    USE SIGNAL ;
    PORT
      LAYER M4 ;
        RECT  81.996 72.864 82.08 72.888 ;
    END
  END unavailable_fault[15]
  PIN unavailable_fault[16]
    DIRECTION INPUT ;
    USE SIGNAL ;
    PORT
      LAYER M4 ;
        RECT  81.996 74.448 82.08 74.472 ;
    END
  END unavailable_fault[16]
  PIN unavailable_fault[17]
    DIRECTION INPUT ;
    USE SIGNAL ;
    PORT
      LAYER M4 ;
        RECT  81.996 75.984 82.08 76.008 ;
    END
  END unavailable_fault[17]
  PIN unavailable_fault[1]
    DIRECTION INPUT ;
    USE SIGNAL ;
    PORT
      LAYER M4 ;
        RECT  81.996 51.216 82.08 51.24 ;
    END
  END unavailable_fault[1]
  PIN unavailable_fault[2]
    DIRECTION INPUT ;
    USE SIGNAL ;
    PORT
      LAYER M4 ;
        RECT  81.996 52.8 82.08 52.824 ;
    END
  END unavailable_fault[2]
  PIN unavailable_fault[3]
    DIRECTION INPUT ;
    USE SIGNAL ;
    PORT
      LAYER M4 ;
        RECT  81.996 54.336 82.08 54.36 ;
    END
  END unavailable_fault[3]
  PIN unavailable_fault[4]
    DIRECTION INPUT ;
    USE SIGNAL ;
    PORT
      LAYER M4 ;
        RECT  81.996 55.872 82.08 55.896 ;
    END
  END unavailable_fault[4]
  PIN unavailable_fault[5]
    DIRECTION INPUT ;
    USE SIGNAL ;
    PORT
      LAYER M4 ;
        RECT  81.996 57.408 82.08 57.432 ;
    END
  END unavailable_fault[5]
  PIN unavailable_fault[6]
    DIRECTION INPUT ;
    USE SIGNAL ;
    PORT
      LAYER M4 ;
        RECT  81.996 58.992 82.08 59.016 ;
    END
  END unavailable_fault[6]
  PIN unavailable_fault[7]
    DIRECTION INPUT ;
    USE SIGNAL ;
    PORT
      LAYER M4 ;
        RECT  81.996 60.528 82.08 60.552 ;
    END
  END unavailable_fault[7]
  PIN unavailable_fault[8]
    DIRECTION INPUT ;
    USE SIGNAL ;
    PORT
      LAYER M4 ;
        RECT  81.996 62.064 82.08 62.088 ;
    END
  END unavailable_fault[8]
  PIN unavailable_fault[9]
    DIRECTION INPUT ;
    USE SIGNAL ;
    PORT
      LAYER M4 ;
        RECT  81.996 63.6 82.08 63.624 ;
    END
  END unavailable_fault[9]
  PIN writer_fault
    DIRECTION INPUT ;
    USE SIGNAL ;
    PORT
      LAYER M4 ;
        RECT  0 69.168 0.084 69.192 ;
    END
  END writer_fault
  PIN VDD
    DIRECTION INOUT ;
    USE POWER ;
    PORT
      LAYER M5 ;
        RECT  78.192 2.151 78.312 75.609 ;
        RECT  72.792 2.151 72.912 75.609 ;
        RECT  67.392 2.151 67.512 75.609 ;
        RECT  61.992 2.151 62.112 75.609 ;
        RECT  56.592 2.151 56.712 75.609 ;
        RECT  51.192 2.151 51.312 75.609 ;
        RECT  45.792 2.151 45.912 75.609 ;
        RECT  40.392 2.151 40.512 75.609 ;
        RECT  34.992 2.151 35.112 75.609 ;
        RECT  29.592 2.151 29.712 75.609 ;
        RECT  24.192 2.151 24.312 75.609 ;
        RECT  18.792 2.151 18.912 75.609 ;
        RECT  13.392 2.151 13.512 75.609 ;
        RECT  7.992 2.151 8.112 75.609 ;
        RECT  2.592 2.151 2.712 75.609 ;
    END
  END VDD
  PIN VSS
    DIRECTION INOUT ;
    USE GROUND ;
    PORT
      LAYER M5 ;
        RECT  78 2.137 78.12 75.623 ;
        RECT  72.6 2.137 72.72 75.623 ;
        RECT  67.2 2.137 67.32 75.623 ;
        RECT  61.8 2.137 61.92 75.623 ;
        RECT  56.4 2.137 56.52 75.623 ;
        RECT  51 2.137 51.12 75.623 ;
        RECT  45.6 2.137 45.72 75.623 ;
        RECT  40.2 2.137 40.32 75.623 ;
        RECT  34.8 2.137 34.92 75.623 ;
        RECT  29.4 2.137 29.52 75.623 ;
        RECT  24 2.137 24.12 75.623 ;
        RECT  18.6 2.137 18.72 75.623 ;
        RECT  13.2 2.137 13.32 75.623 ;
        RECT  7.8 2.137 7.92 75.623 ;
        RECT  2.4 2.137 2.52 75.623 ;
    END
  END VSS
  OBS
    LAYER LVTN ;
     RECT  65.826 15.525 66.366 15.66 ;
     RECT  55.134 15.66 55.458 15.795 ;
     RECT  56.646 19.44 57.294 19.575 ;
     RECT  53.838 19.845 54.648 19.98 ;
     RECT  55.188 19.845 55.62 19.98 ;
     RECT  55.026 19.98 55.35 20.115 ;
     RECT  53.676 20.385 54.27 20.52 ;
     RECT  59.616 20.385 59.94 20.52 ;
     RECT  39.474 20.52 39.906 20.655 ;
     RECT  55.026 20.52 55.512 20.655 ;
     RECT  52.434 20.925 53.244 21.06 ;
     RECT  57.51 20.925 58.158 21.06 ;
     RECT  55.35 21.06 55.836 21.195 ;
     RECT  57.888 21.465 58.482 21.6 ;
     RECT  54.594 21.6 54.972 21.735 ;
     RECT  54.756 22.005 55.512 22.14 ;
     RECT  55.836 22.14 56.16 22.275 ;
     RECT  7.506 22.545 8.046 22.68 ;
     RECT  57.672 22.68 58.536 22.815 ;
     RECT  32.184 23.085 32.724 23.22 ;
     RECT  57.618 23.085 57.942 23.22 ;
     RECT  31.698 23.22 32.13 23.355 ;
     RECT  35.64 23.22 36.072 23.355 ;
     RECT  36.18 23.22 36.612 23.355 ;
     RECT  55.134 23.22 55.458 23.355 ;
     RECT  38.178 23.76 38.502 23.895 ;
     RECT  34.452 24.165 34.776 24.3 ;
     RECT  58.32 24.165 59.184 24.3 ;
     RECT  31.05 24.84 31.536 24.975 ;
     RECT  61.02 24.84 61.56 24.975 ;
     RECT  50.436 25.245 50.814 25.38 ;
     RECT  50.598 25.38 51.03 25.515 ;
     RECT  65.34 25.38 65.664 25.515 ;
     RECT  61.452 25.785 61.992 25.92 ;
     RECT  76.41 25.785 76.734 25.92 ;
     RECT  37.962 28.08 38.826 28.215 ;
     RECT  33.696 28.485 34.02 28.62 ;
     RECT  38.016 28.62 38.178 28.755 ;
     RECT  69.822 28.62 70.146 28.755 ;
     RECT  37.638 29.025 38.178 29.16 ;
     RECT  69.93 29.025 70.47 29.16 ;
     RECT  56.214 29.565 56.646 29.7 ;
     RECT  39.852 29.7 40.392 29.835 ;
     RECT  56.16 30.24 56.43 30.375 ;
     RECT  40.608 36.72 40.878 36.855 ;
     RECT  40.716 37.26 41.148 37.395 ;
     RECT  65.988 37.665 66.528 37.8 ;
     RECT  65.016 38.745 65.34 38.88 ;
     RECT  24.192 39.42 24.57 39.555 ;
     RECT  24.894 39.42 25.434 39.555 ;
     RECT  25.056 40.905 25.92 41.04 ;
     RECT  25.812 41.04 26.406 41.175 ;
     RECT  29.808 42.12 30.132 42.255 ;
     RECT  65.718 42.66 67.122 42.795 ;
     RECT  29.592 43.065 30.348 43.2 ;
     RECT  31.806 47.52 32.67 47.655 ;
     RECT  38.07 58.86 38.502 58.995 ;
     RECT  40.716 58.86 41.094 58.995 ;
     RECT  77.274 61.425 78.678 61.56 ;
     RECT  53.784 69.12 54.216 69.255 ;
     RECT  53.406 70.065 53.784 70.2 ;
     RECT  77.922 71.28 79.326 71.415 ;
    LAYER LVTP ;
     RECT  65.826 15.39 66.366 15.525 ;
     RECT  55.134 15.795 55.458 15.93 ;
     RECT  56.646 19.575 57.294 19.71 ;
     RECT  53.838 19.71 54.648 19.845 ;
     RECT  55.188 19.71 55.62 19.845 ;
     RECT  55.026 20.115 55.35 20.25 ;
     RECT  53.676 20.25 54.27 20.385 ;
     RECT  59.616 20.25 59.94 20.385 ;
     RECT  39.474 20.655 39.906 20.79 ;
     RECT  55.026 20.655 55.512 20.79 ;
     RECT  52.434 20.79 53.244 20.925 ;
     RECT  57.51 20.79 58.158 20.925 ;
     RECT  55.35 21.195 55.836 21.33 ;
     RECT  57.888 21.33 58.482 21.465 ;
     RECT  54.594 21.735 54.972 21.87 ;
     RECT  54.756 21.87 55.512 22.005 ;
     RECT  55.836 22.275 56.16 22.41 ;
     RECT  7.506 22.41 8.046 22.545 ;
     RECT  57.672 22.815 58.536 22.95 ;
     RECT  32.184 22.95 32.724 23.085 ;
     RECT  57.618 22.95 57.942 23.085 ;
     RECT  31.698 23.355 32.13 23.49 ;
     RECT  35.64 23.355 36.072 23.49 ;
     RECT  36.18 23.355 36.612 23.49 ;
     RECT  55.134 23.355 55.458 23.49 ;
     RECT  38.178 23.895 38.502 24.03 ;
     RECT  34.452 24.03 34.776 24.165 ;
     RECT  58.32 24.03 59.184 24.165 ;
     RECT  31.05 24.975 31.536 25.11 ;
     RECT  61.02 24.975 61.56 25.11 ;
     RECT  50.436 25.11 50.814 25.245 ;
     RECT  50.598 25.515 51.03 25.65 ;
     RECT  65.34 25.515 65.664 25.65 ;
     RECT  61.452 25.65 61.992 25.785 ;
     RECT  76.41 25.65 76.734 25.785 ;
     RECT  37.962 28.215 38.826 28.35 ;
     RECT  33.696 28.35 34.02 28.485 ;
     RECT  38.016 28.755 38.178 28.89 ;
     RECT  69.822 28.755 70.146 28.89 ;
     RECT  37.638 28.89 38.178 29.025 ;
     RECT  69.93 28.89 70.47 29.025 ;
     RECT  56.214 29.43 56.646 29.565 ;
     RECT  39.852 29.835 40.392 29.97 ;
     RECT  56.16 30.375 56.43 30.51 ;
     RECT  40.608 36.855 40.878 36.99 ;
     RECT  40.716 37.395 41.148 37.53 ;
     RECT  65.988 37.53 66.528 37.665 ;
     RECT  65.016 38.61 65.34 38.745 ;
     RECT  24.192 39.555 24.57 39.69 ;
     RECT  24.894 39.555 25.434 39.69 ;
     RECT  25.056 40.77 25.92 40.905 ;
     RECT  25.812 41.175 26.406 41.31 ;
     RECT  29.808 42.255 30.132 42.39 ;
     RECT  65.718 42.795 67.122 42.93 ;
     RECT  29.592 42.93 30.348 43.065 ;
     RECT  31.806 47.655 32.67 47.79 ;
     RECT  38.07 58.995 38.502 59.13 ;
     RECT  40.716 58.995 41.094 59.13 ;
     RECT  77.274 61.29 78.678 61.425 ;
     RECT  53.784 69.255 54.216 69.39 ;
     RECT  53.406 69.93 53.784 70.065 ;
     RECT  77.922 71.415 79.326 71.55 ;
    LAYER RVTN ;
     RECT  2.16 2.16 79.92 2.295 ;
     RECT  2.16 2.565 79.92 2.835 ;
     RECT  2.16 3.105 79.92 3.375 ;
     RECT  2.16 3.645 79.92 3.915 ;
     RECT  2.16 4.185 79.92 4.455 ;
     RECT  2.16 4.725 79.92 4.995 ;
     RECT  2.16 5.265 79.92 5.535 ;
     RECT  2.16 5.805 79.92 6.075 ;
     RECT  2.16 6.345 79.92 6.615 ;
     RECT  2.16 6.885 79.92 7.155 ;
     RECT  2.16 7.425 79.92 7.695 ;
     RECT  2.16 7.965 79.92 8.235 ;
     RECT  2.16 8.505 79.92 8.775 ;
     RECT  2.16 9.045 79.92 9.315 ;
     RECT  2.16 9.585 79.92 9.855 ;
     RECT  2.16 10.125 79.92 10.395 ;
     RECT  2.16 10.665 79.92 10.935 ;
     RECT  2.16 11.205 79.92 11.475 ;
     RECT  2.16 11.745 79.92 12.015 ;
     RECT  2.16 12.285 79.92 12.555 ;
     RECT  2.16 12.825 79.92 13.095 ;
     RECT  2.16 13.365 79.92 13.635 ;
     RECT  2.16 13.905 79.92 14.175 ;
     RECT  2.16 14.445 79.92 14.715 ;
     RECT  2.16 14.985 79.92 15.255 ;
     RECT  2.16 15.525 65.826 15.66 ;
     RECT  66.366 15.525 79.92 15.66 ;
     RECT  2.16 15.66 55.134 15.795 ;
     RECT  55.458 15.66 79.92 15.795 ;
     RECT  2.16 16.065 79.92 16.335 ;
     RECT  2.16 16.605 79.92 16.875 ;
     RECT  2.16 17.145 79.92 17.415 ;
     RECT  2.16 17.685 79.92 17.955 ;
     RECT  2.16 18.225 79.92 18.495 ;
     RECT  2.16 18.765 79.92 19.035 ;
     RECT  2.16 19.305 79.92 19.44 ;
     RECT  2.16 19.44 56.646 19.575 ;
     RECT  57.294 19.44 79.92 19.575 ;
     RECT  2.16 19.845 53.838 19.98 ;
     RECT  54.648 19.845 55.188 19.98 ;
     RECT  55.62 19.845 79.92 19.98 ;
     RECT  2.16 19.98 55.026 20.115 ;
     RECT  55.35 19.98 79.92 20.115 ;
     RECT  2.16 20.385 53.676 20.52 ;
     RECT  54.27 20.385 59.616 20.52 ;
     RECT  59.94 20.385 79.92 20.52 ;
     RECT  2.16 20.52 39.474 20.655 ;
     RECT  39.906 20.52 55.026 20.655 ;
     RECT  55.512 20.52 79.92 20.655 ;
     RECT  2.16 20.925 52.434 21.06 ;
     RECT  53.244 20.925 57.51 21.06 ;
     RECT  58.158 20.925 79.92 21.06 ;
     RECT  2.16 21.06 55.35 21.195 ;
     RECT  55.836 21.06 79.92 21.195 ;
     RECT  2.16 21.465 57.888 21.6 ;
     RECT  58.482 21.465 79.92 21.6 ;
     RECT  2.16 21.6 54.594 21.735 ;
     RECT  54.972 21.6 79.92 21.735 ;
     RECT  2.16 22.005 54.756 22.14 ;
     RECT  55.512 22.005 79.92 22.14 ;
     RECT  2.16 22.14 55.836 22.275 ;
     RECT  56.16 22.14 79.92 22.275 ;
     RECT  2.16 22.545 7.506 22.68 ;
     RECT  8.046 22.545 79.92 22.68 ;
     RECT  2.16 22.68 57.672 22.815 ;
     RECT  58.536 22.68 79.92 22.815 ;
     RECT  2.16 23.085 32.184 23.22 ;
     RECT  32.724 23.085 57.618 23.22 ;
     RECT  57.942 23.085 79.92 23.22 ;
     RECT  2.16 23.22 31.698 23.355 ;
     RECT  32.13 23.22 35.64 23.355 ;
     RECT  36.072 23.22 36.18 23.355 ;
     RECT  36.612 23.22 55.134 23.355 ;
     RECT  55.458 23.22 79.92 23.355 ;
     RECT  2.16 23.625 79.92 23.76 ;
     RECT  2.16 23.76 38.178 23.895 ;
     RECT  38.502 23.76 79.92 23.895 ;
     RECT  2.16 24.165 34.452 24.3 ;
     RECT  34.776 24.165 58.32 24.3 ;
     RECT  59.184 24.165 79.92 24.3 ;
     RECT  2.16 24.3 79.92 24.435 ;
     RECT  2.16 24.705 79.92 24.84 ;
     RECT  2.16 24.84 31.05 24.975 ;
     RECT  31.536 24.84 61.02 24.975 ;
     RECT  61.56 24.84 79.92 24.975 ;
     RECT  2.16 25.245 50.436 25.38 ;
     RECT  50.814 25.245 79.92 25.38 ;
     RECT  2.16 25.38 50.598 25.515 ;
     RECT  51.03 25.38 65.34 25.515 ;
     RECT  65.664 25.38 79.92 25.515 ;
     RECT  2.16 25.785 61.452 25.92 ;
     RECT  61.992 25.785 76.41 25.92 ;
     RECT  76.734 25.785 79.92 25.92 ;
     RECT  2.16 25.92 79.92 26.055 ;
     RECT  2.16 26.325 79.92 26.595 ;
     RECT  2.16 26.865 79.92 27.135 ;
     RECT  2.16 27.405 79.92 27.675 ;
     RECT  2.16 27.945 79.92 28.08 ;
     RECT  2.16 28.08 37.962 28.215 ;
     RECT  38.826 28.08 79.92 28.215 ;
     RECT  2.16 28.485 33.696 28.62 ;
     RECT  34.02 28.485 79.92 28.62 ;
     RECT  2.16 28.62 38.016 28.755 ;
     RECT  38.178 28.62 69.822 28.755 ;
     RECT  70.146 28.62 79.92 28.755 ;
     RECT  2.16 29.025 37.638 29.16 ;
     RECT  38.178 29.025 69.93 29.16 ;
     RECT  70.47 29.025 79.92 29.16 ;
     RECT  2.16 29.16 79.92 29.295 ;
     RECT  2.16 29.565 56.214 29.7 ;
     RECT  56.646 29.565 79.92 29.7 ;
     RECT  2.16 29.7 39.852 29.835 ;
     RECT  40.392 29.7 79.92 29.835 ;
     RECT  2.16 30.105 79.92 30.24 ;
     RECT  2.16 30.24 56.16 30.375 ;
     RECT  56.43 30.24 79.92 30.375 ;
     RECT  2.16 30.645 79.92 30.915 ;
     RECT  2.16 31.185 79.92 31.455 ;
     RECT  2.16 31.725 79.92 31.995 ;
     RECT  2.16 32.265 79.92 32.535 ;
     RECT  2.16 32.805 79.92 33.075 ;
     RECT  2.16 33.345 79.92 33.615 ;
     RECT  2.16 33.885 79.92 34.155 ;
     RECT  2.16 34.425 79.92 34.695 ;
     RECT  2.16 34.965 79.92 35.235 ;
     RECT  2.16 35.505 79.92 35.775 ;
     RECT  2.16 36.045 79.92 36.315 ;
     RECT  2.16 36.585 79.92 36.72 ;
     RECT  2.16 36.72 40.608 36.855 ;
     RECT  40.878 36.72 79.92 36.855 ;
     RECT  2.16 37.125 79.92 37.26 ;
     RECT  2.16 37.26 40.716 37.395 ;
     RECT  41.148 37.26 79.92 37.395 ;
     RECT  2.16 37.665 65.988 37.8 ;
     RECT  66.528 37.665 79.92 37.8 ;
     RECT  2.16 37.8 79.92 37.935 ;
     RECT  2.16 38.205 79.92 38.475 ;
     RECT  2.16 38.745 65.016 38.88 ;
     RECT  65.34 38.745 79.92 38.88 ;
     RECT  2.16 38.88 79.92 39.015 ;
     RECT  2.16 39.285 79.92 39.42 ;
     RECT  2.16 39.42 24.192 39.555 ;
     RECT  24.57 39.42 24.894 39.555 ;
     RECT  25.434 39.42 79.92 39.555 ;
     RECT  2.16 39.825 79.92 40.095 ;
     RECT  2.16 40.365 79.92 40.635 ;
     RECT  2.16 40.905 25.056 41.04 ;
     RECT  25.92 40.905 79.92 41.04 ;
     RECT  2.16 41.04 25.812 41.175 ;
     RECT  26.406 41.04 79.92 41.175 ;
     RECT  2.16 41.445 79.92 41.715 ;
     RECT  2.16 41.985 79.92 42.12 ;
     RECT  2.16 42.12 29.808 42.255 ;
     RECT  30.132 42.12 79.92 42.255 ;
     RECT  2.16 42.525 79.92 42.66 ;
     RECT  2.16 42.66 65.718 42.795 ;
     RECT  67.122 42.66 79.92 42.795 ;
     RECT  2.16 43.065 29.592 43.2 ;
     RECT  30.348 43.065 79.92 43.2 ;
     RECT  2.16 43.2 79.92 43.335 ;
     RECT  2.16 43.605 79.92 43.875 ;
     RECT  2.16 44.145 79.92 44.415 ;
     RECT  2.16 44.685 79.92 44.955 ;
     RECT  2.16 45.225 79.92 45.495 ;
     RECT  2.16 45.765 79.92 46.035 ;
     RECT  2.16 46.305 79.92 46.575 ;
     RECT  2.16 46.845 79.92 47.115 ;
     RECT  2.16 47.385 79.92 47.52 ;
     RECT  2.16 47.52 31.806 47.655 ;
     RECT  32.67 47.52 79.92 47.655 ;
     RECT  2.16 47.925 79.92 48.195 ;
     RECT  2.16 48.465 79.92 48.735 ;
     RECT  2.16 49.005 79.92 49.275 ;
     RECT  2.16 49.545 79.92 49.815 ;
     RECT  2.16 50.085 79.92 50.355 ;
     RECT  2.16 50.625 79.92 50.895 ;
     RECT  2.16 51.165 79.92 51.435 ;
     RECT  2.16 51.705 79.92 51.975 ;
     RECT  2.16 52.245 79.92 52.515 ;
     RECT  2.16 52.785 79.92 53.055 ;
     RECT  2.16 53.325 79.92 53.595 ;
     RECT  2.16 53.865 79.92 54.135 ;
     RECT  2.16 54.405 79.92 54.675 ;
     RECT  2.16 54.945 79.92 55.215 ;
     RECT  2.16 55.485 79.92 55.755 ;
     RECT  2.16 56.025 79.92 56.295 ;
     RECT  2.16 56.565 79.92 56.835 ;
     RECT  2.16 57.105 79.92 57.375 ;
     RECT  2.16 57.645 79.92 57.915 ;
     RECT  2.16 58.185 79.92 58.455 ;
     RECT  2.16 58.725 79.92 58.86 ;
     RECT  2.16 58.86 38.07 58.995 ;
     RECT  38.502 58.86 40.716 58.995 ;
     RECT  41.094 58.86 79.92 58.995 ;
     RECT  2.16 59.265 79.92 59.535 ;
     RECT  2.16 59.805 79.92 60.075 ;
     RECT  2.16 60.345 79.92 60.615 ;
     RECT  2.16 60.885 79.92 61.155 ;
     RECT  2.16 61.425 77.274 61.56 ;
     RECT  78.678 61.425 79.92 61.56 ;
     RECT  2.16 61.56 79.92 61.695 ;
     RECT  2.16 61.965 79.92 62.235 ;
     RECT  2.16 62.505 79.92 62.775 ;
     RECT  2.16 63.045 79.92 63.315 ;
     RECT  2.16 63.585 79.92 63.855 ;
     RECT  2.16 64.125 79.92 64.395 ;
     RECT  2.16 64.665 79.92 64.935 ;
     RECT  2.16 65.205 79.92 65.475 ;
     RECT  2.16 65.745 79.92 66.015 ;
     RECT  2.16 66.285 79.92 66.555 ;
     RECT  2.16 66.825 79.92 67.095 ;
     RECT  2.16 67.365 79.92 67.635 ;
     RECT  2.16 67.905 79.92 68.175 ;
     RECT  2.16 68.445 79.92 68.715 ;
     RECT  2.16 68.985 79.92 69.12 ;
     RECT  2.16 69.12 53.784 69.255 ;
     RECT  54.216 69.12 79.92 69.255 ;
     RECT  2.16 69.525 79.92 69.795 ;
     RECT  2.16 70.065 53.406 70.2 ;
     RECT  53.784 70.065 79.92 70.2 ;
     RECT  2.16 70.2 79.92 70.335 ;
     RECT  2.16 70.605 79.92 70.875 ;
     RECT  2.16 71.145 79.92 71.28 ;
     RECT  2.16 71.28 77.922 71.415 ;
     RECT  79.326 71.28 79.92 71.415 ;
     RECT  2.16 71.685 79.92 71.955 ;
     RECT  2.16 72.225 79.92 72.495 ;
     RECT  2.16 72.765 79.92 73.035 ;
     RECT  2.16 73.305 79.92 73.575 ;
     RECT  2.16 73.845 79.92 74.115 ;
     RECT  2.16 74.385 79.92 74.655 ;
     RECT  2.16 74.925 79.92 75.195 ;
     RECT  2.16 75.465 79.92 75.6 ;
    LAYER RVTP ;
     RECT  2.16 2.295 79.92 2.565 ;
     RECT  2.16 2.835 79.92 3.105 ;
     RECT  2.16 3.375 79.92 3.645 ;
     RECT  2.16 3.915 79.92 4.185 ;
     RECT  2.16 4.455 79.92 4.725 ;
     RECT  2.16 4.995 79.92 5.265 ;
     RECT  2.16 5.535 79.92 5.805 ;
     RECT  2.16 6.075 79.92 6.345 ;
     RECT  2.16 6.615 79.92 6.885 ;
     RECT  2.16 7.155 79.92 7.425 ;
     RECT  2.16 7.695 79.92 7.965 ;
     RECT  2.16 8.235 79.92 8.505 ;
     RECT  2.16 8.775 79.92 9.045 ;
     RECT  2.16 9.315 79.92 9.585 ;
     RECT  2.16 9.855 79.92 10.125 ;
     RECT  2.16 10.395 79.92 10.665 ;
     RECT  2.16 10.935 79.92 11.205 ;
     RECT  2.16 11.475 79.92 11.745 ;
     RECT  2.16 12.015 79.92 12.285 ;
     RECT  2.16 12.555 79.92 12.825 ;
     RECT  2.16 13.095 79.92 13.365 ;
     RECT  2.16 13.635 79.92 13.905 ;
     RECT  2.16 14.175 79.92 14.445 ;
     RECT  2.16 14.715 79.92 14.985 ;
     RECT  2.16 15.255 79.92 15.39 ;
     RECT  2.16 15.39 65.826 15.525 ;
     RECT  66.366 15.39 79.92 15.525 ;
     RECT  2.16 15.795 55.134 15.93 ;
     RECT  55.458 15.795 79.92 15.93 ;
     RECT  2.16 15.93 79.92 16.065 ;
     RECT  2.16 16.335 79.92 16.605 ;
     RECT  2.16 16.875 79.92 17.145 ;
     RECT  2.16 17.415 79.92 17.685 ;
     RECT  2.16 17.955 79.92 18.225 ;
     RECT  2.16 18.495 79.92 18.765 ;
     RECT  2.16 19.035 79.92 19.305 ;
     RECT  2.16 19.575 56.646 19.71 ;
     RECT  57.294 19.575 79.92 19.71 ;
     RECT  2.16 19.71 53.838 19.845 ;
     RECT  54.648 19.71 55.188 19.845 ;
     RECT  55.62 19.71 79.92 19.845 ;
     RECT  2.16 20.115 55.026 20.25 ;
     RECT  55.35 20.115 79.92 20.25 ;
     RECT  2.16 20.25 53.676 20.385 ;
     RECT  54.27 20.25 59.616 20.385 ;
     RECT  59.94 20.25 79.92 20.385 ;
     RECT  2.16 20.655 39.474 20.79 ;
     RECT  39.906 20.655 55.026 20.79 ;
     RECT  55.512 20.655 79.92 20.79 ;
     RECT  2.16 20.79 52.434 20.925 ;
     RECT  53.244 20.79 57.51 20.925 ;
     RECT  58.158 20.79 79.92 20.925 ;
     RECT  2.16 21.195 55.35 21.33 ;
     RECT  55.836 21.195 79.92 21.33 ;
     RECT  2.16 21.33 57.888 21.465 ;
     RECT  58.482 21.33 79.92 21.465 ;
     RECT  2.16 21.735 54.594 21.87 ;
     RECT  54.972 21.735 79.92 21.87 ;
     RECT  2.16 21.87 54.756 22.005 ;
     RECT  55.512 21.87 79.92 22.005 ;
     RECT  2.16 22.275 55.836 22.41 ;
     RECT  56.16 22.275 79.92 22.41 ;
     RECT  2.16 22.41 7.506 22.545 ;
     RECT  8.046 22.41 79.92 22.545 ;
     RECT  2.16 22.815 57.672 22.95 ;
     RECT  58.536 22.815 79.92 22.95 ;
     RECT  2.16 22.95 32.184 23.085 ;
     RECT  32.724 22.95 57.618 23.085 ;
     RECT  57.942 22.95 79.92 23.085 ;
     RECT  2.16 23.355 31.698 23.49 ;
     RECT  32.13 23.355 35.64 23.49 ;
     RECT  36.072 23.355 36.18 23.49 ;
     RECT  36.612 23.355 55.134 23.49 ;
     RECT  55.458 23.355 79.92 23.49 ;
     RECT  2.16 23.49 79.92 23.625 ;
     RECT  2.16 23.895 38.178 24.03 ;
     RECT  38.502 23.895 79.92 24.03 ;
     RECT  2.16 24.03 34.452 24.165 ;
     RECT  34.776 24.03 58.32 24.165 ;
     RECT  59.184 24.03 79.92 24.165 ;
     RECT  2.16 24.435 79.92 24.705 ;
     RECT  2.16 24.975 31.05 25.11 ;
     RECT  31.536 24.975 61.02 25.11 ;
     RECT  61.56 24.975 79.92 25.11 ;
     RECT  2.16 25.11 50.436 25.245 ;
     RECT  50.814 25.11 79.92 25.245 ;
     RECT  2.16 25.515 50.598 25.65 ;
     RECT  51.03 25.515 65.34 25.65 ;
     RECT  65.664 25.515 79.92 25.65 ;
     RECT  2.16 25.65 61.452 25.785 ;
     RECT  61.992 25.65 76.41 25.785 ;
     RECT  76.734 25.65 79.92 25.785 ;
     RECT  2.16 26.055 79.92 26.325 ;
     RECT  2.16 26.595 79.92 26.865 ;
     RECT  2.16 27.135 79.92 27.405 ;
     RECT  2.16 27.675 79.92 27.945 ;
     RECT  2.16 28.215 37.962 28.35 ;
     RECT  38.826 28.215 79.92 28.35 ;
     RECT  2.16 28.35 33.696 28.485 ;
     RECT  34.02 28.35 79.92 28.485 ;
     RECT  2.16 28.755 38.016 28.89 ;
     RECT  38.178 28.755 69.822 28.89 ;
     RECT  70.146 28.755 79.92 28.89 ;
     RECT  2.16 28.89 37.638 29.025 ;
     RECT  38.178 28.89 69.93 29.025 ;
     RECT  70.47 28.89 79.92 29.025 ;
     RECT  2.16 29.295 79.92 29.43 ;
     RECT  2.16 29.43 56.214 29.565 ;
     RECT  56.646 29.43 79.92 29.565 ;
     RECT  2.16 29.835 39.852 29.97 ;
     RECT  40.392 29.835 79.92 29.97 ;
     RECT  2.16 29.97 79.92 30.105 ;
     RECT  2.16 30.375 56.16 30.51 ;
     RECT  56.43 30.375 79.92 30.51 ;
     RECT  2.16 30.51 79.92 30.645 ;
     RECT  2.16 30.915 79.92 31.185 ;
     RECT  2.16 31.455 79.92 31.725 ;
     RECT  2.16 31.995 79.92 32.265 ;
     RECT  2.16 32.535 79.92 32.805 ;
     RECT  2.16 33.075 79.92 33.345 ;
     RECT  2.16 33.615 79.92 33.885 ;
     RECT  2.16 34.155 79.92 34.425 ;
     RECT  2.16 34.695 79.92 34.965 ;
     RECT  2.16 35.235 79.92 35.505 ;
     RECT  2.16 35.775 79.92 36.045 ;
     RECT  2.16 36.315 79.92 36.585 ;
     RECT  2.16 36.855 40.608 36.99 ;
     RECT  40.878 36.855 79.92 36.99 ;
     RECT  2.16 36.99 79.92 37.125 ;
     RECT  2.16 37.395 40.716 37.53 ;
     RECT  41.148 37.395 79.92 37.53 ;
     RECT  2.16 37.53 65.988 37.665 ;
     RECT  66.528 37.53 79.92 37.665 ;
     RECT  2.16 37.935 79.92 38.205 ;
     RECT  2.16 38.475 79.92 38.61 ;
     RECT  2.16 38.61 65.016 38.745 ;
     RECT  65.34 38.61 79.92 38.745 ;
     RECT  2.16 39.015 79.92 39.285 ;
     RECT  2.16 39.555 24.192 39.69 ;
     RECT  24.57 39.555 24.894 39.69 ;
     RECT  25.434 39.555 79.92 39.69 ;
     RECT  2.16 39.69 79.92 39.825 ;
     RECT  2.16 40.095 79.92 40.365 ;
     RECT  2.16 40.635 79.92 40.77 ;
     RECT  2.16 40.77 25.056 40.905 ;
     RECT  25.92 40.77 79.92 40.905 ;
     RECT  2.16 41.175 25.812 41.31 ;
     RECT  26.406 41.175 79.92 41.31 ;
     RECT  2.16 41.31 79.92 41.445 ;
     RECT  2.16 41.715 79.92 41.985 ;
     RECT  2.16 42.255 29.808 42.39 ;
     RECT  30.132 42.255 79.92 42.39 ;
     RECT  2.16 42.39 79.92 42.525 ;
     RECT  2.16 42.795 65.718 42.93 ;
     RECT  67.122 42.795 79.92 42.93 ;
     RECT  2.16 42.93 29.592 43.065 ;
     RECT  30.348 42.93 79.92 43.065 ;
     RECT  2.16 43.335 79.92 43.605 ;
     RECT  2.16 43.875 79.92 44.145 ;
     RECT  2.16 44.415 79.92 44.685 ;
     RECT  2.16 44.955 79.92 45.225 ;
     RECT  2.16 45.495 79.92 45.765 ;
     RECT  2.16 46.035 79.92 46.305 ;
     RECT  2.16 46.575 79.92 46.845 ;
     RECT  2.16 47.115 79.92 47.385 ;
     RECT  2.16 47.655 31.806 47.79 ;
     RECT  32.67 47.655 79.92 47.79 ;
     RECT  2.16 47.79 79.92 47.925 ;
     RECT  2.16 48.195 79.92 48.465 ;
     RECT  2.16 48.735 79.92 49.005 ;
     RECT  2.16 49.275 79.92 49.545 ;
     RECT  2.16 49.815 79.92 50.085 ;
     RECT  2.16 50.355 79.92 50.625 ;
     RECT  2.16 50.895 79.92 51.165 ;
     RECT  2.16 51.435 79.92 51.705 ;
     RECT  2.16 51.975 79.92 52.245 ;
     RECT  2.16 52.515 79.92 52.785 ;
     RECT  2.16 53.055 79.92 53.325 ;
     RECT  2.16 53.595 79.92 53.865 ;
     RECT  2.16 54.135 79.92 54.405 ;
     RECT  2.16 54.675 79.92 54.945 ;
     RECT  2.16 55.215 79.92 55.485 ;
     RECT  2.16 55.755 79.92 56.025 ;
     RECT  2.16 56.295 79.92 56.565 ;
     RECT  2.16 56.835 79.92 57.105 ;
     RECT  2.16 57.375 79.92 57.645 ;
     RECT  2.16 57.915 79.92 58.185 ;
     RECT  2.16 58.455 79.92 58.725 ;
     RECT  2.16 58.995 38.07 59.13 ;
     RECT  38.502 58.995 40.716 59.13 ;
     RECT  41.094 58.995 79.92 59.13 ;
     RECT  2.16 59.13 79.92 59.265 ;
     RECT  2.16 59.535 79.92 59.805 ;
     RECT  2.16 60.075 79.92 60.345 ;
     RECT  2.16 60.615 79.92 60.885 ;
     RECT  2.16 61.155 79.92 61.29 ;
     RECT  2.16 61.29 77.274 61.425 ;
     RECT  78.678 61.29 79.92 61.425 ;
     RECT  2.16 61.695 79.92 61.965 ;
     RECT  2.16 62.235 79.92 62.505 ;
     RECT  2.16 62.775 79.92 63.045 ;
     RECT  2.16 63.315 79.92 63.585 ;
     RECT  2.16 63.855 79.92 64.125 ;
     RECT  2.16 64.395 79.92 64.665 ;
     RECT  2.16 64.935 79.92 65.205 ;
     RECT  2.16 65.475 79.92 65.745 ;
     RECT  2.16 66.015 79.92 66.285 ;
     RECT  2.16 66.555 79.92 66.825 ;
     RECT  2.16 67.095 79.92 67.365 ;
     RECT  2.16 67.635 79.92 67.905 ;
     RECT  2.16 68.175 79.92 68.445 ;
     RECT  2.16 68.715 79.92 68.985 ;
     RECT  2.16 69.255 53.784 69.39 ;
     RECT  54.216 69.255 79.92 69.39 ;
     RECT  2.16 69.39 79.92 69.525 ;
     RECT  2.16 69.795 79.92 69.93 ;
     RECT  2.16 69.93 53.406 70.065 ;
     RECT  53.784 69.93 79.92 70.065 ;
     RECT  2.16 70.335 79.92 70.605 ;
     RECT  2.16 70.875 79.92 71.145 ;
     RECT  2.16 71.415 77.922 71.55 ;
     RECT  79.326 71.415 79.92 71.55 ;
     RECT  2.16 71.55 79.92 71.685 ;
     RECT  2.16 71.955 79.92 72.225 ;
     RECT  2.16 72.495 79.92 72.765 ;
     RECT  2.16 73.035 79.92 73.305 ;
     RECT  2.16 73.575 79.92 73.845 ;
     RECT  2.16 74.115 79.92 74.385 ;
     RECT  2.16 74.655 79.92 74.925 ;
     RECT  2.16 75.195 79.92 75.465 ;
    LAYER M1 ;
     RECT  2.16 2.151 79.92 75.609 ;
    LAYER M2 ;
     RECT  1.327 74.052 1.579 74.07 ;
     RECT  1.579 73.89 1.795 74.07 ;
     RECT  1.795 73.89 2.047 74.448 ;
     RECT  1.687 2.232 2.16 2.25 ;
     RECT  0.103 8.442 2.16 8.46 ;
     RECT  2.047 73.854 2.16 74.448 ;
     RECT  1.111 75.51 2.16 75.528 ;
     RECT  2.16 2.151 2.371 75.609 ;
     RECT  2.371 2.151 2.543 75.69 ;
     RECT  2.543 2.151 7.771 75.609 ;
     RECT  7.771 2.151 7.871 75.69 ;
     RECT  8.095 77.706 8.195 77.724 ;
     RECT  7.871 2.151 12.667 75.609 ;
     RECT  12.667 2.106 13.415 75.609 ;
     RECT  13.415 2.151 14.539 75.609 ;
     RECT  16.015 0.036 16.115 0.054 ;
     RECT  14.539 2.106 16.547 75.609 ;
     RECT  18.535 77.706 18.815 77.724 ;
     RECT  18.859 0.036 18.959 0.054 ;
     RECT  16.547 2.151 24.583 75.609 ;
     RECT  24.583 1.728 24.863 75.609 ;
     RECT  24.863 2.151 34.843 75.609 ;
     RECT  34.843 2.151 34.979 75.69 ;
     RECT  34.979 2.151 36.031 75.609 ;
     RECT  36.031 1.728 36.311 75.609 ;
     RECT  36.859 76.896 36.995 76.914 ;
     RECT  40.171 0.036 40.343 0.054 ;
     RECT  47.443 76.896 47.543 76.914 ;
     RECT  36.311 2.151 49.639 75.609 ;
     RECT  49.639 2.106 51.395 75.609 ;
     RECT  51.395 2.151 58.351 75.609 ;
     RECT  58.351 2.106 59.215 75.609 ;
     RECT  59.215 2.034 60.611 75.609 ;
     RECT  61.879 77.706 61.979 77.724 ;
     RECT  62.563 76.896 62.699 76.914 ;
     RECT  60.611 2.151 64.615 75.609 ;
     RECT  64.615 2.106 65.327 75.609 ;
     RECT  66.523 76.896 66.659 76.914 ;
     RECT  65.327 2.151 67.135 75.609 ;
     RECT  67.135 2.151 67.235 75.69 ;
     RECT  67.351 77.706 67.487 77.724 ;
     RECT  67.235 2.151 74.983 75.609 ;
     RECT  74.983 2.106 76.055 75.609 ;
     RECT  76.819 76.401 77.711 76.419 ;
     RECT  76.055 2.151 78.259 75.609 ;
     RECT  78.259 2.151 79.92 75.654 ;
     RECT  79.92 69.804 80.267 70.434 ;
     RECT  79.92 2.232 80.375 2.628 ;
     RECT  79.92 4.968 80.375 4.986 ;
     RECT  79.92 6.39 80.375 6.408 ;
     RECT  79.92 42.3 80.411 42.318 ;
     RECT  79.92 44.928 80.411 44.946 ;
     RECT  79.92 48.24 80.411 48.258 ;
     RECT  79.92 72.738 80.411 72.756 ;
     RECT  80.375 2.61 80.735 2.628 ;
     RECT  79.92 3.384 80.735 3.402 ;
     RECT  79.92 14.22 80.735 14.238 ;
     RECT  79.92 74.97 80.735 75.654 ;
     RECT  79.92 57.69 80.807 57.708 ;
     RECT  79.92 9.558 80.915 9.576 ;
     RECT  79.92 11.178 80.915 11.196 ;
     RECT  79.92 15.768 80.915 15.786 ;
     RECT  79.92 21.978 80.915 21.996 ;
     RECT  79.92 55.998 80.915 56.016 ;
     RECT  79.92 20.322 80.951 20.34 ;
     RECT  79.92 23.562 80.951 23.58 ;
     RECT  79.92 24.948 80.951 24.966 ;
     RECT  79.92 26.532 80.951 26.55 ;
     RECT  79.92 28.152 80.951 28.17 ;
     RECT  79.92 29.574 80.951 29.592 ;
     RECT  79.92 31.158 80.951 31.176 ;
     RECT  79.92 32.742 80.951 32.76 ;
     RECT  79.92 34.362 80.951 34.38 ;
     RECT  79.92 35.316 80.951 35.334 ;
     RECT  79.92 37.368 80.951 37.386 ;
     RECT  79.92 38.952 80.951 38.97 ;
     RECT  79.92 40.572 80.951 40.59 ;
     RECT  79.92 43.542 80.951 43.56 ;
     RECT  79.92 46.584 80.951 46.602 ;
     RECT  79.92 50.022 80.951 50.04 ;
     RECT  79.92 51.372 80.951 51.39 ;
     RECT  79.92 52.992 80.951 53.01 ;
     RECT  79.92 54.342 80.951 54.36 ;
     RECT  79.92 58.932 80.951 58.95 ;
     RECT  79.92 60.552 80.951 60.57 ;
     RECT  79.92 62.208 80.951 62.226 ;
     RECT  79.92 63.522 80.951 63.54 ;
     RECT  79.92 65.142 80.951 65.16 ;
     RECT  79.92 66.762 80.951 66.78 ;
     RECT  79.92 68.112 80.951 68.13 ;
     RECT  80.267 69.804 80.951 69.822 ;
     RECT  79.92 17.082 80.987 17.1 ;
     RECT  80.735 74.97 80.987 75.186 ;
     RECT  79.92 7.938 81.491 7.956 ;
     RECT  79.92 12.528 81.491 12.546 ;
     RECT  80.987 74.97 81.491 74.988 ;
    LAYER M3 ;
     RECT  16.02 0.012 16.038 0.031 ;
     RECT  18.864 0.012 18.882 0.031 ;
     RECT  40.32 0.012 40.338 0.031 ;
     RECT  16.02 0.031 16.11 0.059 ;
     RECT  18.864 0.031 18.954 0.059 ;
     RECT  40.176 0.031 40.338 0.059 ;
     RECT  24.588 0.012 24.606 1.723 ;
     RECT  36.036 0.012 36.054 1.723 ;
     RECT  80.352 0.571 80.37 1.771 ;
     RECT  58.932 0.571 58.95 2.029 ;
     RECT  60.372 1.723 60.39 2.029 ;
     RECT  13.14 0.012 13.158 2.101 ;
     RECT  14.58 0.012 14.598 2.101 ;
     RECT  16.092 0.059 16.11 2.101 ;
     RECT  48.924 1.723 48.942 2.101 ;
     RECT  50.292 1.099 50.31 2.101 ;
     RECT  58.932 2.029 59.238 2.101 ;
     RECT  60.372 2.029 60.606 2.101 ;
     RECT  64.62 1.723 64.638 2.101 ;
     RECT  74.376 1.723 74.394 2.101 ;
     RECT  75.852 1.723 75.87 2.101 ;
     RECT  1.692 0.012 1.71 2.143 ;
     RECT  3.132 0.012 3.15 2.143 ;
     RECT  7.416 0.012 7.434 2.143 ;
     RECT  18.936 0.059 18.954 2.143 ;
     RECT  24.588 1.723 24.858 2.143 ;
     RECT  28.872 0.012 28.89 2.143 ;
     RECT  34.596 0.012 34.614 2.143 ;
     RECT  40.176 0.059 40.194 2.143 ;
     RECT  46.044 0.012 46.062 2.143 ;
     RECT  48.924 2.101 50.31 2.143 ;
     RECT  51.372 2.101 51.39 2.143 ;
     RECT  55.944 0.571 55.962 2.143 ;
     RECT  61.776 1.723 61.794 2.143 ;
     RECT  67.536 0.091 67.554 2.143 ;
     RECT  72.972 1.723 72.99 2.143 ;
     RECT  78.696 1.723 78.714 2.143 ;
     RECT  48.924 2.143 51.39 2.155 ;
     RECT  1.692 2.143 3.15 2.191 ;
     RECT  4.572 0.012 4.59 2.191 ;
     RECT  10.296 0.012 10.314 2.191 ;
     RECT  12.672 2.101 13.41 2.191 ;
     RECT  14.544 2.101 16.542 2.191 ;
     RECT  17.424 0.012 17.442 2.191 ;
     RECT  18.615 2.143 18.954 2.191 ;
     RECT  20.304 0.012 20.322 2.191 ;
     RECT  23.148 0.012 23.166 2.191 ;
     RECT  24.015 2.143 24.858 2.191 ;
     RECT  27.432 0.012 27.45 2.191 ;
     RECT  28.872 2.143 29.505 2.191 ;
     RECT  33.156 0.012 33.174 2.191 ;
     RECT  34.596 2.143 34.905 2.191 ;
     RECT  36.036 1.723 36.306 2.191 ;
     RECT  37.44 0.012 37.458 2.191 ;
     RECT  38.88 0.012 38.898 2.191 ;
     RECT  40.176 2.143 40.305 2.191 ;
     RECT  43.164 0.012 43.182 2.191 ;
     RECT  44.604 0.012 44.622 2.191 ;
     RECT  45.615 2.143 46.062 2.191 ;
     RECT  47.484 0.091 47.502 2.191 ;
     RECT  48.924 2.155 51.894 2.191 ;
     RECT  54.648 1.723 54.666 2.191 ;
     RECT  67.215 2.143 67.554 2.191 ;
     RECT  68.724 1.723 68.742 2.191 ;
     RECT  70.128 1.723 70.146 2.191 ;
     RECT  71.532 1.723 71.55 2.191 ;
     RECT  72.615 2.143 72.99 2.191 ;
     RECT  74.376 2.101 75.006 2.191 ;
     RECT  75.852 2.101 76.05 2.191 ;
     RECT  58.356 2.101 60.606 2.219 ;
     RECT  64.62 2.101 65.322 2.219 ;
     RECT  74.376 2.191 76.05 2.219 ;
     RECT  23.148 2.191 24.858 2.227 ;
     RECT  32.94 2.191 33.174 2.227 ;
     RECT  58.716 2.219 60.606 2.227 ;
     RECT  61.776 2.143 61.905 2.227 ;
     RECT  63.252 1.723 63.27 2.227 ;
     RECT  48.492 2.191 51.894 2.251 ;
     RECT  1.692 2.191 3.186 2.255 ;
     RECT  74.376 2.219 74.394 2.255 ;
     RECT  75.24 2.219 75.87 2.255 ;
     RECT  77.256 1.723 77.274 2.255 ;
     RECT  80.352 1.771 80.73 2.255 ;
     RECT  2.415 2.255 3.186 2.263 ;
     RECT  7.416 2.143 7.905 2.263 ;
     RECT  10.296 2.191 10.602 2.263 ;
     RECT  12.672 2.191 16.542 2.263 ;
     RECT  17.424 2.191 17.766 2.263 ;
     RECT  18.615 2.191 19.386 2.263 ;
     RECT  41.76 0.012 41.778 2.263 ;
     RECT  54.144 2.191 54.666 2.263 ;
     RECT  55.944 2.143 56.505 2.263 ;
     RECT  57.456 1.723 57.474 2.263 ;
     RECT  63.252 2.227 63.414 2.263 ;
     RECT  64.62 2.219 65.178 2.263 ;
     RECT  67.215 2.191 70.146 2.263 ;
     RECT  9.684 2.263 10.602 2.291 ;
     RECT  4.572 2.191 4.626 2.299 ;
     RECT  43.164 2.191 46.062 2.335 ;
     RECT  54.144 2.263 57.474 2.335 ;
     RECT  2.415 2.263 3.618 2.371 ;
     RECT  4.572 2.299 5.022 2.371 ;
     RECT  6.012 0.012 6.03 2.371 ;
     RECT  7.128 2.263 7.974 2.371 ;
     RECT  8.856 0.012 8.874 2.371 ;
     RECT  9.684 2.291 10.422 2.371 ;
     RECT  11.7 0.012 11.718 2.371 ;
     RECT  12.672 2.263 19.386 2.371 ;
     RECT  21.744 0.012 21.762 2.371 ;
     RECT  26.028 0.012 26.046 2.371 ;
     RECT  26.82 2.191 29.505 2.371 ;
     RECT  30.312 0.012 30.33 2.371 ;
     RECT  31.752 0.012 31.77 2.371 ;
     RECT  32.868 2.227 33.174 2.371 ;
     RECT  41.4 2.263 41.778 2.371 ;
     RECT  43.164 2.335 46.71 2.371 ;
     RECT  47.484 2.191 47.538 2.371 ;
     RECT  48.492 2.251 52.254 2.371 ;
     RECT  52.992 0.091 53.01 2.371 ;
     RECT  54.108 2.335 57.474 2.371 ;
     RECT  63.252 2.263 65.178 2.371 ;
     RECT  66.06 1.723 66.078 2.371 ;
     RECT  67.14 2.263 70.146 2.371 ;
     RECT  71.532 2.191 72.99 2.371 ;
     RECT  78.015 2.143 78.714 2.371 ;
     RECT  6.84 2.371 7.974 2.413 ;
     RECT  26.028 2.371 29.505 2.413 ;
     RECT  30.312 2.371 32.13 2.413 ;
     RECT  38.88 2.191 40.305 2.413 ;
     RECT  41.184 2.371 47.538 2.413 ;
     RECT  58.716 2.227 61.905 2.413 ;
     RECT  12.492 2.371 19.386 2.461 ;
     RECT  20.304 2.191 20.79 2.461 ;
     RECT  48.492 2.371 53.082 2.461 ;
     RECT  54.108 2.371 57.978 2.461 ;
     RECT  71.532 2.371 73.206 2.488 ;
     RECT  65.952 2.371 70.146 2.491 ;
     RECT  38.88 2.413 47.538 2.533 ;
     RECT  48.492 2.461 57.978 2.533 ;
     RECT  6.84 2.413 8.097 2.561 ;
     RECT  77.4 2.371 79.614 2.621 ;
     RECT  7.092 2.561 8.097 2.641 ;
     RECT  8.856 2.371 10.422 2.641 ;
     RECT  11.376 2.371 11.718 2.641 ;
     RECT  12.492 2.461 20.79 2.641 ;
     RECT  21.528 2.371 21.762 2.641 ;
     RECT  22.536 2.227 24.858 2.641 ;
     RECT  26.028 2.413 32.13 2.641 ;
     RECT  58.716 2.413 62.097 2.641 ;
     RECT  62.856 2.371 65.178 2.641 ;
     RECT  65.952 2.491 70.254 2.641 ;
     RECT  71.46 2.488 73.206 2.641 ;
     RECT  21.528 2.641 24.858 2.731 ;
     RECT  25.668 2.641 32.13 2.731 ;
     RECT  32.868 2.371 33.858 2.731 ;
     RECT  34.596 2.191 38.142 2.731 ;
     RECT  38.88 2.533 57.978 2.731 ;
     RECT  2.415 2.371 6.03 2.759 ;
     RECT  7.092 2.641 10.422 2.759 ;
     RECT  3.6 2.759 4.626 2.795 ;
     RECT  5.544 2.759 5.67 2.795 ;
     RECT  71.172 2.641 73.206 2.803 ;
     RECT  74.124 2.371 74.142 2.803 ;
     RECT  65.952 2.641 70.398 2.839 ;
     RECT  71.172 2.803 74.142 2.839 ;
     RECT  11.376 2.641 20.79 2.911 ;
     RECT  21.528 2.731 32.13 2.911 ;
     RECT  11.376 2.911 32.13 3.001 ;
     RECT  32.868 2.731 57.978 3.001 ;
     RECT  65.952 2.839 74.142 3.001 ;
     RECT  11.376 3.001 57.978 3.181 ;
     RECT  58.716 2.641 65.178 3.181 ;
     RECT  65.952 3.001 74.43 3.181 ;
     RECT  77.688 2.621 79.614 3.181 ;
     RECT  80.712 2.255 80.73 3.407 ;
     RECT  75.24 2.255 75.258 3.451 ;
     RECT  76.644 3.379 76.662 3.451 ;
     RECT  77.688 3.181 79.722 3.451 ;
     RECT  7.128 2.759 10.422 3.541 ;
     RECT  11.376 3.181 74.43 3.541 ;
     RECT  5.652 2.795 5.67 3.649 ;
     RECT  7.128 3.541 74.43 3.649 ;
     RECT  6.804 3.649 74.43 3.685 ;
     RECT  75.24 3.451 76.662 3.685 ;
     RECT  3.6 2.795 4.41 3.721 ;
     RECT  5.22 3.649 5.67 3.721 ;
     RECT  6.804 3.685 76.662 3.721 ;
     RECT  77.436 3.451 79.722 3.721 ;
     RECT  6.804 3.721 79.722 3.839 ;
     RECT  79.02 3.839 79.722 3.875 ;
     RECT  2.415 2.759 2.697 3.931 ;
     RECT  3.6 3.721 5.958 3.931 ;
     RECT  6.804 3.839 74.718 3.983 ;
     RECT  8.928 3.983 74.718 4.013 ;
     RECT  2.415 3.931 5.958 4.027 ;
     RECT  6.804 3.983 8.097 4.027 ;
     RECT  2.415 4.027 8.097 4.109 ;
     RECT  2.415 4.109 5.166 4.145 ;
     RECT  4.176 4.145 5.166 4.217 ;
     RECT  6.048 4.109 8.097 4.289 ;
     RECT  2.415 4.145 3.402 4.379 ;
     RECT  75.708 3.839 78.297 4.379 ;
     RECT  6.048 4.289 6.966 4.415 ;
     RECT  6.048 4.415 6.318 4.487 ;
     RECT  9.072 4.013 74.718 4.621 ;
     RECT  9.072 4.621 74.97 4.693 ;
     RECT  75.708 4.379 77.094 4.693 ;
     RECT  79.164 3.875 79.722 4.843 ;
     RECT  79.164 4.843 80.37 4.991 ;
     RECT  78.015 4.379 78.297 5.071 ;
     RECT  79.164 4.991 79.722 5.071 ;
     RECT  7.815 4.289 8.097 5.131 ;
     RECT  7.815 5.131 8.298 5.503 ;
     RECT  9.072 4.693 77.094 5.503 ;
     RECT  4.176 4.217 4.842 5.729 ;
     RECT  7.815 5.503 77.094 5.773 ;
     RECT  78.015 5.071 79.722 5.773 ;
     RECT  7.02 5.701 7.038 5.845 ;
     RECT  7.815 5.773 79.722 5.845 ;
     RECT  7.02 5.845 79.722 6.115 ;
     RECT  6.84 6.115 79.722 6.269 ;
     RECT  79.164 6.269 79.722 6.376 ;
     RECT  79.164 6.376 80.37 6.413 ;
     RECT  6.048 4.487 6.066 6.811 ;
     RECT  6.012 6.811 6.066 6.925 ;
     RECT  6.84 6.269 78.297 6.925 ;
     RECT  5.148 6.859 5.166 7.087 ;
     RECT  6.012 6.925 78.297 7.087 ;
     RECT  5.148 7.087 78.297 7.159 ;
     RECT  5.148 7.159 78.426 7.357 ;
     RECT  79.164 6.413 79.722 7.357 ;
     RECT  5.148 7.357 79.722 7.591 ;
     RECT  4.176 5.729 4.194 7.699 ;
     RECT  5.004 7.591 79.722 7.699 ;
     RECT  4.176 7.699 79.722 7.771 ;
     RECT  81.468 7.933 81.486 7.997 ;
     RECT  0.108 8.437 0.126 8.573 ;
     RECT  2.415 4.379 2.697 8.581 ;
     RECT  2.415 8.581 3.15 8.815 ;
     RECT  2.415 8.815 3.294 8.851 ;
     RECT  4.068 7.771 79.722 8.851 ;
     RECT  2.415 8.851 79.722 9.101 ;
     RECT  3.888 9.101 79.722 9.391 ;
     RECT  80.892 9.499 80.91 9.581 ;
     RECT  3.888 9.391 79.794 9.923 ;
     RECT  2.415 9.101 2.826 9.931 ;
     RECT  3.888 9.923 79.722 9.931 ;
     RECT  80.892 11.035 80.91 11.201 ;
     RECT  81.468 12.523 81.486 12.605 ;
     RECT  2.415 9.931 79.722 14.203 ;
     RECT  80.712 14.107 80.73 14.243 ;
     RECT  2.376 14.203 79.722 15.449 ;
     RECT  80.892 15.691 80.91 15.791 ;
     RECT  2.415 15.449 79.722 16.375 ;
     RECT  2.415 16.375 79.794 16.799 ;
     RECT  80.964 17.077 80.982 17.261 ;
     RECT  2.415 16.799 79.722 18.733 ;
     RECT  2.415 18.733 79.794 18.797 ;
     RECT  2.415 18.797 79.722 18.967 ;
     RECT  2.376 18.967 79.722 20.011 ;
     RECT  80.928 20.299 80.946 20.345 ;
     RECT  80.892 21.835 80.91 22.001 ;
     RECT  2.34 20.011 79.722 22.621 ;
     RECT  80.928 23.419 80.946 23.585 ;
     RECT  2.34 22.621 79.794 23.707 ;
     RECT  2.304 23.707 79.794 23.819 ;
     RECT  2.304 23.819 79.722 23.855 ;
     RECT  80.928 24.943 80.946 24.989 ;
     RECT  2.34 23.855 79.722 25.051 ;
     RECT  2.34 25.051 79.794 25.169 ;
     RECT  2.34 25.169 79.47 25.565 ;
     RECT  2.415 25.565 79.47 26.329 ;
     RECT  80.928 26.491 80.946 26.555 ;
     RECT  2.34 26.329 79.47 27.239 ;
     RECT  80.928 28.027 80.946 28.175 ;
     RECT  2.376 27.239 79.47 29.371 ;
     RECT  2.376 29.371 79.506 29.489 ;
     RECT  80.928 29.56 80.946 29.597 ;
     RECT  2.376 29.489 79.47 29.875 ;
     RECT  2.34 29.875 79.47 30.701 ;
     RECT  80.928 31.144 80.946 31.181 ;
     RECT  2.415 30.701 79.47 32.203 ;
     RECT  80.928 32.683 80.946 32.765 ;
     RECT  80.928 34.219 80.946 34.385 ;
     RECT  2.376 32.203 79.47 34.699 ;
     RECT  2.376 34.699 79.542 34.889 ;
     RECT  80.928 35.311 80.946 35.789 ;
     RECT  80.928 37.339 80.946 37.391 ;
     RECT  2.376 34.889 79.47 37.435 ;
     RECT  2.376 37.435 79.686 38.669 ;
     RECT  2.376 38.669 79.218 38.875 ;
     RECT  2.304 38.875 79.218 38.975 ;
     RECT  80.928 38.875 80.946 38.975 ;
     RECT  2.415 38.975 79.218 39.515 ;
     RECT  2.415 39.515 79.182 39.857 ;
     RECT  80.928 40.411 80.946 40.595 ;
     RECT  2.415 39.857 73.566 40.651 ;
     RECT  74.628 39.857 79.182 40.651 ;
     RECT  2.415 40.651 79.182 40.711 ;
     RECT  2.415 40.711 79.722 40.829 ;
     RECT  2.415 40.829 79.542 41.251 ;
     RECT  2.376 41.251 79.542 41.501 ;
     RECT  2.415 41.501 79.542 42.061 ;
     RECT  2.415 42.061 79.614 42.179 ;
     RECT  80.388 41.947 80.406 42.323 ;
     RECT  2.415 42.179 79.506 42.485 ;
     RECT  2.415 42.485 74.826 42.715 ;
     RECT  75.672 42.485 79.506 43.141 ;
     RECT  2.34 42.715 74.826 43.411 ;
     RECT  75.672 43.141 79.794 43.411 ;
     RECT  80.928 43.483 80.946 43.565 ;
     RECT  2.34 43.411 79.794 44.753 ;
     RECT  80.388 44.923 80.406 45.101 ;
     RECT  2.34 44.753 79.254 45.329 ;
     RECT  2.376 45.329 79.254 45.499 ;
     RECT  2.376 45.499 79.542 45.689 ;
     RECT  80.928 46.579 80.946 46.637 ;
     RECT  2.376 45.689 79.434 46.849 ;
     RECT  2.376 46.849 79.542 46.949 ;
     RECT  2.376 46.949 79.218 47.309 ;
     RECT  2.415 47.309 79.218 47.821 ;
     RECT  2.415 47.821 79.254 48.001 ;
     RECT  2.415 48.001 79.794 48.139 ;
     RECT  2.415 48.139 80.406 48.263 ;
     RECT  2.415 48.263 79.794 48.379 ;
     RECT  2.412 48.379 79.794 48.397 ;
     RECT  2.376 48.397 79.794 48.461 ;
     RECT  2.376 48.461 79.434 49.441 ;
     RECT  2.376 49.441 79.542 49.469 ;
     RECT  2.415 49.469 79.542 49.577 ;
     RECT  80.928 49.675 80.946 50.045 ;
     RECT  2.415 49.577 79.506 50.549 ;
     RECT  2.415 50.549 79.362 50.585 ;
     RECT  2.415 50.585 79.254 50.693 ;
     RECT  80.928 51.211 80.946 51.395 ;
     RECT  2.415 50.693 79.182 51.511 ;
     RECT  2.415 51.511 79.29 51.871 ;
     RECT  2.415 51.871 79.542 52.015 ;
     RECT  2.415 52.015 79.794 52.169 ;
     RECT  80.928 52.795 80.946 53.015 ;
     RECT  2.415 52.169 79.182 53.365 ;
     RECT  2.415 53.365 79.326 53.401 ;
     RECT  2.415 53.401 79.362 53.563 ;
     RECT  2.415 53.563 79.506 53.995 ;
     RECT  2.304 53.995 79.506 54.059 ;
     RECT  2.304 54.059 79.362 54.095 ;
     RECT  80.928 54.328 80.946 54.365 ;
     RECT  2.412 54.095 79.362 54.653 ;
     RECT  2.415 54.653 79.362 54.949 ;
     RECT  2.415 54.949 79.506 55.651 ;
     RECT  80.892 55.867 80.91 56.021 ;
     RECT  2.376 55.651 79.506 56.065 ;
     RECT  2.376 56.065 79.542 56.219 ;
     RECT  2.376 56.219 79.506 56.759 ;
     RECT  80.784 57.403 80.802 57.713 ;
     RECT  2.376 56.759 79.362 57.839 ;
     RECT  2.376 57.839 79.182 58.793 ;
     RECT  2.415 58.793 79.182 58.801 ;
     RECT  2.415 58.801 79.326 58.963 ;
     RECT  80.928 58.927 80.946 59.021 ;
     RECT  2.415 58.963 79.434 59.189 ;
     RECT  2.415 59.189 79.362 59.801 ;
     RECT  80.928 60.523 80.946 60.575 ;
     RECT  15.192 59.801 79.362 60.619 ;
     RECT  15.048 60.619 79.362 60.691 ;
     RECT  15.048 60.691 79.722 60.809 ;
     RECT  2.415 59.801 14.31 60.817 ;
     RECT  15.048 60.809 79.254 60.817 ;
     RECT  2.415 60.817 79.254 60.881 ;
     RECT  2.415 60.881 79.182 61.429 ;
     RECT  2.34 61.429 79.182 61.771 ;
     RECT  80.928 62.059 80.946 62.231 ;
     RECT  2.34 61.771 79.794 63.113 ;
     RECT  80.928 63.517 80.946 63.629 ;
     RECT  2.34 63.113 79.182 64.201 ;
     RECT  2.34 64.201 79.362 64.229 ;
     RECT  2.415 64.229 79.362 64.669 ;
     RECT  2.415 64.669 79.506 64.859 ;
     RECT  80.928 65.128 80.946 65.165 ;
     RECT  2.415 64.859 79.182 65.713 ;
     RECT  2.415 65.713 79.506 66.209 ;
     RECT  80.928 66.715 80.946 66.785 ;
     RECT  2.415 66.209 79.398 66.865 ;
     RECT  2.34 66.865 79.398 67.171 ;
     RECT  2.34 67.171 79.794 67.937 ;
     RECT  80.928 68.107 80.946 68.285 ;
     RECT  2.34 67.937 79.614 69.061 ;
     RECT  2.34 69.061 79.794 69.163 ;
     RECT  2.304 69.163 79.794 69.485 ;
     RECT  2.34 69.485 79.794 69.727 ;
     RECT  80.928 69.787 80.946 69.827 ;
     RECT  2.34 69.727 79.83 70.231 ;
     RECT  2.304 70.231 79.83 70.411 ;
     RECT  2.304 70.411 80.262 72.733 ;
     RECT  2.304 72.733 80.406 72.893 ;
     RECT  2.304 72.893 80.262 73.849 ;
     RECT  2.052 73.849 80.262 73.885 ;
     RECT  1.584 73.885 80.262 74.047 ;
     RECT  1.332 74.047 80.262 75.163 ;
     RECT  81.468 74.965 81.486 75.163 ;
     RECT  1.332 75.163 81.486 75.389 ;
     RECT  39.924 75.389 69.606 75.425 ;
     RECT  1.332 75.389 11.178 75.461 ;
     RECT  39.924 75.425 68.166 75.461 ;
     RECT  70.344 75.389 81.486 75.461 ;
     RECT  1.332 75.461 9.018 75.505 ;
     RECT  10.152 75.461 10.314 75.533 ;
     RECT  39.924 75.461 57.87 75.569 ;
     RECT  70.344 75.461 71.118 75.569 ;
     RECT  72.396 75.461 81.486 75.569 ;
     RECT  11.16 75.461 11.178 75.581 ;
     RECT  40.176 75.569 57.87 75.725 ;
     RECT  12.024 75.389 13.662 75.773 ;
     RECT  40.176 75.725 40.194 75.773 ;
     RECT  41.292 75.725 57.87 75.773 ;
     RECT  72.576 75.569 81.486 75.773 ;
     RECT  1.116 75.505 9.018 75.821 ;
     RECT  10.296 75.533 10.314 75.821 ;
     RECT  12.024 75.773 12.582 75.821 ;
     RECT  14.508 75.389 15.066 75.821 ;
     RECT  16.02 75.389 38.826 75.821 ;
     RECT  41.292 75.773 41.85 75.821 ;
     RECT  42.624 75.773 44.91 75.821 ;
     RECT  45.792 75.773 57.87 75.821 ;
     RECT  58.68 75.461 68.166 75.821 ;
     RECT  69.48 75.425 69.606 75.821 ;
     RECT  70.38 75.569 71.118 75.821 ;
     RECT  73.044 75.773 81.486 75.821 ;
     RECT  28.404 75.821 28.422 75.917 ;
     RECT  75.6 75.821 81.486 76.013 ;
     RECT  12.276 75.821 12.294 76.397 ;
     RECT  24.948 75.821 24.966 76.397 ;
     RECT  27.252 75.821 27.27 76.397 ;
     RECT  41.544 75.821 41.562 76.397 ;
     RECT  56.736 75.821 57.87 76.397 ;
     RECT  13.644 75.773 13.662 76.925 ;
     RECT  56.736 76.397 57.51 76.925 ;
     RECT  57.456 76.925 57.51 76.973 ;
     RECT  60.696 75.821 68.166 76.973 ;
     RECT  69.48 75.821 69.498 76.973 ;
     RECT  73.152 75.821 73.17 76.973 ;
     RECT  57.492 76.973 57.51 77.069 ;
     RECT  1.116 75.821 8.334 77.741 ;
     RECT  16.02 75.821 23.238 77.741 ;
     RECT  30.888 75.821 38.142 77.741 ;
     RECT  45.792 75.821 53.046 77.741 ;
     RECT  60.696 76.973 67.95 77.741 ;
     RECT  75.6 76.013 80.982 77.741 ;
    LAYER M4 ;
     RECT  0.06 8.544 0.137 8.568 ;
     RECT  0.06 54 2.293 54.024 ;
     RECT  0.06 69.168 2.329 69.192 ;
     RECT  0.06 38.88 2.365 38.904 ;
     RECT  2.293 46.32 2.365 46.872 ;
     RECT  2.329 69.168 2.365 70.104 ;
     RECT  2.293 53.52 2.401 54.024 ;
     RECT  2.365 14.208 2.408 14.232 ;
     RECT  0.06 23.712 2.408 23.736 ;
     RECT  2.329 25.536 2.408 25.56 ;
     RECT  2.365 27.648 2.408 27.672 ;
     RECT  2.365 29.52 2.408 29.544 ;
     RECT  2.293 30.672 2.408 30.696 ;
     RECT  2.293 32.208 2.408 32.232 ;
     RECT  2.365 36.912 2.408 36.936 ;
     RECT  2.365 38.736 2.408 38.904 ;
     RECT  2.365 41.472 2.408 41.496 ;
     RECT  2.329 42.72 2.408 42.744 ;
     RECT  2.365 46.08 2.408 46.872 ;
     RECT  2.401 48.384 2.408 48.408 ;
     RECT  2.401 53.52 2.408 54.648 ;
     RECT  2.365 58.656 2.408 58.68 ;
     RECT  2.365 61.632 2.408 61.656 ;
     RECT  2.329 68.112 2.408 68.136 ;
     RECT  2.365 69.168 2.408 70.584 ;
     RECT  2.329 71.616 2.408 71.64 ;
     RECT  2.365 73.344 2.408 73.368 ;
     RECT  2.408 2.148 2.512 75.612 ;
     RECT  2.512 2.418 2.704 75.342 ;
     RECT  2.704 9.072 2.819 10.2 ;
     RECT  2.704 25.536 2.819 25.56 ;
     RECT  2.704 41.472 2.819 51.384 ;
     RECT  2.704 63.792 2.819 68.952 ;
     RECT  2.704 70.032 2.867 73.368 ;
     RECT  2.819 64.416 2.881 68.952 ;
     RECT  2.819 44.736 2.909 45 ;
     RECT  2.704 20.4 2.915 23.16 ;
     RECT  2.819 41.472 2.945 43.32 ;
     RECT  2.704 17.088 2.953 19.032 ;
     RECT  2.945 41.76 3.125 43.32 ;
     RECT  2.704 53.04 3.299 60.456 ;
     RECT  2.881 64.416 3.305 66.312 ;
     RECT  2.867 73.344 3.449 73.368 ;
     RECT  2.819 46.08 3.485 51.384 ;
     RECT  2.704 14.208 3.593 14.232 ;
     RECT  2.704 29.52 3.593 30.552 ;
     RECT  2.953 17.088 3.665 17.64 ;
     RECT  3.299 53.04 3.665 53.064 ;
     RECT  2.704 32.064 3.697 33.096 ;
     RECT  2.704 34.08 3.697 35.736 ;
     RECT  2.953 18.912 3.733 19.032 ;
     RECT  2.909 44.736 3.779 44.76 ;
     RECT  2.704 12.528 3.805 13.032 ;
     RECT  2.915 21.648 3.805 23.16 ;
     RECT  3.125 42.672 3.805 43.32 ;
     RECT  3.299 54.336 3.805 60.456 ;
     RECT  2.881 67.488 3.805 68.952 ;
     RECT  3.593 30.528 3.809 30.552 ;
     RECT  3.805 21.648 3.841 23.544 ;
     RECT  3.697 32.064 3.841 35.736 ;
     RECT  2.704 36.864 3.841 36.936 ;
     RECT  2.704 38.208 3.841 38.76 ;
     RECT  3.841 32.064 3.884 35.784 ;
     RECT  2.819 9.072 3.917 9.816 ;
     RECT  3.884 31.68 3.925 35.784 ;
     RECT  3.841 36.864 3.949 38.76 ;
     RECT  3.925 31.68 3.971 35.832 ;
     RECT  3.805 67.488 3.973 69 ;
     RECT  2.867 70.032 3.973 71.64 ;
     RECT  3.805 12.528 3.985 13.704 ;
     RECT  3.973 67.488 3.985 71.64 ;
     RECT  3.971 32.208 4.012 35.832 ;
     RECT  3.485 50.112 4.021 51.384 ;
     RECT  3.305 66.288 4.021 66.312 ;
     RECT  3.985 67.392 4.021 71.64 ;
     RECT  2.704 40.464 4.057 40.488 ;
     RECT  3.805 54.336 4.067 60.552 ;
     RECT  2.704 62.64 4.093 62.664 ;
     RECT  4.021 66.288 4.129 71.64 ;
     RECT  3.949 72.624 4.129 72.648 ;
     RECT  4.067 54.672 4.133 60.552 ;
     RECT  2.915 20.4 4.165 20.568 ;
     RECT  2.704 26.784 4.165 27.912 ;
     RECT  3.485 46.08 4.165 48.936 ;
     RECT  4.057 40.464 4.237 40.536 ;
     RECT  3.305 64.416 4.237 65.256 ;
     RECT  4.021 50.112 4.273 51.864 ;
     RECT  4.165 26.784 4.313 28.728 ;
     RECT  3.949 36.864 4.349 39.336 ;
     RECT  3.805 42.672 4.381 43.608 ;
     RECT  4.165 45.984 4.453 48.936 ;
     RECT  4.237 64.32 4.453 65.256 ;
     RECT  4.129 66.288 4.453 72.648 ;
     RECT  4.453 64.32 4.46 72.648 ;
     RECT  4.453 45.552 4.493 48.936 ;
     RECT  4.237 40.464 4.499 41.592 ;
     RECT  4.133 56.256 4.499 60.552 ;
     RECT  3.665 17.088 4.525 17.448 ;
     RECT  4.46 64.32 4.547 72.744 ;
     RECT  4.165 25.632 4.549 25.656 ;
     RECT  4.313 26.784 4.549 27.432 ;
     RECT  2.704 15.36 4.561 15.384 ;
     RECT  4.273 50.112 4.561 51.96 ;
     RECT  3.985 11.952 4.597 13.704 ;
     RECT  4.561 14.784 4.597 15.384 ;
     RECT  3.733 18.912 4.597 19.128 ;
     RECT  4.597 11.952 4.601 15.384 ;
     RECT  4.601 14.208 4.633 15.384 ;
     RECT  4.525 16.464 4.633 17.448 ;
     RECT  4.012 32.208 4.637 35.784 ;
     RECT  4.633 14.208 4.645 17.448 ;
     RECT  4.499 40.512 4.709 41.592 ;
     RECT  2.704 3.936 4.739 3.96 ;
     RECT  4.733 53.568 4.777 53.592 ;
     RECT  4.313 28.704 4.796 28.728 ;
     RECT  4.165 20.112 4.813 20.568 ;
     RECT  4.777 52.992 4.817 53.592 ;
     RECT  4.549 25.632 4.837 27.432 ;
     RECT  4.597 18.624 4.849 19.128 ;
     RECT  4.813 20.112 4.849 20.616 ;
     RECT  4.493 45.552 4.853 48.312 ;
     RECT  3.917 9.648 4.885 9.672 ;
     RECT  4.237 10.704 4.885 10.728 ;
     RECT  4.849 18.624 4.885 20.616 ;
     RECT  3.841 21.648 4.885 23.928 ;
     RECT  4.885 9.648 4.921 10.728 ;
     RECT  4.601 11.952 4.921 13.08 ;
     RECT  4.561 50.016 4.921 51.96 ;
     RECT  2.704 61.632 4.921 61.656 ;
     RECT  4.093 62.64 4.921 63.24 ;
     RECT  4.921 61.632 4.933 63.24 ;
     RECT  4.547 64.32 4.933 72.648 ;
     RECT  4.525 30.672 4.957 30.696 ;
     RECT  4.129 7.968 4.993 7.992 ;
     RECT  4.993 7.968 5.033 8.472 ;
     RECT  4.637 32.208 5.065 34.776 ;
     RECT  4.933 61.632 5.075 72.648 ;
     RECT  4.921 9.648 5.105 13.08 ;
     RECT  4.381 42.672 5.173 43.896 ;
     RECT  4.853 45.552 5.173 48.264 ;
     RECT  4.693 6.864 5.177 6.888 ;
     RECT  5.075 61.632 5.177 72.552 ;
     RECT  4.499 58.704 5.213 60.552 ;
     RECT  5.177 61.632 5.213 63.24 ;
     RECT  4.796 28.704 5.245 29.208 ;
     RECT  4.349 37.632 5.245 39.336 ;
     RECT  4.921 50.016 5.245 52.008 ;
     RECT  4.133 54.672 5.285 55.272 ;
     RECT  5.065 31.872 5.321 34.776 ;
     RECT  5.245 49.632 5.389 52.008 ;
     RECT  4.817 52.992 5.389 53.16 ;
     RECT  4.637 35.76 5.393 35.784 ;
     RECT  5.173 42.672 5.393 48.264 ;
     RECT  5.389 49.632 5.393 53.16 ;
     RECT  5.213 58.704 5.393 59.256 ;
     RECT  4.837 25.44 5.425 27.432 ;
     RECT  5.245 28.704 5.425 29.592 ;
     RECT  5.285 54.864 5.425 55.272 ;
     RECT  4.499 56.256 5.425 57.624 ;
     RECT  5.177 64.32 5.429 72.552 ;
     RECT  5.245 37.632 5.537 39.48 ;
     RECT  5.393 42.672 5.573 47.64 ;
     RECT  4.957 30.672 5.605 30.84 ;
     RECT  5.321 31.872 5.605 34.68 ;
     RECT  4.885 18.624 5.609 23.928 ;
     RECT  5.429 64.368 5.609 72.552 ;
     RECT  5.393 49.632 5.641 51.192 ;
     RECT  5.605 30.672 5.681 34.68 ;
     RECT  5.213 63.216 5.681 63.24 ;
     RECT  5.701 24.384 5.713 24.408 ;
     RECT  5.425 25.44 5.713 29.592 ;
     RECT  5.425 54.864 5.713 57.624 ;
     RECT  5.393 58.704 5.713 59.112 ;
     RECT  5.537 37.632 5.749 38.424 ;
     RECT  5.537 39.456 5.749 39.48 ;
     RECT  4.709 40.512 5.749 41.016 ;
     RECT  5.713 24.384 5.789 29.592 ;
     RECT  5.573 43.008 5.789 43.896 ;
     RECT  5.213 60.384 5.861 60.552 ;
     RECT  5.749 36.768 5.897 38.424 ;
     RECT  5.641 49.536 5.929 51.192 ;
     RECT  4.645 14.208 5.965 14.232 ;
     RECT  4.645 15.216 5.965 17.448 ;
     RECT  5.033 8.448 6.001 8.472 ;
     RECT  5.789 24.384 6.041 29.544 ;
     RECT  5.713 54.864 6.077 59.112 ;
     RECT  5.213 61.632 6.113 62.232 ;
     RECT  4.561 73.632 6.113 73.656 ;
     RECT  5.137 4.176 6.145 4.2 ;
     RECT  5.681 30.768 6.221 34.68 ;
     RECT  5.965 14.208 6.253 17.64 ;
     RECT  5.105 10.128 6.277 13.08 ;
     RECT  6.253 14.064 6.277 17.64 ;
     RECT  6.001 7.968 6.293 8.472 ;
     RECT  5.897 36.768 6.293 38.328 ;
     RECT  5.393 52.176 6.325 53.16 ;
     RECT  6.221 30.816 6.329 34.68 ;
     RECT  5.609 64.848 6.433 72.552 ;
     RECT  6.277 10.128 6.437 17.64 ;
     RECT  6.433 35.76 6.505 35.784 ;
     RECT  6.293 36.768 6.505 37.944 ;
     RECT  6.433 64.848 6.545 72.984 ;
     RECT  6.329 34.08 6.613 34.68 ;
     RECT  6.505 35.76 6.613 37.944 ;
     RECT  6.545 65.232 6.689 72.984 ;
     RECT  5.573 45.264 6.757 47.64 ;
     RECT  5.929 48.912 6.757 51.192 ;
     RECT  5.749 39.456 6.764 41.016 ;
     RECT  6.613 34.08 6.797 37.944 ;
     RECT  5.789 43.008 6.805 43.032 ;
     RECT  6.757 44.352 6.805 51.192 ;
     RECT  6.805 43.008 6.812 51.192 ;
     RECT  6.325 52.176 6.812 54.12 ;
     RECT  6.437 14.064 6.829 17.64 ;
     RECT  5.609 18.624 6.829 23.16 ;
     RECT  6.812 43.008 6.829 54.12 ;
     RECT  5.861 60.528 6.829 60.552 ;
     RECT  6.764 39.456 6.865 41.064 ;
     RECT  6.829 14.064 7.045 23.16 ;
     RECT  6.829 60.528 7.225 60.648 ;
     RECT  6.113 61.68 7.225 62.232 ;
     RECT  6.437 10.128 7.261 13.032 ;
     RECT  6.797 35.52 7.297 37.944 ;
     RECT  7.081 64.128 7.297 64.152 ;
     RECT  6.001 6.816 7.333 6.84 ;
     RECT  7.297 35.52 7.333 37.992 ;
     RECT  6.077 55.2 7.333 59.112 ;
     RECT  7.225 60.528 7.333 62.232 ;
     RECT  7.261 9.792 7.441 13.032 ;
     RECT  7.045 14.064 7.441 23.4 ;
     RECT  6.145 4.032 7.477 4.2 ;
     RECT  6.041 24.384 7.549 25.8 ;
     RECT  6.041 26.88 7.549 29.544 ;
     RECT  7.333 55.2 7.729 62.232 ;
     RECT  7.297 63.744 7.729 64.152 ;
     RECT  6.689 65.232 7.729 72.648 ;
     RECT  7.477 3.408 7.808 4.2 ;
     RECT  7.333 6.096 7.808 6.84 ;
     RECT  6.293 8.448 7.808 8.472 ;
     RECT  7.441 9.792 7.808 23.4 ;
     RECT  7.549 24.384 7.808 29.544 ;
     RECT  6.329 30.816 7.808 32.568 ;
     RECT  6.797 34.08 7.808 34.392 ;
     RECT  7.333 35.52 7.808 38.184 ;
     RECT  6.865 39.456 7.808 41.544 ;
     RECT  6.829 42.576 7.808 54.12 ;
     RECT  7.729 55.2 7.808 64.152 ;
     RECT  7.729 65.232 7.808 72.84 ;
     RECT  7.573 74.112 7.808 74.136 ;
     RECT  7.808 2.148 7.912 75.612 ;
     RECT  7.912 2.418 8.104 75.342 ;
     RECT  8.104 3.408 8.201 33.096 ;
     RECT  8.104 39.312 8.243 41.928 ;
     RECT  8.243 39.312 8.309 41.16 ;
     RECT  8.104 64.128 8.339 66.36 ;
     RECT  8.201 3.408 8.345 32.568 ;
     RECT  8.345 3.408 8.353 28.296 ;
     RECT  8.104 34.08 8.381 38.184 ;
     RECT  8.104 55.488 8.425 63.096 ;
     RECT  8.425 55.488 8.453 57.336 ;
     RECT  8.381 34.08 8.525 37.944 ;
     RECT  8.104 43.008 8.531 51.576 ;
     RECT  8.353 5.808 8.553 28.296 ;
     RECT  8.425 58.704 8.561 63.096 ;
     RECT  8.561 61.344 8.633 63.096 ;
     RECT  8.531 43.536 8.771 51.576 ;
     RECT  8.104 72.432 8.771 72.84 ;
     RECT  8.633 62.976 8.849 63.096 ;
     RECT  8.353 3.408 8.957 4.488 ;
     RECT  8.104 75.264 8.989 75.342 ;
     RECT  8.561 58.704 9.029 60.312 ;
     RECT  8.633 61.344 9.065 61.992 ;
     RECT  8.989 75.264 9.073 75.816 ;
     RECT  8.104 67.44 9.097 71.352 ;
     RECT  8.771 72.432 9.097 72.6 ;
     RECT  8.345 29.52 9.107 32.568 ;
     RECT  8.771 43.536 9.107 51.528 ;
     RECT  8.553 6.864 9.137 28.296 ;
     RECT  8.309 39.312 9.205 40.296 ;
     RECT  9.205 38.976 9.245 40.296 ;
     RECT  9.107 43.536 9.245 48.552 ;
     RECT  9.097 67.44 9.251 72.6 ;
     RECT  8.525 34.08 9.281 37.656 ;
     RECT  9.107 32.448 9.349 32.568 ;
     RECT  9.281 34.08 9.349 35.16 ;
     RECT  9.245 38.976 9.349 40.056 ;
     RECT  8.849 63.024 9.353 63.096 ;
     RECT  9.251 67.44 9.353 71.4 ;
     RECT  8.104 73.968 9.389 73.992 ;
     RECT  8.453 55.632 9.421 57.336 ;
     RECT  8.339 64.368 9.421 66.36 ;
     RECT  9.353 67.44 9.421 71.208 ;
     RECT  9.107 29.52 9.425 31.224 ;
     RECT  9.137 13.92 9.461 28.296 ;
     RECT  9.461 26.88 9.497 28.296 ;
     RECT  9.349 32.448 9.497 35.16 ;
     RECT  9.029 58.704 9.529 59.928 ;
     RECT  8.957 3.984 9.548 4.488 ;
     RECT  8.553 5.808 9.548 5.832 ;
     RECT  9.425 30.144 9.569 31.224 ;
     RECT  9.107 49.536 9.569 51.528 ;
     RECT  9.569 30.432 9.577 31.224 ;
     RECT  9.205 54.624 9.637 54.648 ;
     RECT  9.421 55.632 9.637 57.576 ;
     RECT  9.245 43.776 9.641 48.552 ;
     RECT  9.073 75.264 9.673 75.288 ;
     RECT  9.497 32.448 9.683 34.344 ;
     RECT  9.637 54.624 9.683 57.576 ;
     RECT  9.683 56.544 9.781 57.576 ;
     RECT  9.529 58.656 9.781 59.928 ;
     RECT  9.548 3.984 9.853 5.832 ;
     RECT  9.137 6.864 9.853 12.888 ;
     RECT  9.5 52.944 9.997 52.968 ;
     RECT  9.781 56.544 9.997 59.928 ;
     RECT  9.065 61.344 9.997 61.416 ;
     RECT  9.421 64.368 9.997 71.208 ;
     RECT  9.997 56.544 10.001 61.416 ;
     RECT  9.281 36.144 10.177 37.656 ;
     RECT  9.349 38.64 10.177 40.056 ;
     RECT  9.683 54.624 10.177 55.272 ;
     RECT  9.673 74.304 10.285 75.288 ;
     RECT  9.641 43.776 10.289 46.104 ;
     RECT  9.997 52.704 10.321 52.968 ;
     RECT  10.141 62.4 10.357 62.424 ;
     RECT  9.997 63.792 10.357 71.208 ;
     RECT  9.853 3.984 10.433 12.888 ;
     RECT  10.285 74.304 10.451 75.816 ;
     RECT  10.177 36.144 10.453 40.056 ;
     RECT  10.321 52.704 10.465 53.256 ;
     RECT  10.001 56.736 10.465 61.416 ;
     RECT  10.357 62.4 10.465 71.208 ;
     RECT  9.497 26.88 10.501 28.104 ;
     RECT  10.453 35.424 10.537 40.056 ;
     RECT  10.537 35.424 10.54 41.016 ;
     RECT  10.465 56.736 10.541 71.208 ;
     RECT  9.577 31.008 10.549 31.224 ;
     RECT  10.54 36.144 10.609 41.016 ;
     RECT  10.549 30.72 10.645 31.224 ;
     RECT  9.683 32.448 10.645 33.096 ;
     RECT  10.645 30.72 10.681 33.096 ;
     RECT  9.683 34.08 10.681 34.344 ;
     RECT  9.569 50.16 10.681 51.528 ;
     RECT  10.465 52.704 10.681 53.4 ;
     RECT  9.461 13.92 10.717 25.848 ;
     RECT  10.501 26.88 10.717 28.44 ;
     RECT  10.681 30.72 10.789 34.344 ;
     RECT  9.641 47.424 10.789 48.552 ;
     RECT  9.251 72.576 10.789 72.6 ;
     RECT  10.789 30.72 10.835 34.776 ;
     RECT  10.451 74.304 10.837 75.576 ;
     RECT  10.835 32.448 10.865 34.776 ;
     RECT  10.177 54.384 10.865 55.272 ;
     RECT  10.789 72.576 10.883 72.936 ;
     RECT  10.865 54.384 10.901 54.984 ;
     RECT  10.609 36.144 10.973 41.112 ;
     RECT  10.837 74.016 10.973 75.576 ;
     RECT  9.529 42.48 11.005 42.504 ;
     RECT  10.789 47.424 11.005 49.08 ;
     RECT  10.433 4.032 11.041 12.888 ;
     RECT  10.717 13.92 11.041 28.44 ;
     RECT  10.835 30.72 11.113 31.128 ;
     RECT  11.005 42.144 11.113 42.504 ;
     RECT  10.865 33.216 11.153 34.776 ;
     RECT  11.041 4.032 11.329 28.44 ;
     RECT  11.113 41.232 11.365 42.504 ;
     RECT  10.289 43.776 11.365 45.864 ;
     RECT  10.541 56.736 11.365 70.968 ;
     RECT  11.005 47.328 11.437 49.08 ;
     RECT  10.681 50.16 11.437 53.4 ;
     RECT  11.113 30.288 11.441 31.128 ;
     RECT  10.883 72.576 11.473 72.888 ;
     RECT  11.365 55.968 11.513 70.968 ;
     RECT  10.973 74.304 11.513 75.576 ;
     RECT  11.329 4.032 11.516 28.68 ;
     RECT  11.153 33.264 11.581 34.776 ;
     RECT  10.973 36.144 11.581 40.104 ;
     RECT  11.516 3.216 11.603 28.68 ;
     RECT  11.473 72.24 11.693 72.888 ;
     RECT  11.513 66 11.725 70.968 ;
     RECT  11.437 47.04 11.765 53.4 ;
     RECT  11.365 41.232 11.797 45.864 ;
     RECT  11.765 47.04 11.797 51.288 ;
     RECT  11.797 41.232 11.801 51.288 ;
     RECT  11.801 42.48 11.837 51.288 ;
     RECT  11.603 3.696 11.905 28.68 ;
     RECT  10.901 54.384 11.981 54.792 ;
     RECT  11.513 55.968 11.987 64.728 ;
     RECT  11.513 75.264 12.013 75.576 ;
     RECT  11.581 33.264 12.121 40.104 ;
     RECT  11.801 41.232 12.121 41.496 ;
     RECT  11.725 66 12.121 71.064 ;
     RECT  11.693 72.24 12.121 72.84 ;
     RECT  11.765 52.512 12.133 53.4 ;
     RECT  11.981 54.384 12.133 54.408 ;
     RECT  11.905 3.696 12.157 29.016 ;
     RECT  11.441 30.672 12.193 31.128 ;
     RECT  12.013 75.264 12.265 75.816 ;
     RECT  12.193 30.672 12.553 31.56 ;
     RECT  12.121 33.264 12.553 41.496 ;
     RECT  12.265 75.264 12.563 76.392 ;
     RECT  12.121 66 12.661 72.84 ;
     RECT  12.157 3.696 12.733 29.592 ;
     RECT  11.987 59.808 12.733 64.728 ;
     RECT  12.563 75.264 12.803 75.816 ;
     RECT  12.733 59.808 12.877 64.92 ;
     RECT  12.661 66 12.877 73.56 ;
     RECT  12.553 30.672 12.913 41.496 ;
     RECT  12.133 52.512 12.913 54.408 ;
     RECT  12.913 30.624 12.985 41.496 ;
     RECT  11.837 42.816 12.985 51.288 ;
     RECT  12.913 52.464 12.985 54.408 ;
     RECT  11.987 55.968 12.985 58.776 ;
     RECT  12.877 59.808 12.985 73.56 ;
     RECT  12.733 3.696 13.093 29.64 ;
     RECT  13.093 3.408 13.208 29.64 ;
     RECT  12.985 30.624 13.208 54.408 ;
     RECT  12.985 55.968 13.208 73.56 ;
     RECT  12.803 75.264 13.208 75.768 ;
     RECT  13.208 2.148 13.235 75.768 ;
     RECT  13.235 2.148 13.312 75.72 ;
     RECT  13.312 2.418 13.475 75.72 ;
     RECT  13.475 2.418 13.504 75.342 ;
     RECT  13.504 32.496 13.637 63.624 ;
     RECT  13.504 64.704 13.66 73.56 ;
     RECT  13.637 34.992 13.673 63.624 ;
     RECT  13.504 3.648 13.715 31.416 ;
     RECT  13.633 76.896 13.717 76.92 ;
     RECT  13.715 29.616 13.745 31.416 ;
     RECT  13.673 34.992 13.853 43.32 ;
     RECT  13.637 32.496 13.889 33.96 ;
     RECT  13.745 30 14.033 31.416 ;
     RECT  13.66 73.248 14.285 73.56 ;
     RECT  13.504 75.264 14.497 75.288 ;
     RECT  13.853 35.04 14.501 43.32 ;
     RECT  14.285 73.248 14.501 73.272 ;
     RECT  14.033 30 14.609 30.648 ;
     RECT  14.501 35.136 14.785 43.32 ;
     RECT  13.673 44.304 14.785 63.624 ;
     RECT  13.715 3.648 14.965 28.584 ;
     RECT  14.924 31.776 14.965 31.8 ;
     RECT  13.889 32.784 14.965 33.96 ;
     RECT  14.965 3.024 15.001 28.584 ;
     RECT  13.66 64.704 15.109 71.736 ;
     RECT  14.497 75.264 15.121 75.816 ;
     RECT  14.609 30.144 15.217 30.648 ;
     RECT  14.965 31.776 15.217 33.96 ;
     RECT  15.001 3.024 15.473 29.016 ;
     RECT  15.109 64.704 15.689 72.264 ;
     RECT  15.473 3.936 15.865 29.016 ;
     RECT  15.217 30.144 15.865 33.96 ;
     RECT  15.121 75.264 15.869 75.288 ;
     RECT  15.689 67.536 15.905 72.264 ;
     RECT  15.865 3.936 16.049 33.96 ;
     RECT  16.009 2.832 16.093 2.856 ;
     RECT  14.785 35.136 16.265 63.624 ;
     RECT  16.265 35.136 16.337 51.72 ;
     RECT  16.337 35.136 16.693 39.912 ;
     RECT  16.049 3.936 16.801 33.096 ;
     RECT  15.689 64.704 16.945 66.552 ;
     RECT  15.905 67.536 16.945 71.832 ;
     RECT  16.265 52.704 16.981 63.624 ;
     RECT  16.945 64.704 16.981 71.832 ;
     RECT  16.693 34.896 17.053 39.912 ;
     RECT  16.801 3.12 17.089 33.096 ;
     RECT  17.053 34.08 17.089 39.912 ;
     RECT  16.337 40.944 17.305 51.72 ;
     RECT  16.981 52.704 17.305 71.832 ;
     RECT  17.305 40.944 17.561 71.832 ;
     RECT  17.089 3.12 17.593 39.912 ;
     RECT  17.561 40.944 17.593 53.544 ;
     RECT  17.561 54.576 17.665 71.832 ;
     RECT  17.593 3.12 18.313 53.544 ;
     RECT  18.313 3.024 18.608 53.544 ;
     RECT  17.665 54.576 18.608 72.264 ;
     RECT  18.385 74.16 18.608 74.184 ;
     RECT  18.608 2.148 18.712 75.612 ;
     RECT  18.712 2.418 18.904 75.342 ;
     RECT  18.904 73.776 19.469 74.568 ;
     RECT  18.904 43.392 19.865 46.632 ;
     RECT  19.865 43.536 19.933 46.632 ;
     RECT  18.904 48.144 19.933 72.312 ;
     RECT  19.933 43.536 20.009 72.312 ;
     RECT  18.904 3.024 20.045 42.216 ;
     RECT  20.045 3.024 20.297 35.784 ;
     RECT  19.469 74.064 20.585 74.568 ;
     RECT  20.297 3.024 20.677 34.536 ;
     RECT  20.677 2.832 20.764 34.536 ;
     RECT  20.585 74.064 20.801 74.088 ;
     RECT  20.009 43.776 21.013 72.312 ;
     RECT  20.297 35.52 21.229 35.784 ;
     RECT  20.045 36.864 21.229 42.216 ;
     RECT  21.229 35.52 21.341 42.216 ;
     RECT  20.764 3.024 21.377 34.536 ;
     RECT  21.013 43.2 21.661 72.312 ;
     RECT  21.661 43.2 21.697 72.888 ;
     RECT  21.697 43.2 21.971 73.608 ;
     RECT  21.377 3.408 22.021 34.536 ;
     RECT  21.341 35.52 22.021 41.112 ;
     RECT  21.341 42.192 22.345 42.216 ;
     RECT  21.971 43.2 22.345 58.968 ;
     RECT  22.021 3.408 22.597 41.112 ;
     RECT  22.597 3.36 22.601 41.112 ;
     RECT  22.601 3.36 22.777 40.824 ;
     RECT  22.777 3.12 22.781 40.824 ;
     RECT  21.971 60.096 22.957 73.608 ;
     RECT  22.345 42.192 23.461 58.968 ;
     RECT  22.957 60.096 23.461 73.656 ;
     RECT  22.781 3.12 23.569 40.584 ;
     RECT  23.389 75.264 23.653 75.288 ;
     RECT  23.653 75.264 23.852 75.816 ;
     RECT  23.461 42.192 23.893 73.656 ;
     RECT  23.852 74.64 23.893 75.816 ;
     RECT  23.893 42.192 23.929 75.816 ;
     RECT  23.569 3.024 24.008 40.584 ;
     RECT  23.929 41.76 24.008 75.816 ;
     RECT  24.008 2.148 24.112 75.816 ;
     RECT  24.112 2.418 24.304 75.816 ;
     RECT  24.304 73.632 24.445 75.816 ;
     RECT  24.445 75.792 24.937 75.816 ;
     RECT  24.937 75.792 25.139 76.392 ;
     RECT  24.445 73.632 25.301 74.568 ;
     RECT  24.304 2.88 25.337 72.456 ;
     RECT  25.139 75.792 25.441 75.816 ;
     RECT  25.337 59.952 25.475 72.456 ;
     RECT  25.301 73.632 25.585 73.656 ;
     RECT  25.337 2.88 25.661 58.824 ;
     RECT  25.661 3.024 25.769 58.824 ;
     RECT  25.585 73.488 26.129 73.656 ;
     RECT  25.769 3.12 26.243 58.824 ;
     RECT  25.475 59.952 26.345 72.312 ;
     RECT  26.345 67.68 26.417 72.312 ;
     RECT  26.417 67.824 26.593 72.312 ;
     RECT  26.243 53.808 26.636 58.824 ;
     RECT  26.345 59.952 26.636 66.648 ;
     RECT  26.243 3.12 26.845 52.104 ;
     RECT  26.845 3.024 26.957 52.104 ;
     RECT  26.129 73.632 27.061 73.656 ;
     RECT  25.441 75.264 27.241 75.816 ;
     RECT  26.636 53.808 27.313 66.648 ;
     RECT  26.593 67.824 27.313 72.408 ;
     RECT  27.241 75.264 27.443 76.392 ;
     RECT  26.957 3.072 27.548 52.104 ;
     RECT  27.548 3.072 27.635 52.488 ;
     RECT  27.443 75.792 27.683 76.392 ;
     RECT  27.313 53.616 27.829 66.648 ;
     RECT  27.313 67.824 27.829 72.6 ;
     RECT  27.829 53.616 27.961 72.6 ;
     RECT  27.061 73.632 27.961 74.28 ;
     RECT  27.961 53.616 27.965 74.28 ;
     RECT  27.965 73.248 27.997 74.28 ;
     RECT  27.965 53.616 28.141 72.264 ;
     RECT  27.997 73.248 28.429 74.616 ;
     RECT  27.635 3.072 28.717 52.008 ;
     RECT  28.141 53.28 28.933 72.264 ;
     RECT  28.429 73.248 28.933 74.712 ;
     RECT  27.683 75.792 29.075 75.912 ;
     RECT  28.717 3.072 29.293 52.248 ;
     RECT  28.933 53.28 29.293 74.712 ;
     RECT  29.293 3.072 29.408 74.712 ;
     RECT  29.075 75.792 29.408 75.816 ;
     RECT  29.408 2.148 29.512 75.816 ;
     RECT  29.512 2.418 29.704 75.816 ;
     RECT  29.704 3.072 29.765 74.136 ;
     RECT  29.765 3.072 29.801 72.792 ;
     RECT  29.765 74.112 30.305 74.136 ;
     RECT  29.801 3.072 30.629 72.744 ;
     RECT  29.704 75.264 30.737 75.816 ;
     RECT  30.737 75.264 30.773 75.288 ;
     RECT  30.629 3.072 30.809 72.312 ;
     RECT  30.809 3.312 31.957 72.312 ;
     RECT  31.309 73.488 31.957 73.512 ;
     RECT  31.957 3.312 32.321 73.512 ;
     RECT  32.321 56.736 32.609 73.512 ;
     RECT  32.321 3.312 33.217 55.656 ;
     RECT  32.609 56.736 33.617 73.224 ;
     RECT  33.617 57.12 33.653 73.224 ;
     RECT  33.217 3.024 33.685 55.656 ;
     RECT  33.685 2.784 34.009 55.656 ;
     RECT  34.333 74.4 34.645 74.424 ;
     RECT  34.009 2.784 34.808 55.752 ;
     RECT  33.653 57.12 34.808 72.024 ;
     RECT  33.653 73.008 34.808 73.224 ;
     RECT  34.645 74.4 34.808 75.384 ;
     RECT  34.808 2.148 34.912 75.612 ;
     RECT  34.912 2.418 35.104 75.342 ;
     RECT  35.104 62.16 35.417 73.032 ;
     RECT  35.104 74.4 35.561 74.712 ;
     RECT  35.516 77.664 35.603 77.688 ;
     RECT  35.561 74.688 35.893 74.712 ;
     RECT  35.104 2.784 36.097 61.08 ;
     RECT  35.417 62.16 36.097 72.84 ;
     RECT  36.097 2.784 36.497 72.84 ;
     RECT  36.497 3.168 36.961 72.84 ;
     RECT  36.961 3.168 37.292 72.888 ;
     RECT  36.925 74.448 37.292 74.472 ;
     RECT  37.292 3.168 37.379 74.472 ;
     RECT  37.379 3.168 37.825 73.368 ;
     RECT  37.379 74.448 38.117 74.472 ;
     RECT  38.077 76.944 38.387 76.968 ;
     RECT  38.509 75.264 38.797 75.288 ;
     RECT  37.825 3.072 38.837 73.368 ;
     RECT  38.797 75.264 38.881 75.816 ;
     RECT  38.837 73.344 38.981 73.368 ;
     RECT  38.837 3.072 39.089 72.312 ;
     RECT  38.881 75.264 39.253 75.288 ;
     RECT  39.089 3.168 39.841 72.312 ;
     RECT  39.253 74.448 39.973 75.288 ;
     RECT  39.973 74.448 40.057 75.432 ;
     RECT  40.057 73.824 40.165 75.432 ;
     RECT  39.841 3.168 40.208 72.408 ;
     RECT  40.165 73.824 40.208 75.768 ;
     RECT  40.208 2.148 40.259 75.768 ;
     RECT  40.259 2.148 40.312 75.72 ;
     RECT  40.312 2.418 40.504 75.72 ;
     RECT  40.504 2.88 40.565 73.56 ;
     RECT  40.565 2.88 40.853 72.984 ;
     RECT  40.504 75.264 41.281 75.72 ;
     RECT  41.281 75.264 41.533 75.816 ;
     RECT  40.853 2.976 41.569 72.984 ;
     RECT  41.497 74.064 41.569 74.088 ;
     RECT  41.569 2.976 41.651 74.088 ;
     RECT  41.533 75.264 41.651 76.392 ;
     RECT  41.651 73.728 41.717 74.088 ;
     RECT  41.651 75.264 42.131 75.816 ;
     RECT  41.651 2.976 42.365 72.408 ;
     RECT  41.717 74.064 42.545 74.088 ;
     RECT  42.365 3.024 43.481 72.408 ;
     RECT  43.481 3.024 43.621 71.928 ;
     RECT  43.297 73.536 43.729 73.56 ;
     RECT  43.729 72.912 44.017 73.56 ;
     RECT  42.131 75.744 44.128 75.816 ;
     RECT  44.017 72.912 44.195 74.136 ;
     RECT  44.128 75.696 44.341 75.816 ;
     RECT  43.621 2.88 44.665 71.928 ;
     RECT  44.195 72.912 44.665 73.368 ;
     RECT  44.341 75.264 44.921 75.816 ;
     RECT  44.665 2.88 45.457 73.368 ;
     RECT  45.457 2.88 45.608 74.136 ;
     RECT  44.921 75.264 45.608 75.768 ;
     RECT  45.608 2.148 45.628 75.768 ;
     RECT  45.628 2.148 45.712 75.612 ;
     RECT  45.712 2.418 45.904 75.342 ;
     RECT  45.904 73.344 46.073 74.04 ;
     RECT  45.904 3.216 46.787 72.024 ;
     RECT  46.787 3.408 47.185 72.024 ;
     RECT  46.073 74.016 47.509 74.04 ;
     RECT  47.429 0.096 47.513 0.12 ;
     RECT  47.185 3.408 47.761 72.84 ;
     RECT  47.509 74.016 48.125 74.376 ;
     RECT  47.761 3.072 48.421 72.84 ;
     RECT  48.421 3.072 48.62 72.936 ;
     RECT  48.125 74.016 48.62 74.136 ;
     RECT  48.869 1.728 48.953 1.752 ;
     RECT  48.62 3.072 49.753 74.136 ;
     RECT  49.753 3.072 49.849 73.32 ;
     RECT  50.252 1.104 50.339 1.128 ;
     RECT  49.849 2.544 50.425 73.32 ;
     RECT  50.425 2.256 50.725 73.32 ;
     RECT  50.497 74.736 50.821 74.76 ;
     RECT  50.725 2.256 51.008 73.704 ;
     RECT  50.821 74.736 51.008 75.048 ;
     RECT  51.008 2.148 51.112 75.612 ;
     RECT  51.112 2.16 51.304 75.342 ;
     RECT  51.304 2.16 51.905 74.088 ;
     RECT  51.304 75.264 52.451 75.288 ;
     RECT  51.905 2.256 52.499 74.088 ;
     RECT  40.741 77.616 52.873 77.64 ;
     RECT  52.499 2.496 53.057 74.088 ;
     RECT  53.057 2.496 53.129 73.512 ;
     RECT  52.981 0.096 53.219 0.12 ;
     RECT  53.129 2.544 53.411 73.512 ;
     RECT  53.411 2.544 53.417 2.808 ;
     RECT  52.873 76.944 53.507 77.64 ;
     RECT  53.411 3.84 53.669 73.512 ;
     RECT  53.669 57.072 53.849 73.512 ;
     RECT  53.417 2.544 54.209 2.616 ;
     RECT  53.221 75.792 54.413 75.816 ;
     RECT  54.209 2.544 54.593 2.568 ;
     RECT  53.849 60.624 54.601 73.512 ;
     RECT  54.413 75.744 54.613 75.816 ;
     RECT  54.593 1.728 54.677 2.568 ;
     RECT  54.613 75.552 54.7 75.816 ;
     RECT  53.669 3.84 54.757 55.896 ;
     RECT  53.849 57.072 54.757 59.64 ;
     RECT  54.677 2.544 54.857 2.568 ;
     RECT  54.7 75.696 55.181 75.816 ;
     RECT  54.757 3.84 55.249 59.64 ;
     RECT  54.601 60.624 55.249 74.04 ;
     RECT  55.249 3.84 55.285 74.04 ;
     RECT  55.285 3.84 55.321 74.472 ;
     RECT  55.321 3.84 55.393 74.568 ;
     RECT  55.393 3.84 55.397 74.664 ;
     RECT  55.397 3.84 55.429 72.84 ;
     RECT  55.397 74.448 55.789 74.664 ;
     RECT  55.429 3.168 56.005 72.84 ;
     RECT  55.933 0.576 56.099 0.6 ;
     RECT  56.005 2.832 56.408 72.84 ;
     RECT  55.789 74.448 56.408 74.712 ;
     RECT  55.181 75.744 56.408 75.816 ;
     RECT  53.507 77.616 56.485 77.64 ;
     RECT  56.408 2.148 56.704 75.816 ;
     RECT  56.485 76.896 56.765 77.64 ;
     RECT  56.704 3.024 56.837 73.56 ;
     RECT  56.704 74.592 56.837 74.616 ;
     RECT  57.445 1.728 57.529 1.752 ;
     RECT  56.704 75.792 57.557 75.816 ;
     RECT  56.837 3.024 57.593 72.84 ;
     RECT  56.765 76.944 57.841 77.64 ;
     RECT  57.841 76.368 57.923 77.64 ;
     RECT  57.923 76.368 58.163 76.392 ;
     RECT  58.237 75.264 58.403 75.288 ;
     RECT  57.593 3.024 58.669 43.656 ;
     RECT  57.593 44.736 58.669 72.84 ;
     RECT  58.669 3.024 58.705 72.84 ;
     RECT  58.877 0.576 58.961 0.6 ;
     RECT  58.705 3.024 59.137 72.936 ;
     RECT  59.137 2.832 59.213 72.936 ;
     RECT  59.213 2.832 59.221 72.072 ;
     RECT  59.221 2.736 59.321 72.072 ;
     RECT  59.425 74.64 59.645 74.664 ;
     RECT  58.597 75.744 59.741 75.816 ;
     RECT  59.641 73.488 59.987 73.512 ;
     RECT  59.321 2.832 60.253 72.072 ;
     RECT  59.741 75.696 60.275 75.816 ;
     RECT  60.253 2.832 60.293 72.84 ;
     RECT  60.317 1.728 60.401 1.752 ;
     RECT  60.428 75.264 60.515 75.288 ;
     RECT  60.293 3.024 60.949 72.84 ;
     RECT  60.613 74.112 60.949 74.136 ;
     RECT  61.765 1.728 61.808 1.752 ;
     RECT  60.949 3.024 61.808 74.136 ;
     RECT  61.808 1.728 61.849 75.612 ;
     RECT  61.849 2.148 61.912 75.612 ;
     RECT  61.912 2.418 62.104 75.342 ;
     RECT  62.104 3.024 62.741 63.912 ;
     RECT  62.741 3.024 62.885 55.752 ;
     RECT  62.104 64.944 62.921 73.368 ;
     RECT  62.921 64.944 63.065 72.456 ;
     RECT  63.089 73.536 63.173 73.56 ;
     RECT  62.741 56.784 63.241 63.912 ;
     RECT  63.065 64.944 63.241 72.312 ;
     RECT  63.197 1.728 63.281 1.752 ;
     RECT  62.885 50.112 63.641 55.752 ;
     RECT  62.885 3.024 63.961 48.792 ;
     RECT  63.641 50.112 63.965 55.56 ;
     RECT  63.965 50.112 64.037 55.224 ;
     RECT  63.961 3.024 64.069 48.984 ;
     RECT  64.037 50.112 64.069 53.112 ;
     RECT  64.565 1.728 64.649 1.752 ;
     RECT  64.069 3.024 64.835 53.112 ;
     RECT  63.241 56.784 64.861 72.312 ;
     RECT  64.835 3.072 64.901 53.112 ;
     RECT  64.901 3.36 65.045 53.112 ;
     RECT  64.861 56.64 65.113 72.312 ;
     RECT  65.045 46.032 65.221 53.112 ;
     RECT  64.037 54.336 65.221 55.224 ;
     RECT  65.113 56.64 65.267 72.936 ;
     RECT  65.221 46.032 65.617 55.224 ;
     RECT  65.267 56.64 65.617 72.456 ;
     RECT  57.923 77.616 65.621 77.64 ;
     RECT  65.113 74.112 65.837 74.136 ;
     RECT  65.617 46.032 66.013 72.456 ;
     RECT  66.005 1.728 66.089 1.752 ;
     RECT  65.045 3.36 66.193 44.088 ;
     RECT  66.013 45.552 66.265 72.456 ;
     RECT  66.265 45.552 66.373 72.792 ;
     RECT  66.193 3.36 66.805 44.472 ;
     RECT  66.373 45.552 66.805 73.56 ;
     RECT  66.805 3.36 66.985 73.56 ;
     RECT  66.985 2.784 67.208 73.56 ;
     RECT  67.208 2.148 67.312 75.612 ;
     RECT  67.312 2.418 67.504 75.342 ;
     RECT  67.477 0.096 67.565 0.12 ;
     RECT  67.504 2.784 67.781 73.56 ;
     RECT  67.781 48.384 67.817 73.56 ;
     RECT  67.817 48.384 68.105 72.984 ;
     RECT  67.957 76.896 68.137 76.92 ;
     RECT  67.781 2.784 68.321 47.16 ;
     RECT  68.137 76.896 68.435 76.968 ;
     RECT  68.321 4.464 68.537 47.16 ;
     RECT  68.435 76.896 68.627 76.92 ;
     RECT  68.537 4.992 68.789 40.44 ;
     RECT  68.105 72.864 68.789 72.984 ;
     RECT  68.105 48.384 68.825 71.832 ;
     RECT  68.537 41.712 68.828 47.16 ;
     RECT  68.825 48.384 68.828 70.824 ;
     RECT  68.713 1.728 68.963 1.752 ;
     RECT  68.321 2.784 68.969 3.48 ;
     RECT  68.789 5.76 69.041 40.44 ;
     RECT  68.789 72.864 69.145 72.888 ;
     RECT  68.825 71.808 69.149 71.832 ;
     RECT  68.828 41.712 69.155 70.824 ;
     RECT  69.145 72.816 69.289 72.888 ;
     RECT  68.969 3.264 69.325 3.48 ;
     RECT  67.504 75.264 69.577 75.288 ;
     RECT  69.469 76.944 69.587 76.968 ;
     RECT  69.041 5.808 69.689 40.44 ;
     RECT  69.155 41.712 69.761 53.112 ;
     RECT  69.289 72.384 70.069 72.888 ;
     RECT  69.689 5.808 70.125 40.056 ;
     RECT  70.069 72.384 70.157 72.984 ;
     RECT  70.117 1.728 70.225 1.752 ;
     RECT  69.325 3.264 70.225 3.816 ;
     RECT  69.155 54.336 70.261 70.824 ;
     RECT  70.157 72.384 70.261 72.84 ;
     RECT  70.225 1.728 70.355 3.816 ;
     RECT  70.355 2.496 70.405 3.816 ;
     RECT  70.405 2.496 70.645 4.536 ;
     RECT  70.125 5.664 70.645 40.056 ;
     RECT  69.761 42 70.657 53.112 ;
     RECT  70.261 54.336 70.657 72.84 ;
     RECT  70.657 42 70.801 72.84 ;
     RECT  70.801 41.952 70.841 72.84 ;
     RECT  70.645 2.496 71.197 40.056 ;
     RECT  69.577 75.264 71.219 75.816 ;
     RECT  70.841 41.952 71.267 62.184 ;
     RECT  71.197 2.496 71.273 40.104 ;
     RECT  70.841 63.552 71.381 72.84 ;
     RECT  71.273 2.496 71.417 37.032 ;
     RECT  71.417 2.496 71.489 4.536 ;
     RECT  71.273 38.208 71.593 40.104 ;
     RECT  71.267 41.952 71.593 59.304 ;
     RECT  71.521 1.728 71.795 1.752 ;
     RECT  71.267 60.624 71.893 62.184 ;
     RECT  71.381 63.792 72.169 72.84 ;
     RECT  71.219 75.264 72.284 75.336 ;
     RECT  71.417 5.808 72.457 37.032 ;
     RECT  72.457 5.808 72.493 37.08 ;
     RECT  72.284 75.264 72.524 75.432 ;
     RECT  71.489 3.312 72.608 4.536 ;
     RECT  72.493 5.808 72.608 37.176 ;
     RECT  71.593 38.208 72.608 59.304 ;
     RECT  71.893 60.624 72.608 62.664 ;
     RECT  72.169 63.792 72.608 73.032 ;
     RECT  71.629 74.064 72.608 74.088 ;
     RECT  72.524 75.264 72.608 75.768 ;
     RECT  72.608 2.148 72.904 75.768 ;
     RECT  72.904 3.36 72.965 44.664 ;
     RECT  72.904 75.264 73.033 75.768 ;
     RECT  72.965 3.36 73.037 6.408 ;
     RECT  73.037 3.408 73.145 6.408 ;
     RECT  72.904 45.696 73.145 58.776 ;
     RECT  73.145 3.6 73.181 6.408 ;
     RECT  72.961 1.728 73.235 1.752 ;
     RECT  73.145 45.696 73.276 58.68 ;
     RECT  73.276 45.696 73.397 45.72 ;
     RECT  73.033 75.264 73.523 75.816 ;
     RECT  72.904 60.624 73.721 72.744 ;
     RECT  73.276 46.8 73.793 58.68 ;
     RECT  73.181 3.84 73.969 6.408 ;
     RECT  72.965 7.68 73.969 44.664 ;
     RECT  73.793 46.848 74.009 58.68 ;
     RECT  73.969 3.84 74.041 44.664 ;
     RECT  73.721 60.624 74.051 70.536 ;
     RECT  73.721 71.616 74.077 72.744 ;
     RECT  72.904 74.064 74.077 74.088 ;
     RECT  73.141 76.944 74.243 76.968 ;
     RECT  74.041 3.84 74.333 45.576 ;
     RECT  74.009 46.848 74.369 56.136 ;
     RECT  74.009 57.12 74.401 58.68 ;
     RECT  74.401 57.12 74.437 58.728 ;
     RECT  74.437 57.12 74.473 59.544 ;
     RECT  74.051 60.624 74.473 61.944 ;
     RECT  74.333 3.84 74.585 6.312 ;
     RECT  74.077 71.616 74.617 74.088 ;
     RECT  73.523 75.792 74.653 75.816 ;
     RECT  74.365 1.728 74.675 1.752 ;
     RECT  74.585 3.84 74.693 3.864 ;
     RECT  74.333 7.344 74.729 45.576 ;
     RECT  74.653 75.264 74.737 75.816 ;
     RECT  74.729 41.904 74.828 45.576 ;
     RECT  74.617 71.616 74.945 74.136 ;
     RECT  74.473 57.12 75.013 61.944 ;
     RECT  74.051 63.12 75.013 70.536 ;
     RECT  74.945 71.808 75.017 74.136 ;
     RECT  74.369 47.28 75.121 56.136 ;
     RECT  75.013 57.12 75.121 70.536 ;
     RECT  74.729 7.344 75.269 40.92 ;
     RECT  75.017 71.808 75.269 73.56 ;
     RECT  75.121 47.28 75.299 70.536 ;
     RECT  75.299 57.312 75.377 70.536 ;
     RECT  75.301 74.688 75.413 74.712 ;
     RECT  74.828 41.904 75.481 46.104 ;
     RECT  75.299 47.28 75.481 56.136 ;
     RECT  74.737 75.792 75.557 75.816 ;
     RECT  75.377 64.368 75.685 70.536 ;
     RECT  75.685 64.368 75.772 70.776 ;
     RECT  75.377 57.312 75.773 63.24 ;
     RECT  75.481 41.904 75.779 56.136 ;
     RECT  75.269 34.656 75.875 40.92 ;
     RECT  74.585 5.136 75.949 6.312 ;
     RECT  75.949 4.32 75.989 6.312 ;
     RECT  75.989 5.808 76.021 6.312 ;
     RECT  75.269 7.344 76.021 33.624 ;
     RECT  75.779 46.08 76.025 56.136 ;
     RECT  76.021 5.808 76.067 33.624 ;
     RECT  75.269 72.432 76.093 73.56 ;
     RECT  76.067 5.808 76.108 6.84 ;
     RECT  75.841 1.728 76.115 1.752 ;
     RECT  76.108 5.808 76.169 6.072 ;
     RECT  76.169 5.808 76.205 5.832 ;
     RECT  76.067 7.872 76.241 33.624 ;
     RECT  75.875 38.688 76.273 40.92 ;
     RECT  75.779 41.904 76.273 45 ;
     RECT  75.772 64.368 76.277 69.864 ;
     RECT  76.025 55.872 76.381 56.136 ;
     RECT  75.773 57.312 76.381 59.208 ;
     RECT  76.025 46.08 76.385 54.696 ;
     RECT  76.381 55.872 76.457 59.208 ;
     RECT  75.773 60.288 76.457 63.24 ;
     RECT  76.241 7.968 76.493 33.624 ;
     RECT  76.457 60.384 76.529 63.24 ;
     RECT  76.385 46.08 76.565 53.112 ;
     RECT  76.529 60.384 76.709 63.144 ;
     RECT  76.457 58.08 76.741 59.208 ;
     RECT  76.493 13.056 76.745 33.624 ;
     RECT  76.745 13.056 76.781 30.408 ;
     RECT  76.093 72.432 76.813 73.944 ;
     RECT  76.273 38.688 76.849 45 ;
     RECT  76.565 46.08 76.849 46.92 ;
     RECT  75.875 34.656 76.885 37.56 ;
     RECT  76.813 72.432 76.885 74.28 ;
     RECT  76.277 64.608 76.889 69.864 ;
     RECT  76.889 69.216 77.033 69.384 ;
     RECT  76.273 71.28 77.036 71.304 ;
     RECT  76.885 72.432 77.036 74.424 ;
     RECT  75.989 4.32 77.221 4.344 ;
     RECT  77.036 70.464 77.221 74.424 ;
     RECT  77.221 2.592 77.245 4.344 ;
     RECT  76.889 64.608 77.245 68.232 ;
     RECT  76.745 31.632 77.381 33.624 ;
     RECT  76.385 54.192 77.425 54.696 ;
     RECT  76.457 55.872 77.425 57.048 ;
     RECT  76.741 58.08 77.425 59.256 ;
     RECT  77.245 1.728 77.507 4.344 ;
     RECT  77.425 54.192 77.569 54.744 ;
     RECT  77.425 55.872 77.569 59.256 ;
     RECT  76.849 38.688 77.669 46.92 ;
     RECT  76.565 48.192 77.669 53.112 ;
     RECT  77.381 31.632 77.713 33.672 ;
     RECT  76.885 34.656 77.713 37.608 ;
     RECT  77.569 54.192 77.713 59.544 ;
     RECT  76.709 60.624 77.713 63.144 ;
     RECT  77.669 38.688 77.821 53.112 ;
     RECT  77.713 54.192 77.821 63.144 ;
     RECT  76.493 7.968 77.893 12.072 ;
     RECT  76.781 13.056 77.893 29.064 ;
     RECT  77.245 64.32 77.893 68.232 ;
     RECT  77.033 69.216 77.893 69.24 ;
     RECT  77.821 38.688 77.965 63.144 ;
     RECT  77.893 64.32 77.965 69.24 ;
     RECT  77.507 2.148 78.008 4.344 ;
     RECT  77.893 7.968 78.008 29.064 ;
     RECT  76.781 30.096 78.008 30.408 ;
     RECT  77.713 31.632 78.008 37.608 ;
     RECT  77.965 38.688 78.008 69.24 ;
     RECT  77.221 70.464 78.008 74.712 ;
     RECT  78.008 2.148 78.112 75.612 ;
     RECT  78.112 2.148 78.304 75.342 ;
     RECT  78.304 30.096 78.365 34.872 ;
     RECT  78.365 33.312 78.401 34.872 ;
     RECT  78.365 30.096 78.437 32.328 ;
     RECT  78.304 57.312 78.437 64.968 ;
     RECT  78.304 3.264 78.473 3.432 ;
     RECT  78.304 13.296 78.473 21.144 ;
     RECT  78.437 61.488 78.473 64.968 ;
     RECT  78.304 66 78.473 73.608 ;
     RECT  78.304 39.264 78.509 41.448 ;
     RECT  78.304 46.32 78.509 46.872 ;
     RECT  78.473 66 78.509 72.84 ;
     RECT  78.304 12 78.515 12.072 ;
     RECT  78.473 15.456 78.545 21.144 ;
     RECT  78.304 22.224 78.545 27.96 ;
     RECT  78.509 40.656 78.545 41.448 ;
     RECT  78.304 45.264 78.545 45.288 ;
     RECT  78.304 54.864 78.545 55.848 ;
     RECT  78.304 50.16 78.563 53.784 ;
     RECT  78.515 12 78.581 12.024 ;
     RECT  78.563 50.544 78.581 53.784 ;
     RECT  78.437 57.312 78.581 60.408 ;
     RECT  78.473 61.488 78.581 64.392 ;
     RECT  78.545 18.144 78.617 21.144 ;
     RECT  78.545 22.224 78.617 26.136 ;
     RECT  78.545 41.424 78.617 41.448 ;
     RECT  78.304 9.072 78.653 10.968 ;
     RECT  78.581 57.312 78.653 59.928 ;
     RECT  78.581 61.488 78.653 62.856 ;
     RECT  78.617 20.064 78.659 21.144 ;
     RECT  78.509 68.064 78.659 72.84 ;
     RECT  78.473 13.296 78.689 14.472 ;
     RECT  78.509 39.264 78.689 39.288 ;
     RECT  78.581 50.592 78.689 53.784 ;
     RECT  78.581 63.84 78.689 64.392 ;
     RECT  78.689 13.296 78.725 14.136 ;
     RECT  78.659 20.064 78.755 21 ;
     RECT  78.653 9.072 78.761 10.392 ;
     RECT  78.755 20.352 78.761 21 ;
     RECT  78.617 23.568 78.761 26.136 ;
     RECT  78.653 58.464 78.761 59.928 ;
     RECT  78.761 23.568 78.796 23.592 ;
     RECT  78.689 50.592 78.797 52.584 ;
     RECT  78.725 13.296 78.803 13.656 ;
     RECT  78.401 33.504 78.803 34.872 ;
     RECT  78.304 36.048 78.805 37.656 ;
     RECT  78.803 13.296 78.833 13.32 ;
     RECT  78.617 18.144 78.833 19.032 ;
     RECT  78.761 20.976 78.833 21 ;
     RECT  78.617 22.224 78.833 22.248 ;
     RECT  78.545 27.168 78.833 27.96 ;
     RECT  78.437 30.192 78.833 32.328 ;
     RECT  78.304 42.72 78.833 43.704 ;
     RECT  78.545 54.864 78.833 55.512 ;
     RECT  78.653 61.488 78.833 62.664 ;
     RECT  78.689 63.84 78.833 63.864 ;
     RECT  78.509 66 78.833 67.032 ;
     RECT  78.805 36.048 78.844 37.176 ;
     RECT  78.304 47.856 78.851 49.176 ;
     RECT  78.797 50.592 78.851 51.288 ;
     RECT  78.797 52.56 78.851 52.584 ;
     RECT  78.833 54.864 78.851 55.128 ;
     RECT  78.833 61.488 78.851 61.992 ;
     RECT  78.761 9.072 78.869 9.096 ;
     RECT  78.761 10.368 78.869 10.392 ;
     RECT  78.545 15.456 78.869 17.112 ;
     RECT  78.833 32.208 78.869 32.328 ;
     RECT  78.833 43.68 78.869 43.704 ;
     RECT  78.851 61.728 78.869 61.992 ;
     RECT  78.803 33.504 78.877 33.672 ;
     RECT  78.803 34.848 78.877 34.872 ;
     RECT  78.851 47.856 78.877 47.88 ;
     RECT  78.851 49.152 78.892 49.176 ;
     RECT  78.689 53.76 78.892 53.784 ;
     RECT  78.851 55.104 78.892 55.128 ;
     RECT  78.833 18.528 78.899 19.032 ;
     RECT  78.761 24.672 78.899 26.136 ;
     RECT  78.761 58.656 78.899 59.928 ;
     RECT  78.899 24.672 78.905 25.512 ;
     RECT  78.833 30.192 78.905 30.792 ;
     RECT  78.851 50.592 78.905 50.616 ;
     RECT  78.833 66.864 78.905 67.032 ;
     RECT  78.833 27.936 78.941 27.96 ;
     RECT  78.685 1.728 78.947 1.752 ;
     RECT  78.899 59.184 78.977 59.544 ;
     RECT  78.869 61.968 79.013 61.992 ;
     RECT  78.905 24.96 79.049 25.512 ;
     RECT  78.905 30.192 79.049 30.216 ;
     RECT  78.877 33.648 79.049 33.672 ;
     RECT  78.509 46.32 79.085 46.536 ;
     RECT  78.977 59.184 79.085 59.208 ;
     RECT  78.659 68.064 79.093 69.192 ;
     RECT  78.899 18.528 79.121 18.792 ;
     RECT  78.869 15.936 79.229 17.112 ;
     RECT  78.844 36.048 79.229 36.072 ;
     RECT  79.085 46.512 79.229 46.536 ;
     RECT  79.093 68.064 79.229 68.088 ;
     RECT  78.659 70.512 79.229 72.84 ;
     RECT  79.229 17.088 79.301 17.112 ;
     RECT  78.844 37.152 79.337 37.176 ;
     RECT  78.869 32.304 79.373 32.328 ;
     RECT  78.473 3.264 79.409 3.288 ;
     RECT  79.229 72.816 79.409 72.84 ;
     RECT  79.229 70.512 79.481 71.688 ;
     RECT  79.049 24.96 79.517 24.984 ;
     RECT  79.481 70.512 79.625 71.352 ;
     RECT  79.625 70.56 79.697 71.352 ;
     RECT  78.145 77.664 79.811 77.688 ;
     RECT  79.729 69.504 79.813 69.528 ;
     RECT  80.341 0.576 80.425 0.6 ;
     RECT  80.701 1.776 82.044 1.8 ;
     RECT  80.701 3.312 82.044 3.336 ;
     RECT  80.341 4.848 82.044 4.872 ;
     RECT  80.341 6.384 82.044 6.408 ;
     RECT  81.457 7.968 82.044 7.992 ;
     RECT  80.881 9.504 82.044 9.528 ;
     RECT  80.881 11.04 82.044 11.064 ;
     RECT  81.457 12.576 82.044 12.6 ;
     RECT  80.701 14.112 82.044 14.136 ;
     RECT  80.881 15.696 82.044 15.72 ;
     RECT  80.953 17.232 82.044 17.256 ;
     RECT  79.121 18.768 82.044 18.792 ;
     RECT  80.917 20.304 82.044 20.328 ;
     RECT  80.881 21.84 82.044 21.864 ;
     RECT  80.917 23.424 82.044 23.448 ;
     RECT  80.917 24.96 82.044 24.984 ;
     RECT  80.917 26.496 82.044 26.52 ;
     RECT  80.917 28.032 82.044 28.056 ;
     RECT  80.917 29.568 82.044 29.592 ;
     RECT  80.917 31.152 82.044 31.176 ;
     RECT  80.917 32.688 82.044 32.712 ;
     RECT  80.917 34.224 82.044 34.248 ;
     RECT  80.917 35.76 82.044 35.784 ;
     RECT  80.917 37.344 82.044 37.368 ;
     RECT  80.917 38.88 82.044 38.904 ;
     RECT  80.917 40.416 82.044 40.44 ;
     RECT  80.377 41.952 82.044 41.976 ;
     RECT  80.917 43.488 82.044 43.512 ;
     RECT  80.377 45.072 82.044 45.096 ;
     RECT  80.917 46.608 82.044 46.632 ;
     RECT  80.377 48.144 82.044 48.168 ;
     RECT  80.917 49.68 82.044 49.704 ;
     RECT  80.917 51.216 82.044 51.24 ;
     RECT  80.917 52.8 82.044 52.824 ;
     RECT  80.917 54.336 82.044 54.36 ;
     RECT  80.881 55.872 82.044 55.896 ;
     RECT  80.773 57.408 82.044 57.432 ;
     RECT  80.917 58.992 82.044 59.016 ;
     RECT  80.917 60.528 82.044 60.552 ;
     RECT  80.917 62.064 82.044 62.088 ;
     RECT  80.917 63.6 82.044 63.624 ;
     RECT  80.917 65.136 82.044 65.16 ;
     RECT  80.917 66.72 82.044 66.744 ;
     RECT  80.917 68.256 82.044 68.28 ;
     RECT  80.917 69.792 82.044 69.816 ;
     RECT  79.697 71.328 82.044 71.352 ;
     RECT  80.377 72.864 82.044 72.888 ;
     RECT  79.369 74.448 82.044 74.472 ;
     RECT  81.457 75.984 82.044 76.008 ;
    LAYER M5 ;
     RECT  47.472 0.016 47.496 0.131 ;
     RECT  53.184 0.016 53.208 0.131 ;
     RECT  67.488 0.016 67.512 0.131 ;
     RECT  56.064 0.016 56.088 0.611 ;
     RECT  58.896 0.016 58.92 0.611 ;
     RECT  80.352 0.016 80.376 0.611 ;
     RECT  50.304 0.016 50.328 1.139 ;
     RECT  48.912 0.016 48.936 1.763 ;
     RECT  54.624 0.016 54.648 1.763 ;
     RECT  57.456 0.016 57.48 1.763 ;
     RECT  60.336 0.016 60.36 1.763 ;
     RECT  61.776 0.016 61.8 1.763 ;
     RECT  63.216 0.016 63.24 1.763 ;
     RECT  64.608 0.016 64.632 1.763 ;
     RECT  66.048 0.016 66.072 1.763 ;
     RECT  68.928 0.016 68.952 1.763 ;
     RECT  70.32 0.016 70.344 1.763 ;
     RECT  71.76 0.016 71.784 1.763 ;
     RECT  73.2 0.016 73.224 1.763 ;
     RECT  74.64 0.016 74.664 1.763 ;
     RECT  76.08 0.016 76.104 1.763 ;
     RECT  78.912 0.016 78.936 1.763 ;
     RECT  51.744 0.016 51.768 2.137 ;
     RECT  77.472 0.016 77.496 2.137 ;
     RECT  2.4 2.137 2.52 2.151 ;
     RECT  7.8 2.137 7.92 2.151 ;
     RECT  13.2 2.137 13.32 2.151 ;
     RECT  18.6 2.137 18.72 2.151 ;
     RECT  24 2.137 24.12 2.151 ;
     RECT  29.4 2.137 29.52 2.151 ;
     RECT  34.8 2.137 34.92 2.151 ;
     RECT  40.2 2.137 40.32 2.151 ;
     RECT  45.6 2.137 45.72 2.151 ;
     RECT  61.8 2.137 61.92 2.151 ;
     RECT  67.2 2.137 67.32 2.151 ;
     RECT  51 2.137 51.768 2.195 ;
     RECT  52.416 2.245 52.488 2.531 ;
     RECT  77.472 2.137 78.312 2.581 ;
     RECT  67.2 2.151 67.512 2.773 ;
     RECT  29.4 2.151 29.712 3.061 ;
     RECT  56.4 2.137 56.712 3.109 ;
     RECT  51 2.195 51.312 3.157 ;
     RECT  52.416 2.531 52.44 3.157 ;
     RECT  56.112 3.109 56.712 3.157 ;
     RECT  24 2.151 24.312 3.205 ;
     RECT  45.6 2.151 45.912 3.205 ;
     RECT  55.824 3.157 56.712 3.205 ;
     RECT  23.376 3.205 24.312 3.349 ;
     RECT  34.8 2.151 35.112 3.349 ;
     RECT  67.2 2.773 67.8 3.349 ;
     RECT  7.8 2.151 8.112 3.397 ;
     RECT  13.2 2.151 13.512 3.397 ;
     RECT  18.6 2.151 18.912 3.397 ;
     RECT  45.6 3.205 46.776 3.397 ;
     RECT  59.232 2.725 59.256 3.443 ;
     RECT  67.056 3.349 67.8 3.443 ;
     RECT  28.464 3.061 29.712 3.587 ;
     RECT  51 3.157 52.44 3.589 ;
     RECT  44.688 3.397 46.776 3.637 ;
     RECT  67.056 3.443 67.512 3.685 ;
     RECT  34.8 3.349 35.4 3.733 ;
     RECT  44.688 3.637 47.64 3.733 ;
     RECT  49.968 2.821 49.992 3.733 ;
     RECT  20.688 2.821 20.712 3.877 ;
     RECT  61.8 2.151 62.112 3.877 ;
     RECT  63.12 3.397 63.144 3.877 ;
     RECT  20.688 3.877 21.384 3.923 ;
     RECT  22.704 3.349 24.408 3.925 ;
     RECT  38.016 3.061 38.04 3.925 ;
     RECT  40.2 2.151 40.512 3.925 ;
     RECT  64.8 3.013 64.824 3.925 ;
     RECT  16.032 2.821 16.056 3.971 ;
     RECT  7.488 3.397 8.112 4.067 ;
     RECT  11.568 3.205 11.592 4.067 ;
     RECT  17.664 3.397 18.912 4.115 ;
     RECT  34.8 3.733 36.312 4.117 ;
     RECT  38.016 3.925 38.136 4.117 ;
     RECT  49.776 3.733 49.992 4.117 ;
     RECT  51 3.589 53.4 4.117 ;
     RECT  49.776 4.117 53.4 4.165 ;
     RECT  34.8 4.117 38.136 4.261 ;
     RECT  49.776 4.165 54.168 4.261 ;
     RECT  60.528 4.213 60.552 4.261 ;
     RECT  44.688 3.733 47.88 4.309 ;
     RECT  61.8 3.877 63.144 4.355 ;
     RECT  77.232 2.581 78.312 4.355 ;
     RECT  64.56 3.925 64.824 4.357 ;
     RECT  55.44 3.205 56.712 4.403 ;
     RECT  60.528 4.261 60.744 4.403 ;
     RECT  18.6 4.115 18.912 4.405 ;
     RECT  7.8 4.067 8.112 4.453 ;
     RECT  44.256 4.309 47.88 4.453 ;
     RECT  60.528 4.403 60.552 4.499 ;
     RECT  55.824 4.403 56.712 4.501 ;
     RECT  66.912 3.685 67.512 4.501 ;
     RECT  70.416 2.821 70.44 4.501 ;
     RECT  72.6 2.137 72.912 4.501 ;
     RECT  70.416 4.501 70.68 4.547 ;
     RECT  31.68 4.261 31.704 4.549 ;
     RECT  10.128 3.973 10.152 4.643 ;
     RECT  66.432 4.501 67.512 4.837 ;
     RECT  13.104 3.397 13.512 5.077 ;
     RECT  64.464 4.357 64.824 5.077 ;
     RECT  70.656 4.547 70.68 5.123 ;
     RECT  34.8 4.261 38.184 5.171 ;
     RECT  22.512 3.925 24.408 5.173 ;
     RECT  55.824 4.501 56.904 5.173 ;
     RECT  13.104 5.077 14.28 5.219 ;
     RECT  31.056 4.549 31.704 5.221 ;
     RECT  32.928 3.925 32.952 5.221 ;
     RECT  18.6 4.405 19.752 5.269 ;
     RECT  21.264 3.923 21.384 5.269 ;
     RECT  26.208 3.877 26.232 5.269 ;
     RECT  27.216 5.077 27.24 5.269 ;
     RECT  22.512 5.173 24.6 5.317 ;
     RECT  22.512 5.317 24.696 5.363 ;
     RECT  55.824 5.173 57.768 5.365 ;
     RECT  28.8 3.587 29.712 5.411 ;
     RECT  48.864 4.261 54.168 5.411 ;
     RECT  23.616 5.363 24.696 5.461 ;
     RECT  26.208 5.269 27.24 5.461 ;
     RECT  64.368 5.077 64.824 5.461 ;
     RECT  15.792 5.365 15.816 5.557 ;
     RECT  55.824 5.365 58.68 5.557 ;
     RECT  59.808 4.645 59.832 5.557 ;
     RECT  18.6 5.269 21.384 5.653 ;
     RECT  7.8 4.453 8.328 5.797 ;
     RECT  59.808 5.557 60.648 5.797 ;
     RECT  63.936 5.461 64.824 5.845 ;
     RECT  44.112 4.453 47.88 5.989 ;
     RECT  61.8 4.355 62.76 5.989 ;
     RECT  63.936 5.845 64.968 5.989 ;
     RECT  7.8 5.797 8.52 6.131 ;
     RECT  13.2 5.219 14.28 6.131 ;
     RECT  70.176 5.653 70.2 6.133 ;
     RECT  34.8 5.171 36.312 6.421 ;
     RECT  37.392 5.171 38.184 6.421 ;
     RECT  23.616 5.461 27.24 6.469 ;
     RECT  13.2 6.131 13.512 6.613 ;
     RECT  42.288 5.749 42.312 6.661 ;
     RECT  59.808 5.797 60.792 6.707 ;
     RECT  22.512 5.363 22.536 6.709 ;
     RECT  23.616 6.469 27.432 6.709 ;
     RECT  22.512 6.709 27.432 6.757 ;
     RECT  34.8 6.421 38.184 6.805 ;
     RECT  43.44 5.989 47.88 6.805 ;
     RECT  18.48 5.653 21.384 6.851 ;
     RECT  61.8 5.989 64.968 6.853 ;
     RECT  72.336 4.501 72.912 6.853 ;
     RECT  4.704 3.925 4.728 6.899 ;
     RECT  12.528 6.613 13.512 6.899 ;
     RECT  43.392 6.805 47.88 7.093 ;
     RECT  48.864 5.411 54.072 7.093 ;
     RECT  60.48 6.707 60.792 7.093 ;
     RECT  61.8 6.853 65.016 7.093 ;
     RECT  66.432 4.837 67.704 7.093 ;
     RECT  69.504 6.133 70.2 7.093 ;
     RECT  66.432 7.093 70.2 7.235 ;
     RECT  40.2 3.925 41.16 7.237 ;
     RECT  40.2 7.237 41.256 7.379 ;
     RECT  60.48 7.093 65.016 7.381 ;
     RECT  72.192 6.853 72.912 7.381 ;
     RECT  15.696 5.557 15.816 7.475 ;
     RECT  31.056 5.221 32.952 7.571 ;
     RECT  15.792 7.475 15.816 7.765 ;
     RECT  16.944 7.237 16.968 7.765 ;
     RECT  15.792 7.765 16.968 7.811 ;
     RECT  76.032 6.805 76.056 7.907 ;
     RECT  13.2 6.899 13.512 7.957 ;
     RECT  29.4 5.411 29.712 7.957 ;
     RECT  78 4.355 78.312 7.957 ;
     RECT  60.48 7.381 65.064 8.003 ;
     RECT  43.392 7.093 54.072 8.005 ;
     RECT  55.248 5.557 58.68 8.005 ;
     RECT  66.432 7.235 69.576 8.051 ;
     RECT  66.432 8.051 67.704 8.101 ;
     RECT  29.4 7.957 29.976 8.197 ;
     RECT  31.056 7.571 32.424 8.197 ;
     RECT  34.128 6.805 38.184 8.245 ;
     RECT  34.128 8.245 38.664 8.293 ;
     RECT  33.792 8.293 38.664 8.341 ;
     RECT  71.856 7.381 72.912 8.341 ;
     RECT  18.6 6.851 21.384 8.389 ;
     RECT  7.8 6.131 8.112 8.437 ;
     RECT  66.336 8.101 67.704 8.437 ;
     RECT  9.6 5.077 9.624 8.483 ;
     RECT  40.2 7.379 41.16 8.485 ;
     RECT  77.424 7.957 78.312 8.531 ;
     RECT  42.288 6.661 42.36 8.533 ;
     RECT  43.392 8.005 58.68 8.533 ;
     RECT  22.512 6.757 28.152 8.629 ;
     RECT  71.472 8.341 72.912 8.675 ;
     RECT  22.512 8.629 28.344 8.771 ;
     RECT  42.288 8.533 58.68 8.819 ;
     RECT  29.4 8.197 32.424 8.869 ;
     RECT  33.792 8.341 38.808 8.869 ;
     RECT  29.4 8.869 38.808 9.013 ;
     RECT  39.792 8.485 41.16 9.061 ;
     RECT  12.816 7.957 13.512 9.107 ;
     RECT  68.928 8.051 69.576 9.155 ;
     RECT  18.432 8.389 21.384 9.203 ;
     RECT  60.48 8.003 65.016 9.253 ;
     RECT  59.76 9.253 65.016 9.349 ;
     RECT  77.472 8.531 78.312 9.349 ;
     RECT  21.12 9.203 21.384 9.395 ;
     RECT  21.216 9.395 21.384 9.443 ;
     RECT  11.232 6.853 11.256 9.589 ;
     RECT  29.136 9.013 38.808 9.589 ;
     RECT  39.792 9.061 41.256 9.589 ;
     RECT  18.432 9.203 19.992 9.635 ;
     RECT  72.192 8.675 72.912 9.637 ;
     RECT  75.408 9.061 75.432 9.685 ;
     RECT  77.472 9.349 78.408 9.731 ;
     RECT  22.512 8.771 28.104 9.973 ;
     RECT  29.136 9.589 41.256 9.973 ;
     RECT  42.288 8.819 58.392 10.069 ;
     RECT  59.76 9.349 65.064 10.069 ;
     RECT  68.928 9.155 69.288 10.115 ;
     RECT  2.4 2.151 2.712 10.165 ;
     RECT  70.56 8.773 70.584 10.165 ;
     RECT  71.808 9.637 72.912 10.165 ;
     RECT  6.48 10.165 6.504 10.213 ;
     RECT  11.232 9.589 12.216 10.213 ;
     RECT  22.512 9.973 41.256 10.213 ;
     RECT  42.288 10.069 65.064 10.213 ;
     RECT  68.928 10.115 69 10.213 ;
     RECT  18.6 9.635 19.992 10.307 ;
     RECT  22.512 10.213 65.064 10.307 ;
     RECT  78 9.731 78.408 10.309 ;
     RECT  66.192 8.437 67.704 10.357 ;
     RECT  15.792 7.811 16.056 10.789 ;
     RECT  14.64 10.213 14.664 10.835 ;
     RECT  65.808 10.357 67.704 10.837 ;
     RECT  68.688 10.213 69 10.837 ;
     RECT  7.8 8.437 8.616 10.883 ;
     RECT  10.848 10.213 12.216 10.883 ;
     RECT  15.696 10.789 16.056 10.883 ;
     RECT  15.696 10.883 15.816 10.885 ;
     RECT  75.408 9.685 75.864 10.933 ;
     RECT  76.992 10.213 77.016 10.981 ;
     RECT  78 10.309 78.504 10.981 ;
     RECT  74.832 10.933 75.864 11.027 ;
     RECT  18.6 10.307 19.848 11.029 ;
     RECT  14.88 10.885 15.816 11.075 ;
     RECT  13.2 9.107 13.512 11.221 ;
     RECT  70.56 10.165 72.912 11.317 ;
     RECT  65.808 10.837 69 11.413 ;
     RECT  21.264 9.443 21.384 11.461 ;
     RECT  22.512 10.307 64.824 11.461 ;
     RECT  65.808 11.413 69.048 11.461 ;
     RECT  10.848 10.883 11.784 11.507 ;
     RECT  74.832 11.027 75.432 11.651 ;
     RECT  5.664 10.213 6.504 11.747 ;
     RECT  21.264 11.461 69.048 11.795 ;
     RECT  70.128 11.317 72.912 11.893 ;
     RECT  11.088 11.507 11.784 11.941 ;
     RECT  70.128 11.893 73.752 11.941 ;
     RECT  74.832 11.651 74.856 11.941 ;
     RECT  65.808 11.795 69.048 11.987 ;
     RECT  76.992 10.981 78.504 12.035 ;
     RECT  78 12.035 78.504 12.083 ;
     RECT  65.808 11.987 69 12.371 ;
     RECT  11.088 11.941 12.024 12.517 ;
     RECT  13.2 11.221 13.704 12.517 ;
     RECT  18.288 11.029 19.848 12.565 ;
     RECT  21.264 11.795 64.824 12.565 ;
     RECT  70.128 11.941 74.856 12.659 ;
     RECT  7.8 10.883 8.232 12.805 ;
     RECT  18.288 12.565 64.824 12.805 ;
     RECT  65.808 12.371 67.704 12.805 ;
     RECT  18.288 12.805 67.704 12.901 ;
     RECT  15.696 11.075 15.72 12.947 ;
     RECT  2.4 10.165 2.808 13.043 ;
     RECT  74.352 12.659 74.856 13.045 ;
     RECT  17.424 12.901 67.704 13.091 ;
     RECT  68.688 12.371 69 13.091 ;
     RECT  68.976 13.091 69 13.093 ;
     RECT  70.128 12.659 72.912 13.093 ;
     RECT  6.288 11.747 6.504 13.139 ;
     RECT  68.976 13.093 72.912 13.235 ;
     RECT  21.024 13.091 67.704 13.283 ;
     RECT  17.424 13.091 19.752 13.333 ;
     RECT  70.032 13.235 72.912 13.427 ;
     RECT  76.992 12.035 77.016 13.523 ;
     RECT  78 12.083 78.312 13.525 ;
     RECT  77.424 13.525 78.312 13.621 ;
     RECT  21.12 13.283 67.704 13.667 ;
     RECT  17.04 13.333 19.752 13.717 ;
     RECT  71.28 13.427 72.912 13.763 ;
     RECT  11.088 12.517 13.704 13.811 ;
     RECT  72.6 13.763 72.912 14.005 ;
     RECT  74.352 13.045 75.288 14.005 ;
     RECT  6.48 13.139 6.504 14.099 ;
     RECT  7.8 12.805 8.904 14.099 ;
     RECT  16.8 13.717 19.752 14.147 ;
     RECT  7.8 14.099 8.232 14.387 ;
     RECT  71.28 13.763 71.496 14.725 ;
     RECT  72.6 14.005 75.288 14.725 ;
     RECT  77.424 13.621 78.792 14.773 ;
     RECT  68.976 13.235 69 14.869 ;
     RECT  70.032 13.427 70.056 14.915 ;
     RECT  12.24 13.811 13.704 15.301 ;
     RECT  68.976 14.869 69.048 15.301 ;
     RECT  21.264 13.667 67.704 15.349 ;
     RECT  71.28 14.725 75.288 15.491 ;
     RECT  71.28 15.491 73.32 15.539 ;
     RECT  74.352 15.491 75.288 15.589 ;
     RECT  76.608 14.773 78.792 15.589 ;
     RECT  68.688 15.301 69.048 15.875 ;
     RECT  71.28 15.539 71.448 15.925 ;
     RECT  11.088 13.811 11.256 15.973 ;
     RECT  10.896 15.973 11.256 16.117 ;
     RECT  12.24 15.301 14.088 16.117 ;
     RECT  10.896 16.117 14.088 16.307 ;
     RECT  20.976 15.349 67.704 16.357 ;
     RECT  68.688 15.875 69 16.357 ;
     RECT  74.352 15.589 78.792 16.357 ;
     RECT  20.976 16.357 69 16.403 ;
     RECT  4.608 14.773 4.632 16.405 ;
     RECT  17.04 14.147 19.752 16.405 ;
     RECT  70.608 15.925 71.448 16.499 ;
     RECT  72.6 15.539 73.32 16.501 ;
     RECT  74.352 16.357 78.888 16.501 ;
     RECT  21.12 16.403 69 16.595 ;
     RECT  72.6 16.501 78.888 16.595 ;
     RECT  4.608 16.405 4.776 16.837 ;
     RECT  16.656 16.405 19.752 17.027 ;
     RECT  15.312 16.741 15.336 17.075 ;
     RECT  4.608 16.837 5.736 17.123 ;
     RECT  16.992 17.027 19.752 17.123 ;
     RECT  72.6 16.595 75.288 17.125 ;
     RECT  9.744 16.405 9.768 17.267 ;
     RECT  72.48 17.125 75.288 17.267 ;
     RECT  21.12 16.595 21.384 17.363 ;
     RECT  72.6 17.267 75.288 17.363 ;
     RECT  11.088 16.307 14.088 17.509 ;
     RECT  70.608 16.499 71.304 17.557 ;
     RECT  11.088 17.509 14.952 17.651 ;
     RECT  21.216 17.363 21.384 17.651 ;
     RECT  11.232 17.651 14.952 17.699 ;
     RECT  7.8 14.387 8.112 18.133 ;
     RECT  17.424 17.123 19.752 18.133 ;
     RECT  2.4 13.043 2.712 18.181 ;
     RECT  7.8 18.133 8.376 18.181 ;
     RECT  4.608 17.123 4.632 18.659 ;
     RECT  17.28 18.133 19.752 18.707 ;
     RECT  74.352 17.363 75.288 18.803 ;
     RECT  22.512 16.595 69 18.805 ;
     RECT  21.264 17.651 21.384 18.997 ;
     RECT  12.288 17.699 14.952 19.187 ;
     RECT  21.264 18.997 21.48 19.187 ;
     RECT  75.264 18.803 75.288 19.189 ;
     RECT  76.608 16.595 78.888 19.189 ;
     RECT  12.288 19.187 14.808 19.235 ;
     RECT  75.264 19.189 78.888 19.235 ;
     RECT  5.712 17.123 5.736 19.333 ;
     RECT  7.68 18.181 8.376 19.333 ;
     RECT  72.6 17.363 73.32 19.765 ;
     RECT  5.568 19.333 5.736 19.811 ;
     RECT  12.288 19.235 14.088 19.811 ;
     RECT  7.68 19.333 8.52 20.003 ;
     RECT  16.464 19.141 16.488 20.003 ;
     RECT  70.608 17.557 71.352 20.005 ;
     RECT  72.48 19.765 73.32 20.005 ;
     RECT  11.232 17.699 11.256 20.485 ;
     RECT  17.472 18.707 19.752 20.723 ;
     RECT  5.712 19.811 5.736 21.013 ;
     RECT  7.68 20.003 8.112 21.155 ;
     RECT  10.944 20.485 11.256 21.155 ;
     RECT  75.792 19.235 78.888 21.203 ;
     RECT  5.712 21.013 6.216 21.397 ;
     RECT  12.288 19.811 14.04 21.443 ;
     RECT  17.568 20.723 19.752 21.539 ;
     RECT  7.8 21.155 8.112 21.637 ;
     RECT  9.408 20.869 9.432 21.637 ;
     RECT  15.552 21.109 15.576 21.637 ;
     RECT  21.264 19.187 21.384 21.637 ;
     RECT  22.512 18.805 69.24 21.637 ;
     RECT  2.4 18.181 2.904 21.683 ;
     RECT  5.04 21.397 6.216 21.683 ;
     RECT  7.8 21.637 9.432 21.683 ;
     RECT  75.792 21.203 76.632 21.875 ;
     RECT  5.712 21.683 6.216 21.923 ;
     RECT  22.512 21.637 69.432 22.165 ;
     RECT  70.608 20.005 73.32 22.165 ;
     RECT  15.552 21.637 16.008 22.213 ;
     RECT  13.104 21.443 14.04 22.259 ;
     RECT  20.928 21.637 21.384 22.307 ;
     RECT  7.8 21.683 9.24 22.355 ;
     RECT  7.8 22.355 8.52 22.499 ;
     RECT  22.512 22.165 73.32 22.499 ;
     RECT  76.608 21.875 76.632 22.549 ;
     RECT  77.616 21.203 78.888 22.549 ;
     RECT  76.608 22.549 78.888 22.595 ;
     RECT  15.12 22.213 16.008 22.741 ;
     RECT  17.616 21.539 19.752 22.741 ;
     RECT  11.232 21.155 11.256 23.027 ;
     RECT  21.264 22.307 21.384 23.221 ;
     RECT  22.512 22.499 72.912 23.221 ;
     RECT  17.424 22.741 19.752 23.269 ;
     RECT  21.264 23.221 72.912 23.269 ;
     RECT  7.8 22.499 8.232 23.315 ;
     RECT  3.984 22.597 4.008 23.555 ;
     RECT  13.2 22.259 14.04 23.797 ;
     RECT  5.712 21.923 5.736 23.893 ;
     RECT  74.88 23.077 74.904 23.939 ;
     RECT  15.072 22.741 16.008 24.131 ;
     RECT  4.848 23.893 5.736 24.419 ;
     RECT  10.128 23.941 10.152 24.469 ;
     RECT  10.128 24.469 10.824 24.755 ;
     RECT  17.424 23.269 72.912 24.947 ;
     RECT  76.8 22.595 78.888 24.997 ;
     RECT  20.88 24.947 72.912 25.237 ;
     RECT  15.072 24.131 15.144 25.285 ;
     RECT  74.208 25.141 74.232 25.331 ;
     RECT  2.4 21.683 2.712 25.525 ;
     RECT  20.88 25.237 73.128 25.573 ;
     RECT  4.848 24.419 4.872 25.621 ;
     RECT  15.072 25.285 15.24 25.621 ;
     RECT  13.104 23.797 14.04 25.717 ;
     RECT  10.8 24.755 10.824 25.763 ;
     RECT  4.56 25.621 4.872 26.051 ;
     RECT  15.072 25.621 15.288 26.243 ;
     RECT  15.264 26.243 15.288 26.389 ;
     RECT  20.88 25.573 73.896 26.579 ;
     RECT  7.8 23.315 8.112 26.629 ;
     RECT  21.264 26.579 73.896 26.675 ;
     RECT  17.424 24.947 19.752 26.725 ;
     RECT  7.8 26.629 9.096 27.301 ;
     RECT  76.176 24.997 78.888 27.301 ;
     RECT  6.096 27.109 6.12 27.635 ;
     RECT  21.264 26.675 72.912 27.635 ;
     RECT  2.4 25.525 2.808 27.683 ;
     RECT  21.264 27.635 59.352 27.685 ;
     RECT  13.056 25.717 14.04 27.733 ;
     RECT  15.264 26.389 15.72 27.733 ;
     RECT  13.056 27.733 15.72 27.779 ;
     RECT  60.384 27.635 72.912 27.781 ;
     RECT  21.216 27.685 59.352 27.875 ;
     RECT  17.136 26.725 19.752 27.923 ;
     RECT  21.264 27.875 59.352 27.923 ;
     RECT  60.384 27.781 73.224 27.923 ;
     RECT  75.792 27.301 78.888 27.971 ;
     RECT  7.8 27.301 9.48 28.019 ;
     RECT  7.8 28.019 9.144 28.115 ;
     RECT  13.056 27.779 14.856 28.259 ;
     RECT  13.056 28.259 14.04 28.451 ;
     RECT  13.2 28.451 14.04 28.595 ;
     RECT  22.464 27.923 59.352 28.837 ;
     RECT  60.384 27.923 72.912 28.837 ;
     RECT  75.792 27.971 78.312 29.173 ;
     RECT  21.264 27.923 21.384 29.653 ;
     RECT  22.464 28.837 72.912 29.653 ;
     RECT  7.8 28.115 9.096 30.181 ;
     RECT  7.8 30.181 9.528 30.467 ;
     RECT  13.2 28.595 13.704 30.611 ;
     RECT  21.264 29.653 72.912 30.611 ;
     RECT  2.4 27.683 2.712 30.661 ;
     RECT  13.2 30.611 13.512 30.661 ;
     RECT  4.848 26.051 4.872 30.805 ;
     RECT  75.408 29.173 78.312 30.899 ;
     RECT  28.704 30.611 72.912 30.997 ;
     RECT  10.56 30.709 10.584 31.093 ;
     RECT  17.328 27.923 19.752 31.093 ;
     RECT  21.264 30.611 27.624 31.093 ;
     RECT  10.56 31.093 10.824 31.139 ;
     RECT  12.288 30.661 13.512 31.139 ;
     RECT  17.328 31.093 27.624 31.283 ;
     RECT  21.264 31.283 27.624 31.331 ;
     RECT  15.36 30.757 15.384 31.379 ;
     RECT  75.408 30.899 75.432 31.379 ;
     RECT  21.6 31.331 27.624 31.621 ;
     RECT  28.704 30.997 73.272 31.621 ;
     RECT  4.848 30.805 5.256 31.669 ;
     RECT  17.328 31.283 20.04 31.763 ;
     RECT  7.8 30.467 9.096 31.811 ;
     RECT  21.6 31.621 73.272 31.811 ;
     RECT  21.6 31.811 27.624 31.907 ;
     RECT  59.328 31.811 73.272 31.907 ;
     RECT  10.8 31.139 10.824 31.955 ;
     RECT  76.752 30.899 78.312 31.955 ;
     RECT  3.936 31.669 5.256 32.051 ;
     RECT  59.328 31.907 72.912 32.195 ;
     RECT  2.304 30.661 2.712 32.243 ;
     RECT  14.976 31.765 15 32.291 ;
     RECT  17.424 31.763 20.04 32.579 ;
     RECT  59.328 32.195 65.688 33.011 ;
     RECT  63.696 33.011 65.592 33.059 ;
     RECT  29.232 31.811 58.344 33.107 ;
     RECT  74.256 30.853 74.28 33.155 ;
     RECT  77.088 31.955 78.312 33.443 ;
     RECT  17.424 32.579 19.752 33.493 ;
     RECT  77.424 33.443 78.312 33.493 ;
     RECT  67.008 32.195 72.912 33.541 ;
     RECT  77.424 33.493 78.84 33.683 ;
     RECT  67.008 33.541 73.032 33.971 ;
     RECT  3.936 32.051 4.872 34.115 ;
     RECT  63.696 33.059 65.544 34.211 ;
     RECT  9.648 33.589 9.672 34.309 ;
     RECT  9.648 34.309 10.488 34.355 ;
     RECT  17.184 33.493 19.752 34.355 ;
     RECT  21.888 31.907 27.624 34.357 ;
     RECT  17.424 34.355 19.752 34.403 ;
     RECT  29.232 33.107 58.2 34.453 ;
     RECT  59.328 33.011 62.52 34.453 ;
     RECT  17.904 34.403 19.752 34.501 ;
     RECT  29.232 34.453 62.52 34.691 ;
     RECT  13.2 31.139 13.512 34.741 ;
     RECT  78 33.683 78.84 34.883 ;
     RECT  72.096 33.971 73.032 34.931 ;
     RECT  21.792 34.357 27.624 35.171 ;
     RECT  29.232 34.691 62.28 35.171 ;
     RECT  29.232 35.171 38.136 35.173 ;
     RECT  15.936 33.013 15.96 35.317 ;
     RECT  39.264 35.171 62.28 35.363 ;
     RECT  75.456 31.861 75.48 35.365 ;
     RECT  75.264 35.365 75.48 35.411 ;
     RECT  10.464 34.355 10.488 35.459 ;
     RECT  28.272 35.173 38.136 35.507 ;
     RECT  17.904 34.501 19.944 35.555 ;
     RECT  39.264 35.363 62.112 35.603 ;
     RECT  21.792 35.171 27.24 35.699 ;
     RECT  39.264 35.603 60.12 35.699 ;
     RECT  3.936 34.115 3.96 35.843 ;
     RECT  39.264 35.699 42.024 35.891 ;
     RECT  12.912 34.741 13.512 36.035 ;
     RECT  75.264 35.411 75.288 36.035 ;
     RECT  13.104 36.035 13.512 36.037 ;
     RECT  72.096 34.931 72.912 36.131 ;
     RECT  39.312 35.891 42.024 36.227 ;
     RECT  13.104 36.037 13.704 36.275 ;
     RECT  78 34.883 78.312 36.277 ;
     RECT  43.152 35.699 60.12 36.467 ;
     RECT  28.272 35.507 36.408 36.515 ;
     RECT  43.344 36.467 47.736 36.611 ;
     RECT  63.696 34.211 65.4 36.613 ;
     RECT  21.888 35.699 27.24 36.661 ;
     RECT  29.232 36.515 36.408 36.661 ;
     RECT  37.44 35.507 38.136 36.661 ;
     RECT  48.912 36.467 60.12 36.755 ;
     RECT  63.696 36.613 65.688 36.755 ;
     RECT  6.24 34.069 6.264 36.757 ;
     RECT  5.76 36.757 6.264 36.803 ;
     RECT  7.8 31.811 8.664 36.805 ;
     RECT  10.272 36.277 10.296 36.805 ;
     RECT  7.8 36.805 10.296 36.851 ;
     RECT  29.232 36.661 38.136 36.851 ;
     RECT  61.488 35.603 62.112 36.949 ;
     RECT  61.488 36.949 62.28 36.997 ;
     RECT  48.96 36.755 60.12 37.043 ;
     RECT  15.312 35.317 15.96 37.091 ;
     RECT  21.792 36.661 27.24 37.093 ;
     RECT  15.936 37.091 15.96 37.187 ;
     RECT  18.48 35.555 19.752 37.187 ;
     RECT  43.584 36.611 47.736 37.283 ;
     RECT  54.432 37.043 60.12 37.331 ;
     RECT  7.8 36.851 9.336 37.379 ;
     RECT  21.792 37.093 27.912 37.427 ;
     RECT  29.28 36.851 38.136 37.427 ;
     RECT  40.2 36.227 42.024 37.525 ;
     RECT  21.792 37.427 27.24 37.573 ;
     RECT  29.4 37.427 38.136 37.619 ;
     RECT  9.312 37.379 9.336 37.667 ;
     RECT  54.432 37.331 59.592 37.667 ;
     RECT  61.44 36.997 62.376 37.667 ;
     RECT  78 36.277 78.792 37.667 ;
     RECT  43.728 37.283 47.736 38.003 ;
     RECT  37.776 37.619 38.136 38.005 ;
     RECT  75.84 37.045 75.864 38.099 ;
     RECT  48.96 37.043 53.4 38.101 ;
     RECT  54.432 37.667 55.224 38.101 ;
     RECT  29.4 37.619 36.744 38.195 ;
     RECT  5.76 36.803 6.168 38.243 ;
     RECT  13.2 36.275 13.704 38.243 ;
     RECT  44.112 38.003 47.736 38.243 ;
     RECT  63.696 36.755 65.592 38.245 ;
     RECT  63.6 38.245 65.592 38.387 ;
     RECT  21.456 37.573 27.24 38.531 ;
     RECT  72.6 36.131 72.912 38.533 ;
     RECT  48.96 38.101 55.224 38.677 ;
     RECT  56.304 37.667 59.592 38.677 ;
     RECT  21.696 38.531 27.24 38.771 ;
     RECT  17.04 38.677 17.064 38.819 ;
     RECT  21.696 38.771 24.408 38.867 ;
     RECT  37.776 38.005 38.952 38.867 ;
     RECT  48.96 38.677 60.504 38.915 ;
     RECT  74.688 37.957 74.712 38.965 ;
     RECT  67.008 33.971 70.92 39.011 ;
     RECT  74.688 38.965 75.48 39.011 ;
     RECT  25.92 38.771 27.24 39.109 ;
     RECT  40.2 37.525 42.216 39.157 ;
     RECT  63.696 38.387 65.592 39.253 ;
     RECT  67.008 39.011 69.864 39.253 ;
     RECT  78 37.667 78.312 39.253 ;
     RECT  72.048 38.533 72.912 39.347 ;
     RECT  25.92 39.109 28.104 39.395 ;
     RECT  63.696 39.253 69.864 39.443 ;
     RECT  24 38.867 24.408 39.539 ;
     RECT  63.696 39.443 65.4 39.587 ;
     RECT  44.112 38.243 46.344 39.635 ;
     RECT  47.52 38.243 47.736 39.635 ;
     RECT  75.456 39.011 75.48 39.731 ;
     RECT  61.68 37.667 62.376 39.827 ;
     RECT  5.76 38.243 5.784 39.923 ;
     RECT  16.944 39.781 16.968 39.923 ;
     RECT  25.92 39.395 25.944 39.923 ;
     RECT  77.136 39.253 78.312 39.923 ;
     RECT  40.2 39.157 42.6 40.019 ;
     RECT  29.4 38.195 32.664 40.021 ;
     RECT  33.648 38.195 36.744 40.021 ;
     RECT  61.68 39.827 62.112 40.163 ;
     RECT  27.216 39.395 28.104 40.165 ;
     RECT  48.96 38.915 58.2 40.355 ;
     RECT  7.8 37.379 8.112 40.405 ;
     RECT  37.776 38.867 38.136 40.453 ;
     RECT  4.464 39.301 4.488 40.499 ;
     RECT  56.4 40.355 58.2 40.499 ;
     RECT  59.568 38.915 60.504 40.499 ;
     RECT  63.696 39.587 63.72 40.499 ;
     RECT  72.6 39.347 72.912 40.645 ;
     RECT  21.696 38.867 22.728 40.739 ;
     RECT  29.4 40.021 36.744 40.835 ;
     RECT  44.256 39.635 46.344 40.883 ;
     RECT  64.704 39.587 65.4 40.979 ;
     RECT  30.816 40.835 36.744 41.027 ;
     RECT  37.728 40.453 38.136 41.027 ;
     RECT  58.176 40.499 58.2 41.027 ;
     RECT  6.816 40.405 8.112 41.075 ;
     RECT  65.328 40.979 65.4 41.075 ;
     RECT  7.8 41.075 8.112 41.125 ;
     RECT  30.816 41.027 36.312 41.171 ;
     RECT  26.16 40.405 26.184 41.173 ;
     RECT  45.6 40.883 46.344 41.365 ;
     RECT  47.712 39.635 47.736 41.365 ;
     RECT  65.328 41.075 65.352 41.411 ;
     RECT  45.6 41.365 47.736 41.507 ;
     RECT  78 39.923 78.312 41.509 ;
     RECT  47.712 41.507 47.736 41.557 ;
     RECT  48.96 40.355 55.224 41.557 ;
     RECT  47.712 41.557 55.224 41.603 ;
     RECT  30.816 41.171 31.944 41.651 ;
     RECT  33.312 41.171 36.312 41.651 ;
     RECT  30.816 41.651 31.848 41.699 ;
     RECT  54.432 41.603 55.224 41.699 ;
     RECT  77.52 41.509 78.312 41.749 ;
     RECT  7.8 41.125 8.232 41.939 ;
     RECT  14.784 40.597 14.808 41.939 ;
     RECT  34.704 41.651 36.312 41.939 ;
     RECT  30.816 41.699 31.704 41.941 ;
     RECT  40.2 40.019 41.976 42.035 ;
     RECT  54.432 41.699 54.552 42.035 ;
     RECT  27.216 40.165 28.392 42.085 ;
     RECT  29.4 40.835 29.712 42.085 ;
     RECT  17.472 40.981 17.496 42.133 ;
     RECT  40.2 42.035 41.928 42.227 ;
     RECT  44.256 40.883 44.28 42.229 ;
     RECT  26.16 41.173 26.232 42.275 ;
     RECT  16.848 42.133 17.496 42.419 ;
     RECT  13.2 38.243 13.512 42.565 ;
     RECT  36.288 41.939 36.312 42.565 ;
     RECT  37.776 41.027 38.136 42.565 ;
     RECT  70.896 39.011 70.92 42.565 ;
     RECT  72 40.645 72.912 42.565 ;
     RECT  75.744 40.117 75.768 42.565 ;
     RECT  77.184 41.749 78.312 42.565 ;
     RECT  40.2 42.227 40.776 42.613 ;
     RECT  30.72 41.941 31.704 42.661 ;
     RECT  30.72 42.661 32.088 42.707 ;
     RECT  21.696 40.739 22.536 42.709 ;
     RECT  75.744 42.565 78.312 42.755 ;
     RECT  27.216 42.085 29.712 42.803 ;
     RECT  45.6 41.507 46.344 42.803 ;
     RECT  31.68 42.707 32.088 42.901 ;
     RECT  43.536 42.229 44.28 42.995 ;
     RECT  47.712 41.603 53.4 42.995 ;
     RECT  7.8 41.939 8.112 42.997 ;
     RECT  61.8 40.163 62.112 42.997 ;
     RECT  54.432 42.035 54.456 43.043 ;
     RECT  44.256 42.995 44.28 43.093 ;
     RECT  59.568 40.499 59.592 43.093 ;
     RECT  74.64 43.045 74.664 43.093 ;
     RECT  75.744 42.755 76.536 43.093 ;
     RECT  56.4 40.499 56.712 43.141 ;
     RECT  67.008 39.443 69.864 43.141 ;
     RECT  16.848 42.419 16.872 43.237 ;
     RECT  33.312 41.651 33.336 43.237 ;
     RECT  74.64 43.093 76.536 43.237 ;
     RECT  13.056 42.565 13.512 43.285 ;
     RECT  66.912 43.141 69.864 43.285 ;
     RECT  48.96 42.995 53.4 43.379 ;
     RECT  12.096 43.285 13.512 43.381 ;
     RECT  21.696 42.709 23.016 43.427 ;
     RECT  33.312 43.237 33.576 43.475 ;
     RECT  48.96 43.379 49.944 43.619 ;
     RECT  26.208 42.275 26.232 43.715 ;
     RECT  18.6 37.187 19.752 43.765 ;
     RECT  27.216 42.803 27.624 43.765 ;
     RECT  18.6 43.765 20.136 43.813 ;
     RECT  2.4 32.243 2.712 43.861 ;
     RECT  3.744 43.285 3.768 43.861 ;
     RECT  7.8 42.997 8.52 43.861 ;
     RECT  34.704 41.939 35.112 43.907 ;
     RECT  18.384 43.813 20.136 43.955 ;
     RECT  70.896 42.565 72.912 43.955 ;
     RECT  36.288 42.565 38.136 44.003 ;
     RECT  6.816 43.861 8.52 44.051 ;
     RECT  66.528 43.285 69.864 44.051 ;
     RECT  31.68 42.901 32.136 44.053 ;
     RECT  33.312 43.475 33.336 44.053 ;
     RECT  65.52 42.709 65.544 44.053 ;
     RECT  65.376 44.053 65.544 44.099 ;
     RECT  66.912 44.051 69.864 44.101 ;
     RECT  70.896 43.955 70.92 44.101 ;
     RECT  66.912 44.101 70.92 44.291 ;
     RECT  45.6 42.803 46.152 44.293 ;
     RECT  11.424 43.381 13.512 44.339 ;
     RECT  34.8 43.907 35.112 44.389 ;
     RECT  36.288 44.003 36.312 44.389 ;
     RECT  74.448 43.237 76.536 44.435 ;
     RECT  49.92 43.619 49.944 44.437 ;
     RECT  51 43.379 53.4 44.437 ;
     RECT  74.448 44.435 75.768 44.437 ;
     RECT  77.76 42.755 78.312 44.437 ;
     RECT  16.56 43.237 16.872 44.483 ;
     RECT  31.68 44.053 33.336 44.483 ;
     RECT  47.712 42.995 47.928 44.483 ;
     RECT  44.256 43.093 44.52 44.533 ;
     RECT  45.6 44.293 46.536 44.533 ;
     RECT  6.816 44.051 8.232 44.579 ;
     RECT  39.36 42.613 40.776 44.629 ;
     RECT  41.904 42.227 41.928 44.629 ;
     RECT  28.656 42.803 29.712 44.773 ;
     RECT  49.92 44.437 53.4 44.773 ;
     RECT  44.256 44.533 46.536 44.867 ;
     RECT  44.256 44.867 44.52 44.869 ;
     RECT  26.256 43.765 27.624 44.915 ;
     RECT  28.656 44.773 30.6 44.915 ;
     RECT  61.584 42.997 62.112 44.915 ;
     RECT  49.92 44.773 53.784 44.917 ;
     RECT  39.36 44.629 41.928 44.963 ;
     RECT  49.92 44.917 54.12 44.963 ;
     RECT  47.712 44.483 47.736 44.965 ;
     RECT  56.4 43.141 57.24 45.013 ;
     RECT  74.4 44.437 75.768 45.059 ;
     RECT  74.544 45.059 75.768 45.107 ;
     RECT  28.656 44.915 29.712 45.203 ;
     RECT  50.112 44.963 54.12 45.203 ;
     RECT  21.696 43.427 22.536 45.301 ;
     RECT  24 39.539 24.312 45.301 ;
     RECT  70.896 44.291 70.92 45.301 ;
     RECT  72 43.955 72.912 45.301 ;
     RECT  26.256 44.915 27.24 45.491 ;
     RECT  20.112 43.955 20.136 45.541 ;
     RECT  11.424 44.339 12.168 45.587 ;
     RECT  15.504 44.965 15.528 45.587 ;
     RECT  40.2 44.963 41.928 45.635 ;
     RECT  45.6 44.867 46.536 45.635 ;
     RECT  7.8 44.579 8.232 45.781 ;
     RECT  11.952 45.587 12.168 45.827 ;
     RECT  13.2 44.339 13.512 45.829 ;
     RECT  16.848 44.483 16.872 45.829 ;
     RECT  43.728 44.869 44.52 45.877 ;
     RECT  16.848 45.829 17.064 45.973 ;
     RECT  16.656 45.973 17.064 46.019 ;
     RECT  13.104 45.829 13.512 46.067 ;
     RECT  18.384 43.955 18.912 46.069 ;
     RECT  70.896 45.301 72.912 46.069 ;
     RECT  18.384 46.069 19.032 46.115 ;
     RECT  31.68 44.483 32.472 46.117 ;
     RECT  31.248 46.117 32.472 46.211 ;
     RECT  21.696 45.301 24.312 46.259 ;
     RECT  56.4 45.013 57.624 46.261 ;
     RECT  2.4 43.861 3.768 46.309 ;
     RECT  31.248 46.211 31.704 46.645 ;
     RECT  34.8 44.389 36.312 46.645 ;
     RECT  7.8 45.781 9 46.693 ;
     RECT  18.6 46.115 19.032 46.693 ;
     RECT  20.112 45.541 20.232 46.693 ;
     RECT  11.952 45.827 11.976 46.787 ;
     RECT  18.6 46.693 20.232 46.787 ;
     RECT  50.688 45.203 54.12 46.787 ;
     RECT  65.376 44.099 65.4 46.789 ;
     RECT  66.912 44.291 69.864 46.789 ;
     RECT  2.304 46.309 3.768 46.835 ;
     RECT  16.656 46.019 16.872 46.835 ;
     RECT  65.376 46.789 69.864 46.835 ;
     RECT  47.568 44.965 47.736 46.885 ;
     RECT  40.2 45.635 40.68 47.077 ;
     RECT  74.88 45.107 75.768 47.269 ;
     RECT  70.896 46.069 73.224 47.363 ;
     RECT  33.024 46.501 33.048 47.411 ;
     RECT  13.2 46.067 13.512 47.461 ;
     RECT  53.76 46.787 54.12 47.555 ;
     RECT  6.048 46.357 6.072 47.605 ;
     RECT  31.2 46.645 31.704 47.653 ;
     RECT  56.016 46.261 57.624 47.653 ;
     RECT  40.08 47.077 40.68 47.701 ;
     RECT  41.904 45.635 41.928 47.701 ;
     RECT  27.216 45.491 27.24 47.845 ;
     RECT  51 46.787 52.728 47.845 ;
     RECT  53.76 47.555 53.832 47.845 ;
     RECT  55.968 47.653 57.624 47.845 ;
     RECT  59.328 43.093 59.592 47.845 ;
     RECT  77.712 44.437 78.312 47.845 ;
     RECT  7.8 46.693 9.192 47.891 ;
     RECT  34.368 46.645 36.312 47.891 ;
     RECT  47.568 46.885 48.504 47.891 ;
     RECT  51 47.845 53.832 47.891 ;
     RECT  21.696 46.259 22.056 48.083 ;
     RECT  25.344 45.541 25.368 48.133 ;
     RECT  4.56 46.837 4.584 48.179 ;
     RECT  6.048 47.605 6.792 48.179 ;
     RECT  59.232 47.845 59.592 48.277 ;
     RECT  74.88 47.269 76.44 48.323 ;
     RECT  18.6 46.787 19.992 48.373 ;
     RECT  21.696 48.083 21.912 48.373 ;
     RECT  77.712 47.845 78.84 48.373 ;
     RECT  25.344 48.133 25.992 48.419 ;
     RECT  7.8 47.891 9.096 48.469 ;
     RECT  14.976 47.413 15 48.469 ;
     RECT  18.6 48.373 21.912 48.515 ;
     RECT  67.2 46.835 69.864 48.517 ;
     RECT  40.08 47.701 41.928 48.611 ;
     RECT  27.216 47.845 27.336 48.659 ;
     RECT  55.824 47.845 57.624 48.709 ;
     RECT  58.752 48.277 59.592 48.709 ;
     RECT  55.824 48.709 59.592 48.755 ;
     RECT  67.104 48.517 69.864 48.755 ;
     RECT  47.568 47.891 47.736 48.901 ;
     RECT  31.2 47.653 32.232 48.949 ;
     RECT  59.232 48.755 59.592 48.949 ;
     RECT  24 46.259 24.312 48.997 ;
     RECT  14.976 48.469 15.384 49.043 ;
     RECT  55.824 48.755 57.048 49.043 ;
     RECT  7.68 48.469 9.096 49.091 ;
     RECT  58.128 48.755 58.248 49.091 ;
     RECT  77.52 48.373 78.84 49.187 ;
     RECT  51 47.891 53.208 49.235 ;
     RECT  47.328 48.901 47.736 49.331 ;
     RECT  55.824 49.043 56.712 49.331 ;
     RECT  40.08 48.611 40.68 49.333 ;
     RECT  70.896 47.363 72.912 49.381 ;
     RECT  41.904 48.611 41.928 49.477 ;
     RECT  43.728 45.877 44.568 49.477 ;
     RECT  12.432 47.461 13.512 49.525 ;
     RECT  39.84 49.333 40.68 49.525 ;
     RECT  41.904 49.477 44.568 49.525 ;
     RECT  75.744 48.323 76.44 49.525 ;
     RECT  58.128 49.091 58.152 49.571 ;
     RECT  59.232 48.949 60.456 49.571 ;
     RECT  27.216 48.659 27.24 49.573 ;
     RECT  19.968 48.515 21.912 49.715 ;
     RECT  20.352 49.715 21.912 49.763 ;
     RECT  30.816 48.949 32.232 49.811 ;
     RECT  14.976 49.043 15 49.861 ;
     RECT  20.784 49.763 21.912 49.861 ;
     RECT  23.04 48.997 24.312 49.861 ;
     RECT  20.784 49.861 24.312 49.907 ;
     RECT  29.4 45.203 29.712 49.909 ;
     RECT  31.248 49.811 32.232 49.957 ;
     RECT  75.216 49.525 76.44 50.003 ;
     RECT  41.904 49.525 44.616 50.101 ;
     RECT  45.6 45.635 45.912 50.101 ;
     RECT  59.568 49.571 60.456 50.101 ;
     RECT  54.24 48.901 54.264 50.147 ;
     RECT  65.376 46.835 66.024 50.147 ;
     RECT  77.52 49.187 78.312 50.149 ;
     RECT  49.968 49.477 49.992 50.195 ;
     RECT  41.904 50.101 45.912 50.243 ;
     RECT  59.568 50.101 60.504 50.243 ;
     RECT  56.256 49.331 56.712 50.245 ;
     RECT  59.568 50.243 60.456 50.435 ;
     RECT  39.168 49.525 40.68 50.531 ;
     RECT  6.048 48.179 6.072 50.533 ;
     RECT  7.68 49.091 8.568 50.533 ;
     RECT  18.6 48.515 18.912 50.533 ;
     RECT  27.12 49.573 27.24 50.579 ;
     RECT  24 49.907 24.312 50.629 ;
     RECT  25.344 48.419 25.368 50.629 ;
     RECT  63.84 50.533 63.864 50.675 ;
     RECT  34.8 47.891 36.312 50.677 ;
     RECT  37.776 44.003 38.136 50.677 ;
     RECT  59.568 50.435 59.592 50.677 ;
     RECT  43.392 50.243 45.912 50.723 ;
     RECT  56.256 50.245 56.808 50.723 ;
     RECT  29.4 49.909 29.832 50.725 ;
     RECT  14.544 49.861 15 50.771 ;
     RECT  20.784 49.907 22.248 50.771 ;
     RECT  31.248 49.957 32.28 50.771 ;
     RECT  75.216 50.003 76.344 50.771 ;
     RECT  11.808 49.525 13.512 50.819 ;
     RECT  34.8 50.677 38.136 50.867 ;
     RECT  31.68 50.771 32.28 50.915 ;
     RECT  12.768 50.819 13.512 50.917 ;
     RECT  14.544 50.771 14.952 50.917 ;
     RECT  24 50.629 25.368 50.917 ;
     RECT  12.768 50.917 14.952 50.963 ;
     RECT  39.84 50.531 40.68 50.963 ;
     RECT  27.216 50.579 27.24 50.965 ;
     RECT  76.32 50.771 76.344 51.059 ;
     RECT  16.848 46.835 16.872 51.061 ;
     RECT  16.56 51.061 16.872 51.107 ;
     RECT  24 50.917 25.896 51.109 ;
     RECT  45.6 50.723 45.912 51.205 ;
     RECT  29.4 50.725 30.264 51.251 ;
     RECT  10.128 50.149 10.152 51.253 ;
     RECT  77.52 50.149 78.552 51.253 ;
     RECT  9.552 51.253 10.152 51.347 ;
     RECT  20.784 50.771 21.96 51.491 ;
     RECT  6.048 50.533 8.568 51.541 ;
     RECT  9.552 51.347 9.576 51.541 ;
     RECT  18.6 50.533 19.368 51.637 ;
     RECT  65.376 50.147 65.88 51.637 ;
     RECT  43.392 50.723 44.616 51.683 ;
     RECT  77.52 51.253 78.84 51.683 ;
     RECT  61.8 44.915 62.112 51.685 ;
     RECT  61.8 51.685 63.096 51.875 ;
     RECT  58.656 50.677 59.592 51.923 ;
     RECT  56.256 50.723 56.712 51.971 ;
     RECT  33.696 50.389 33.72 52.117 ;
     RECT  34.8 50.867 36.6 52.117 ;
     RECT  33.696 52.117 36.6 52.163 ;
     RECT  13.2 50.963 14.952 52.165 ;
     RECT  65.376 51.637 66.168 52.309 ;
     RECT  67.2 48.755 69.864 52.309 ;
     RECT  21.264 51.491 21.96 52.405 ;
     RECT  29.4 51.251 30.12 52.405 ;
     RECT  31.68 50.915 32.232 52.405 ;
     RECT  6.048 51.541 9.576 52.499 ;
     RECT  13.2 52.165 15.432 52.499 ;
     RECT  51 49.235 52.728 52.549 ;
     RECT  18.6 51.637 20.184 52.645 ;
     RECT  21.264 52.405 22.2 52.645 ;
     RECT  58.656 51.923 58.68 52.691 ;
     RECT  40.08 50.963 40.68 52.693 ;
     RECT  50.112 52.549 52.728 52.787 ;
     RECT  75.792 52.309 75.816 52.789 ;
     RECT  7.68 52.499 9.576 52.979 ;
     RECT  23.856 51.109 25.896 52.981 ;
     RECT  39.36 52.693 40.68 53.027 ;
     RECT  41.904 50.243 41.976 53.029 ;
     RECT  44.256 51.683 44.616 53.075 ;
     RECT  47.712 49.331 47.736 53.075 ;
     RECT  70.896 49.381 73.224 53.075 ;
     RECT  75.264 52.789 75.816 53.075 ;
     RECT  44.256 53.075 44.28 53.125 ;
     RECT  41.904 53.029 42.792 53.171 ;
     RECT  50.112 52.787 52.68 53.219 ;
     RECT  18.6 52.645 22.2 53.267 ;
     RECT  48.768 52.405 48.792 53.365 ;
     RECT  50.112 53.219 52.584 53.365 ;
     RECT  56.4 51.971 56.712 53.365 ;
     RECT  2.304 46.835 3.288 53.507 ;
     RECT  2.304 53.507 2.856 53.555 ;
     RECT  12.144 52.981 12.168 53.555 ;
     RECT  48.768 53.365 52.584 53.557 ;
     RECT  71.904 53.075 73.224 53.557 ;
     RECT  4.752 51.061 4.776 53.603 ;
     RECT  29.4 52.405 32.232 53.603 ;
     RECT  45.6 51.205 46.728 53.603 ;
     RECT  13.2 52.499 14.328 53.749 ;
     RECT  15.408 52.499 15.432 53.749 ;
     RECT  27.216 50.965 28.2 53.797 ;
     RECT  29.4 53.603 29.832 53.797 ;
     RECT  21.696 53.267 22.2 53.843 ;
     RECT  63.792 52.981 63.816 54.083 ;
     RECT  61.8 51.875 62.112 54.085 ;
     RECT  16.56 51.107 16.584 54.179 ;
     RECT  23.856 52.981 26.232 54.179 ;
     RECT  71.904 53.557 73.272 54.323 ;
     RECT  2.4 53.555 2.856 54.371 ;
     RECT  18.6 53.267 19.032 54.421 ;
     RECT  20.16 53.267 20.184 54.421 ;
     RECT  23.856 54.179 24.6 54.469 ;
     RECT  13.2 53.749 15.432 54.563 ;
     RECT  27.216 53.797 29.832 54.563 ;
     RECT  65.376 52.309 69.864 54.563 ;
     RECT  48.48 53.557 52.584 54.611 ;
     RECT  61.8 54.085 62.808 54.611 ;
     RECT  7.68 52.979 8.76 54.613 ;
     RECT  4.032 54.325 4.056 54.661 ;
     RECT  21.696 53.843 21.96 54.661 ;
     RECT  22.992 54.469 24.6 54.707 ;
     RECT  25.68 54.179 26.232 54.709 ;
     RECT  27.216 54.563 29.712 54.709 ;
     RECT  43.92 53.125 44.28 54.755 ;
     RECT  58.128 53.557 58.152 54.755 ;
     RECT  61.8 54.611 62.712 54.755 ;
     RECT  71.904 54.323 72.912 54.755 ;
     RECT  48.48 54.611 49.128 54.853 ;
     RECT  33.84 52.163 36.6 54.899 ;
     RECT  65.808 54.563 69.864 55.043 ;
     RECT  78 51.683 78.84 55.139 ;
     RECT  31.68 53.603 32.232 55.141 ;
     RECT  21.648 54.661 21.96 55.237 ;
     RECT  40.08 53.027 40.68 55.237 ;
     RECT  47.856 54.853 49.128 55.331 ;
     RECT  25.68 54.709 29.712 55.379 ;
     RECT  60 54.181 60.024 55.379 ;
     RECT  39.504 55.237 40.68 55.427 ;
     RECT  21.648 55.237 22.008 55.523 ;
     RECT  50.112 54.611 52.584 55.621 ;
     RECT  47.856 55.331 48.504 55.715 ;
     RECT  73.968 54.709 73.992 55.715 ;
     RECT  45.6 53.603 46.392 55.717 ;
     RECT  30.768 55.141 32.232 55.763 ;
     RECT  70.896 53.075 70.92 55.765 ;
     RECT  72 54.755 72.912 55.765 ;
     RECT  2.4 54.371 2.808 55.813 ;
     RECT  4.032 54.661 4.296 55.813 ;
     RECT  21.936 55.523 22.008 55.813 ;
     RECT  22.992 54.707 23.016 55.813 ;
     RECT  50.112 55.621 52.92 55.813 ;
     RECT  2.4 55.813 4.296 56.245 ;
     RECT  34.8 54.899 36.6 56.389 ;
     RECT  37.776 50.867 38.136 56.389 ;
     RECT  55.536 53.365 56.712 56.389 ;
     RECT  2.4 56.245 4.488 56.483 ;
     RECT  13.2 54.563 14.952 56.483 ;
     RECT  49.536 55.813 52.92 56.483 ;
     RECT  75.264 53.075 75.288 56.483 ;
     RECT  40.08 55.427 40.68 56.629 ;
     RECT  41.904 53.171 41.928 56.629 ;
     RECT  25.68 55.379 25.704 56.677 ;
     RECT  25.68 56.677 25.992 56.723 ;
     RECT  7.68 54.613 9.672 56.725 ;
     RECT  55.344 56.389 56.712 56.725 ;
     RECT  21.936 55.813 23.016 56.771 ;
     RECT  7.68 56.725 9.72 56.773 ;
     RECT  16.56 56.053 16.584 56.821 ;
     RECT  16.416 56.821 16.584 57.011 ;
     RECT  6.048 52.499 6.072 57.013 ;
     RECT  7.488 56.773 9.72 57.013 ;
     RECT  45.6 55.717 46.632 57.059 ;
     RECT  54.768 56.725 56.712 57.061 ;
     RECT  54.768 57.061 56.808 57.107 ;
     RECT  12 56.773 12.024 57.109 ;
     RECT  15.264 56.725 15.288 57.109 ;
     RECT  6.048 57.013 9.72 57.155 ;
     RECT  31.68 55.763 32.232 57.155 ;
     RECT  34.8 56.389 38.136 57.157 ;
     RECT  24 54.707 24.6 57.203 ;
     RECT  18.6 54.421 20.184 57.253 ;
     RECT  18.6 57.253 20.904 57.299 ;
     RECT  34.704 57.157 38.136 57.299 ;
     RECT  44.256 54.755 44.28 57.301 ;
     RECT  11.28 57.109 12.024 57.347 ;
     RECT  78 55.139 78.504 57.347 ;
     RECT  56.064 57.107 56.808 57.349 ;
     RECT  40.08 56.629 41.928 57.445 ;
     RECT  43.44 57.301 44.28 57.491 ;
     RECT  78 57.347 78.312 57.541 ;
     RECT  7.392 57.155 9.72 57.587 ;
     RECT  24 57.203 24.552 57.635 ;
     RECT  47.856 55.715 47.88 57.685 ;
     RECT  39.792 57.445 41.928 57.829 ;
     RECT  54.768 57.107 54.792 57.875 ;
     RECT  49.728 56.483 52.92 57.973 ;
     RECT  15.264 57.109 15.384 58.069 ;
     RECT  16.416 57.011 16.44 58.069 ;
     RECT  15.264 58.069 16.44 58.115 ;
     RECT  49.728 57.973 53.064 58.115 ;
     RECT  47.856 57.685 48.552 58.117 ;
     RECT  64.992 58.069 65.016 58.117 ;
     RECT  50.112 58.115 53.064 58.163 ;
     RECT  77.52 57.541 78.312 58.163 ;
     RECT  4.464 56.483 4.488 58.355 ;
     RECT  15.84 58.115 16.44 58.549 ;
     RECT  2.4 56.483 3.336 58.645 ;
     RECT  7.392 57.587 8.76 58.645 ;
     RECT  18.6 57.299 19.896 58.645 ;
     RECT  20.88 57.299 20.904 58.645 ;
     RECT  21.936 56.771 21.96 58.645 ;
     RECT  22.992 56.771 23.016 58.645 ;
     RECT  32.208 57.155 32.232 58.645 ;
     RECT  39.792 57.829 42.456 58.645 ;
     RECT  45.6 57.059 46.392 58.645 ;
     RECT  47.808 58.117 48.552 58.645 ;
     RECT  77.856 58.163 78.312 58.645 ;
     RECT  34.704 57.299 36.6 58.691 ;
     RECT  64.752 58.117 65.016 58.691 ;
     RECT  32.208 58.645 32.664 59.029 ;
     RECT  61.8 54.755 62.112 59.125 ;
     RECT  18.6 58.645 20.904 59.173 ;
     RECT  21.936 58.645 23.016 59.173 ;
     RECT  44.256 57.491 44.28 59.221 ;
     RECT  15.84 58.549 16.968 59.267 ;
     RECT  39.456 58.645 42.456 59.267 ;
     RECT  60.96 59.125 62.112 59.267 ;
     RECT  13.2 56.483 14.136 59.269 ;
     RECT  40.2 59.267 42.456 59.315 ;
     RECT  25.968 56.723 25.992 59.461 ;
     RECT  27.216 55.379 29.712 59.461 ;
     RECT  43.92 59.221 44.28 59.461 ;
     RECT  45.6 58.645 48.552 59.461 ;
     RECT  7.392 58.645 9.672 59.555 ;
     RECT  31.488 59.029 32.664 59.605 ;
     RECT  13.056 59.269 14.136 59.747 ;
     RECT  50.736 58.163 53.064 59.747 ;
     RECT  24 57.635 24.312 59.749 ;
     RECT  56.064 57.349 57.048 59.749 ;
     RECT  11.952 57.347 12.024 59.797 ;
     RECT  2.4 58.645 3.96 59.843 ;
     RECT  7.392 59.555 8.76 59.891 ;
     RECT  13.056 59.747 13.8 59.891 ;
     RECT  34.8 58.691 36.6 59.891 ;
     RECT  77.856 58.645 78.888 59.939 ;
     RECT  18.6 59.173 23.016 59.989 ;
     RECT  24 59.749 24.6 59.989 ;
     RECT  31.488 59.605 33.048 60.035 ;
     RECT  25.968 59.461 29.712 60.083 ;
     RECT  18.6 59.989 24.6 60.131 ;
     RECT  11.184 59.797 12.024 60.275 ;
     RECT  19.968 60.131 24.6 60.275 ;
     RECT  58.128 59.605 58.152 60.323 ;
     RECT  51 59.747 53.064 60.371 ;
     RECT  22.656 60.275 24.6 60.373 ;
     RECT  11.184 60.275 11.208 60.421 ;
     RECT  36.288 59.891 36.6 60.421 ;
     RECT  37.776 57.299 38.136 60.421 ;
     RECT  75.216 59.749 75.24 60.467 ;
     RECT  22.656 60.373 24.792 60.515 ;
     RECT  32.208 60.035 33.048 60.515 ;
     RECT  55.344 59.749 57.048 60.661 ;
     RECT  61.8 59.267 62.112 60.661 ;
     RECT  66.336 55.043 69.864 60.661 ;
     RECT  43.92 59.461 48.552 60.707 ;
     RECT  55.248 60.661 57.048 60.899 ;
     RECT  18.6 60.131 18.912 60.949 ;
     RECT  22.656 60.515 23.016 61.043 ;
     RECT  34.8 59.891 35.112 61.045 ;
     RECT  42.432 59.315 42.456 61.045 ;
     RECT  56.4 60.899 57.048 61.093 ;
     RECT  64.752 58.691 64.776 61.237 ;
     RECT  65.808 60.661 69.864 61.237 ;
     RECT  61.632 60.661 62.112 61.333 ;
     RECT  55.248 60.899 55.416 61.427 ;
     RECT  10.944 60.421 11.208 61.429 ;
     RECT  56.4 61.093 57.24 61.429 ;
     RECT  77.856 59.939 78.312 61.477 ;
     RECT  40.2 59.315 41.208 61.525 ;
     RECT  36.288 60.421 38.136 61.573 ;
     RECT  61.152 61.333 62.112 61.573 ;
     RECT  19.968 60.275 21.144 61.619 ;
     RECT  64.752 61.237 69.864 61.621 ;
     RECT  18.24 60.949 18.912 61.667 ;
     RECT  25.968 60.083 25.992 61.765 ;
     RECT  40.2 61.525 41.4 61.765 ;
     RECT  77.856 61.477 78.84 61.765 ;
     RECT  25.968 61.765 26.088 61.811 ;
     RECT  54.096 60.853 54.12 61.859 ;
     RECT  22.752 61.043 23.016 61.861 ;
     RECT  24 60.515 24.792 61.861 ;
     RECT  55.392 61.427 55.416 61.955 ;
     RECT  44.256 60.707 48.552 62.101 ;
     RECT  34.8 61.045 35.208 62.149 ;
     RECT  36.288 61.573 38.232 62.149 ;
     RECT  27.216 60.083 29.712 62.195 ;
     RECT  44.256 62.101 48.696 62.195 ;
     RECT  64.608 61.621 69.864 62.195 ;
     RECT  34.8 62.149 38.232 62.243 ;
     RECT  51 60.371 52.92 62.389 ;
     RECT  22.752 61.861 24.792 62.435 ;
     RECT  42.432 61.045 43.272 62.435 ;
     RECT  21.12 61.619 21.144 62.437 ;
     RECT  51 62.389 53.064 62.485 ;
     RECT  50.592 62.485 53.064 62.533 ;
     RECT  15.84 59.267 16.44 62.581 ;
     RECT  39.936 61.765 41.4 62.581 ;
     RECT  42.432 62.435 42.456 62.581 ;
     RECT  19.968 61.619 19.992 62.629 ;
     RECT  21.12 62.437 21.576 62.629 ;
     RECT  39.936 62.581 42.456 62.675 ;
     RECT  32.208 60.515 32.232 62.677 ;
     RECT  37.68 62.243 38.232 62.677 ;
     RECT  67.2 62.195 69.864 62.677 ;
     RECT  70.896 55.765 72.912 62.677 ;
     RECT  34.8 62.243 36.312 62.723 ;
     RECT  18.6 61.667 18.912 62.725 ;
     RECT  19.968 62.629 21.576 62.725 ;
     RECT  22.752 62.435 22.776 62.771 ;
     RECT  26.064 61.811 26.088 62.771 ;
     RECT  39.936 62.675 42.216 62.771 ;
     RECT  47.808 62.195 48.696 62.771 ;
     RECT  77.472 61.765 78.84 62.771 ;
     RECT  18.6 62.725 21.576 62.819 ;
     RECT  67.2 62.677 72.912 62.819 ;
     RECT  60.96 61.573 62.112 62.821 ;
     RECT  13.2 59.891 13.8 62.867 ;
     RECT  64.608 62.195 65.832 63.011 ;
     RECT  50.592 62.533 53.304 63.013 ;
     RECT  10.944 61.429 11.304 63.061 ;
     RECT  37.68 62.677 38.664 63.061 ;
     RECT  37.68 63.061 38.808 63.155 ;
     RECT  37.776 63.155 38.808 63.203 ;
     RECT  60.288 62.821 62.112 63.205 ;
     RECT  18.6 62.819 19.656 63.251 ;
     RECT  75.552 61.189 75.576 63.251 ;
     RECT  15.312 62.581 16.968 63.299 ;
     RECT  44.256 62.195 46.824 63.443 ;
     RECT  10.944 63.061 11.4 63.445 ;
     RECT  27.216 62.195 27.96 63.539 ;
     RECT  74.016 62.581 74.04 63.779 ;
     RECT  50.448 63.013 53.304 63.829 ;
     RECT  70.896 62.819 72.912 63.829 ;
     RECT  24 62.435 24.792 63.875 ;
     RECT  60.288 63.205 62.232 63.875 ;
     RECT  37.776 63.203 38.136 63.971 ;
     RECT  27.936 63.539 27.96 64.019 ;
     RECT  29.136 62.195 29.712 64.021 ;
     RECT  56.4 61.429 57.336 64.115 ;
     RECT  29.088 64.021 29.712 64.117 ;
     RECT  29.088 64.117 30.36 64.163 ;
     RECT  20.688 62.819 21.576 64.259 ;
     RECT  20.88 64.259 21.576 64.355 ;
     RECT  63.36 63.205 63.384 64.355 ;
     RECT  4.944 64.117 4.968 64.357 ;
     RECT  6.048 57.155 6.072 64.357 ;
     RECT  7.584 59.891 8.76 64.357 ;
     RECT  18.6 63.251 19.464 64.357 ;
     RECT  31.536 62.677 32.232 64.357 ;
     RECT  47.808 62.771 48.552 64.405 ;
     RECT  10.848 63.445 11.4 64.453 ;
     RECT  10.848 64.453 11.688 64.549 ;
     RECT  13.2 62.867 13.512 64.549 ;
     RECT  10.848 64.549 13.512 64.595 ;
     RECT  34.8 62.723 35.208 64.597 ;
     RECT  36.288 62.723 36.312 64.597 ;
     RECT  63.936 64.405 63.96 64.597 ;
     RECT  76.08 64.357 76.104 64.597 ;
     RECT  77.52 62.771 78.84 64.597 ;
     RECT  2.4 59.843 3.384 64.645 ;
     RECT  31.488 64.357 32.232 64.693 ;
     RECT  34.8 64.597 36.312 64.789 ;
     RECT  31.488 64.693 32.664 64.835 ;
     RECT  56.4 64.115 56.712 64.885 ;
     RECT  15.312 63.299 15.336 64.981 ;
     RECT  18.6 64.357 19.752 65.027 ;
     RECT  31.488 64.835 32.232 65.027 ;
     RECT  37.776 63.971 37.848 65.027 ;
     RECT  44.256 63.443 46.776 65.027 ;
     RECT  58.656 63.157 58.68 65.027 ;
     RECT  61.152 63.875 62.232 65.027 ;
     RECT  50.448 63.829 53.832 65.123 ;
     RECT  7.584 64.357 9.48 65.171 ;
     RECT  20.88 64.355 21.144 65.171 ;
     RECT  34.8 64.789 36.456 65.171 ;
     RECT  70.896 63.829 73.56 65.171 ;
     RECT  4.944 64.357 6.072 65.221 ;
     RECT  11.664 64.595 13.512 65.221 ;
     RECT  40.2 62.771 42.216 65.269 ;
     RECT  52.896 65.123 53.832 65.315 ;
     RECT  47.808 64.405 49.176 65.317 ;
     RECT  45.024 65.027 46.776 65.363 ;
     RECT  63.936 64.597 64.056 65.363 ;
     RECT  37.824 65.027 37.848 65.507 ;
     RECT  15.12 64.981 15.336 65.555 ;
     RECT  34.8 65.171 35.688 65.603 ;
     RECT  50.592 65.123 51.312 65.603 ;
     RECT  61.152 65.027 62.112 65.605 ;
     RECT  71.904 65.171 73.56 65.653 ;
     RECT  11.664 65.221 14.04 65.749 ;
     RECT  16.416 63.299 16.968 65.749 ;
     RECT  71.904 65.653 73.704 65.795 ;
     RECT  60.288 65.605 62.112 65.843 ;
     RECT  16.416 65.749 17.256 65.939 ;
     RECT  55.92 64.885 56.712 65.987 ;
     RECT  17.232 65.939 17.256 65.989 ;
     RECT  18.6 65.027 19.464 66.035 ;
     RECT  63.12 65.701 63.144 66.035 ;
     RECT  45.024 65.363 46.008 66.037 ;
     RECT  20.88 65.171 21 66.133 ;
     RECT  22.992 63.781 23.016 66.179 ;
     RECT  2.4 64.645 3.672 66.277 ;
     RECT  4.656 65.221 6.072 66.277 ;
     RECT  9.792 65.221 9.816 66.325 ;
     RECT  27.6 65.509 27.624 66.325 ;
     RECT  27.6 66.325 27.864 66.371 ;
     RECT  20.448 66.133 21 66.373 ;
     RECT  40.2 65.269 42.552 66.467 ;
     RECT  50.784 65.603 51.312 66.517 ;
     RECT  9.792 66.325 10.2 66.563 ;
     RECT  2.4 66.277 6.072 66.661 ;
     RECT  7.584 65.171 8.76 66.661 ;
     RECT  20.064 66.373 21 66.661 ;
     RECT  38.256 66.181 38.28 66.661 ;
     RECT  20.064 66.661 21.096 66.707 ;
     RECT  47.76 65.317 49.176 66.707 ;
     RECT  10.176 66.563 10.2 66.755 ;
     RECT  20.064 66.707 20.088 66.755 ;
     RECT  44.496 66.037 46.008 66.755 ;
     RECT  76.08 64.597 78.84 66.755 ;
     RECT  21.072 66.707 21.096 66.851 ;
     RECT  50.784 66.517 51.816 66.899 ;
     RECT  74.832 66.805 74.856 66.947 ;
     RECT  2.4 66.661 8.76 66.995 ;
     RECT  22.608 66.181 22.632 67.043 ;
     RECT  42.528 66.467 42.552 67.043 ;
     RECT  48.48 66.707 49.176 67.045 ;
     RECT  50.784 66.899 51.312 67.045 ;
     RECT  48.48 67.045 51.312 67.091 ;
     RECT  11.664 65.749 14.28 67.093 ;
     RECT  52.896 65.315 53.304 67.237 ;
     RECT  61.152 65.843 62.112 67.237 ;
     RECT  67.2 62.819 69.864 67.237 ;
     RECT  70.896 65.171 70.92 67.237 ;
     RECT  17.232 65.989 17.352 67.283 ;
     RECT  27.84 66.371 27.864 67.283 ;
     RECT  65.232 63.011 65.832 67.283 ;
     RECT  15.312 65.555 15.336 67.285 ;
     RECT  17.328 67.283 17.352 67.379 ;
     RECT  52.896 67.237 53.448 67.381 ;
     RECT  54.72 65.653 54.744 67.381 ;
     RECT  15.312 67.285 15.384 67.429 ;
     RECT  5.664 66.995 8.76 67.573 ;
     RECT  2.4 66.995 4.536 67.619 ;
     RECT  65.568 67.283 65.832 67.619 ;
     RECT  56.4 65.987 56.712 67.669 ;
     RECT  34.8 65.603 35.112 67.717 ;
     RECT  44.496 66.755 45.912 67.765 ;
     RECT  71.904 65.795 72.912 67.765 ;
     RECT  38.256 66.661 38.76 67.811 ;
     RECT  76.752 66.755 78.84 67.811 ;
     RECT  10.896 67.093 14.28 67.859 ;
     RECT  61.152 67.237 62.712 67.859 ;
     RECT  65.568 67.619 65.592 67.859 ;
     RECT  71.904 67.765 73.56 67.859 ;
     RECT  32.208 65.027 32.232 67.861 ;
     RECT  56.4 67.669 56.808 67.861 ;
     RECT  25.872 67.765 25.896 67.955 ;
     RECT  56.256 67.861 56.808 68.003 ;
     RECT  63.84 66.661 63.864 68.053 ;
     RECT  59.424 67.957 59.448 68.099 ;
     RECT  18.6 66.035 18.912 68.245 ;
     RECT  40.2 66.467 41.208 68.245 ;
     RECT  63.648 68.053 63.864 68.245 ;
     RECT  24 63.875 24.312 68.293 ;
     RECT  32.208 67.861 32.664 68.293 ;
     RECT  10.896 67.859 14.184 68.341 ;
     RECT  24 68.293 24.792 68.341 ;
     RECT  38.256 67.811 38.28 68.341 ;
     RECT  52.896 67.381 54.744 68.389 ;
     RECT  56.4 68.003 56.808 68.435 ;
     RECT  43.536 67.765 45.912 68.437 ;
     RECT  10.704 68.341 14.184 68.483 ;
     RECT  10.704 68.483 11.688 68.627 ;
     RECT  63.648 68.245 64.056 68.627 ;
     RECT  15.312 67.429 15.48 68.677 ;
     RECT  29.4 64.163 30.36 68.677 ;
     RECT  34.8 67.717 35.928 68.677 ;
     RECT  3.984 67.619 4.536 68.723 ;
     RECT  29.232 68.677 30.36 68.725 ;
     RECT  52.896 68.389 54.984 68.725 ;
     RECT  40.08 68.245 41.208 68.821 ;
     RECT  38.208 68.341 38.28 68.869 ;
     RECT  40.08 68.821 42.168 68.869 ;
     RECT  49.104 67.091 51.312 68.869 ;
     RECT  52.416 68.725 54.984 68.869 ;
     RECT  11.232 68.627 11.688 68.915 ;
     RECT  32.208 68.293 33.144 68.915 ;
     RECT  43.536 68.437 46.008 68.915 ;
     RECT  67.2 67.237 70.92 68.915 ;
     RECT  2.4 67.619 2.712 68.917 ;
     RECT  3.984 68.723 4.056 68.917 ;
     RECT  12.96 68.483 14.184 68.917 ;
     RECT  15.312 68.677 16.056 68.917 ;
     RECT  47.616 68.101 47.64 68.917 ;
     RECT  49.104 68.869 54.984 68.917 ;
     RECT  67.2 68.915 69.72 68.917 ;
     RECT  76.752 67.811 76.776 68.917 ;
     RECT  77.76 67.811 78.84 68.917 ;
     RECT  32.208 68.915 33.096 69.059 ;
     RECT  66.72 68.917 69.72 69.059 ;
     RECT  69.6 69.059 69.72 69.155 ;
     RECT  20.544 68.341 20.568 69.203 ;
     RECT  34.224 68.677 35.928 69.203 ;
     RECT  69.696 69.155 69.72 69.203 ;
     RECT  12.96 68.917 16.056 69.205 ;
     RECT  76.704 68.917 76.776 69.205 ;
     RECT  77.76 68.917 79.08 69.205 ;
     RECT  38.208 68.869 42.168 69.253 ;
     RECT  44.448 68.915 46.008 69.253 ;
     RECT  47.616 68.917 54.984 69.253 ;
     RECT  44.448 69.253 54.984 69.301 ;
     RECT  70.704 68.915 70.92 69.301 ;
     RECT  70.704 69.301 71.112 69.347 ;
     RECT  72.336 67.859 73.56 69.347 ;
     RECT  29.088 68.725 30.36 69.349 ;
     RECT  38.208 69.253 43.032 69.395 ;
     RECT  61.152 67.859 62.112 69.397 ;
     RECT  12.96 69.205 16.104 69.493 ;
     RECT  76.704 69.205 79.08 69.493 ;
     RECT  76.704 69.493 79.8 69.539 ;
     RECT  33.024 69.059 33.096 69.587 ;
     RECT  34.224 69.203 35.544 69.587 ;
     RECT  44.448 69.301 55.272 69.635 ;
     RECT  45.456 69.635 55.272 69.683 ;
     RECT  45.456 69.683 49.752 69.731 ;
     RECT  70.896 69.347 71.112 69.779 ;
     RECT  66.72 69.059 68.472 69.923 ;
     RECT  28.656 69.349 30.36 69.973 ;
     RECT  72.336 69.347 72.912 70.021 ;
     RECT  2.4 68.917 4.056 70.067 ;
     RECT  3.936 70.067 4.056 70.069 ;
     RECT  71.088 69.779 71.112 70.115 ;
     RECT  12.528 69.493 16.104 70.163 ;
     RECT  45.6 69.731 49.752 70.163 ;
     RECT  12.528 70.163 14.424 70.211 ;
     RECT  50.88 69.683 55.272 70.211 ;
     RECT  61.008 69.397 62.112 70.211 ;
     RECT  28.656 69.973 31.272 70.259 ;
     RECT  37.152 69.493 37.176 70.259 ;
     RECT  28.656 70.259 30.36 70.307 ;
     RECT  12.528 70.211 13.752 70.451 ;
     RECT  33.024 69.587 33.048 70.499 ;
     RECT  47.52 70.163 49.752 70.499 ;
     RECT  50.88 70.211 54.984 70.499 ;
     RECT  77.088 69.539 79.8 70.499 ;
     RECT  56.4 68.435 56.712 70.501 ;
     RECT  3.936 70.069 4.2 70.547 ;
     RECT  28.656 70.307 30.264 70.547 ;
     RECT  38.304 69.395 43.032 70.547 ;
     RECT  74.64 67.717 74.664 70.547 ;
     RECT  5.664 67.573 9.48 70.643 ;
     RECT  11.232 68.915 11.256 70.643 ;
     RECT  18.6 68.245 19.032 70.645 ;
     RECT  34.8 69.587 35.544 70.645 ;
     RECT  12.528 70.451 13.704 70.691 ;
     RECT  18 70.645 19.032 70.693 ;
     RECT  3.984 70.547 4.2 70.739 ;
     RECT  15.408 70.163 16.104 70.739 ;
     RECT  6.048 70.643 9.48 70.787 ;
     RECT  39.168 70.547 43.032 70.787 ;
     RECT  75.696 69.733 75.72 70.787 ;
     RECT  64.032 68.627 64.056 70.789 ;
     RECT  6.048 70.787 6.072 70.835 ;
     RECT  12.528 70.691 13.656 70.835 ;
     RECT  63.12 70.789 64.056 70.835 ;
     RECT  66.768 69.923 68.472 70.883 ;
     RECT  7.44 70.787 9.48 71.027 ;
     RECT  7.584 71.027 9.48 71.075 ;
     RECT  20.736 70.069 20.76 71.075 ;
     RECT  24 68.341 25.512 71.075 ;
     RECT  56.4 70.501 56.952 71.221 ;
     RECT  58.032 69.493 58.056 71.221 ;
     RECT  12.96 70.835 13.656 71.267 ;
     RECT  4.176 70.739 4.2 71.269 ;
     RECT  24 71.075 24.456 71.269 ;
     RECT  28.944 70.547 30.264 71.269 ;
     RECT  18 70.693 19.704 71.315 ;
     RECT  25.44 71.075 25.512 71.315 ;
     RECT  50.88 70.499 54.024 71.315 ;
     RECT  59.376 70.069 59.4 71.315 ;
     RECT  18 71.315 18.912 71.363 ;
     RECT  39.36 70.787 43.032 71.363 ;
     RECT  71.04 71.221 71.064 71.461 ;
     RECT  39.888 71.363 43.032 71.651 ;
     RECT  61.68 70.211 62.112 71.699 ;
     RECT  72.192 70.021 72.912 71.699 ;
     RECT  13.008 71.267 13.656 71.747 ;
     RECT  23.76 71.269 24.456 71.795 ;
     RECT  4.176 71.269 5.064 71.843 ;
     RECT  7.584 71.075 9.24 71.843 ;
     RECT  13.008 71.747 13.608 71.843 ;
     RECT  16.08 70.739 16.104 71.843 ;
     RECT  28.944 71.269 30.744 71.843 ;
     RECT  51 71.315 54.024 71.843 ;
     RECT  56.4 71.221 58.056 71.843 ;
     RECT  52.848 71.843 53.976 71.891 ;
     RECT  52.944 71.891 53.976 71.939 ;
     RECT  71.04 71.461 71.112 72.035 ;
     RECT  56.4 71.843 57.624 72.131 ;
     RECT  23.76 71.795 24.312 72.179 ;
     RECT  39.888 71.651 42.216 72.179 ;
     RECT  78 70.499 79.8 72.229 ;
     RECT  66.768 70.883 67.8 72.371 ;
     RECT  71.04 72.035 71.064 72.373 ;
     RECT  2.4 70.067 2.856 72.419 ;
     RECT  22.176 71.797 22.2 72.419 ;
     RECT  28.944 71.843 29.88 72.419 ;
     RECT  34.8 70.645 36.072 72.419 ;
     RECT  39.888 72.179 41.64 72.419 ;
     RECT  25.44 71.315 25.464 72.467 ;
     RECT  70.08 72.373 71.064 72.467 ;
     RECT  4.512 71.843 5.064 72.659 ;
     RECT  52.944 71.939 53.784 72.659 ;
     RECT  47.52 70.499 49.272 72.661 ;
     RECT  51 71.843 51.312 72.661 ;
     RECT  45.6 70.163 45.912 72.709 ;
     RECT  4.512 72.659 4.536 72.755 ;
     RECT  13.2 71.843 13.608 72.803 ;
     RECT  28.944 72.419 29.712 72.803 ;
     RECT  7.584 71.843 8.76 72.851 ;
     RECT  44.448 69.635 44.472 72.901 ;
     RECT  47.52 72.661 49.704 72.947 ;
     RECT  65.232 70.405 65.256 72.947 ;
     RECT  66.768 72.371 67.512 72.947 ;
     RECT  48.672 72.947 49.704 72.995 ;
     RECT  70.08 72.467 70.104 72.995 ;
     RECT  44.16 72.901 44.472 73.043 ;
     RECT  52.944 72.659 53.304 73.043 ;
     RECT  72.336 71.699 72.912 73.043 ;
     RECT  38.256 72.853 38.28 73.235 ;
     RECT  61.8 71.699 62.112 73.381 ;
     RECT  59.952 72.037 59.976 73.523 ;
     RECT  56.4 72.131 56.808 73.571 ;
     RECT  63.12 70.835 63.144 73.571 ;
     RECT  77.088 72.229 79.8 73.571 ;
     RECT  50.736 72.661 51.312 73.715 ;
     RECT  40.2 72.419 41.64 74.099 ;
     RECT  24 72.179 24.312 74.101 ;
     RECT  7.584 72.851 8.112 74.147 ;
     RECT  44.16 73.043 44.184 74.147 ;
     RECT  45.504 72.709 45.912 74.147 ;
     RECT  48.672 72.995 48.696 74.147 ;
     RECT  49.68 72.995 49.704 74.147 ;
     RECT  60.96 73.381 62.112 74.147 ;
     RECT  47.52 72.947 47.544 74.387 ;
     RECT  10.848 72.901 10.872 74.389 ;
     RECT  34.8 72.419 35.88 74.389 ;
     RECT  40.2 74.099 40.776 74.437 ;
     RECT  37.344 73.477 37.368 74.483 ;
     RECT  29.4 72.803 29.712 74.677 ;
     RECT  34.656 74.389 35.88 74.723 ;
     RECT  77.232 73.571 79.8 74.723 ;
     RECT  7.8 74.147 8.112 75.253 ;
     RECT  10.176 74.389 10.872 75.253 ;
     RECT  13.2 72.803 13.512 75.253 ;
     RECT  23.904 74.101 24.312 75.253 ;
     RECT  28.8 74.677 29.712 75.253 ;
     RECT  39.264 74.437 40.776 75.253 ;
     RECT  45.6 74.147 45.912 75.253 ;
     RECT  67.2 72.947 67.512 75.253 ;
     RECT  72.6 73.043 72.912 75.253 ;
     RECT  52.416 73.381 52.44 75.299 ;
     RECT  34.656 74.723 35.592 75.395 ;
     RECT  2.4 72.419 2.712 75.609 ;
     RECT  18.6 71.363 18.912 75.609 ;
     RECT  44.4 75.253 45.912 75.609 ;
     RECT  51 73.715 51.312 75.609 ;
     RECT  61.8 74.147 62.112 75.609 ;
     RECT  2.4 75.609 2.52 75.623 ;
     RECT  7.8 75.253 15.816 75.623 ;
     RECT  18.6 75.609 18.72 75.623 ;
     RECT  34.8 75.395 35.592 75.623 ;
     RECT  44.4 75.609 45.72 75.623 ;
     RECT  51 75.609 51.12 75.623 ;
     RECT  61.8 75.609 61.92 75.623 ;
     RECT  67.2 75.253 73.512 75.623 ;
     RECT  78 74.723 79.8 75.623 ;
     RECT  44.4 75.623 45.576 75.685 ;
     RECT  54.624 75.541 54.648 75.685 ;
     RECT  60.48 75.253 60.504 75.685 ;
     RECT  38.592 75.253 42.12 75.733 ;
     RECT  54.624 75.685 55.128 75.733 ;
     RECT  56.4 73.571 56.712 75.733 ;
     RECT  58.368 75.253 58.392 75.733 ;
     RECT  59.76 75.685 60.504 75.733 ;
     RECT  23.472 75.253 24.408 75.781 ;
     RECT  25.536 75.253 27.432 75.781 ;
     RECT  28.8 75.253 30.456 75.781 ;
     RECT  38.592 75.733 43.032 75.781 ;
     RECT  44.16 75.685 45.576 75.781 ;
     RECT  54.432 75.733 56.712 75.781 ;
     RECT  58.368 75.733 60.504 75.781 ;
     RECT  68.16 75.623 73.512 75.781 ;
     RECT  74.688 75.253 74.712 75.781 ;
     RECT  38.592 75.781 45.576 76.933 ;
     RECT  35.568 75.623 35.592 77.699 ;
     RECT  78.384 75.623 79.8 77.699 ;
     RECT  8.544 75.623 15.816 77.712 ;
     RECT  23.472 75.781 30.696 77.712 ;
     RECT  38.352 76.933 45.576 77.712 ;
     RECT  53.232 75.781 60.504 77.712 ;
     RECT  68.16 75.781 75.384 77.712 ;
  END
END ot_hgi_coll_fj_n2s1_r128
END LIBRARY
